VERSION 5.7 ;
  NOWIREEXTENSIONATPIN ON ;
  DIVIDERCHAR "/" ;
  BUSBITCHARS "[]" ;
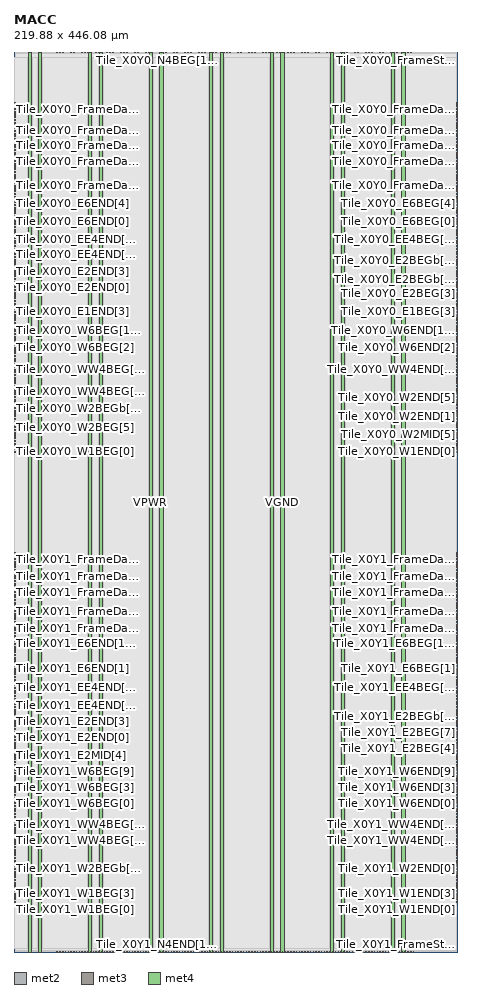
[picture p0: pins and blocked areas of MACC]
MACRO MACC
  CLASS BLOCK ;
  FOREIGN MACC ;
  ORIGIN 0.000 0.000 ;
  SIZE 219.880 BY 446.080 ;
  PIN Tile_X0Y0_CO
    DIRECTION OUTPUT ;
    USE SIGNAL ;
    ANTENNADIFFAREA 0.702900 ;
    PORT
      LAYER met2 ;
        RECT 98.530 445.800 98.810 446.080 ;
    END
  END Tile_X0Y0_CO
  PIN Tile_X0Y0_E1BEG[0]
    DIRECTION OUTPUT ;
    USE SIGNAL ;
    ANTENNADIFFAREA 0.702900 ;
    PORT
      LAYER met3 ;
        RECT 219.280 312.840 219.880 313.440 ;
    END
  END Tile_X0Y0_E1BEG[0]
  PIN Tile_X0Y0_E1BEG[1]
    DIRECTION OUTPUT ;
    USE SIGNAL ;
    ANTENNADIFFAREA 0.702900 ;
    PORT
      LAYER met3 ;
        RECT 219.280 314.200 219.880 314.800 ;
    END
  END Tile_X0Y0_E1BEG[1]
  PIN Tile_X0Y0_E1BEG[2]
    DIRECTION OUTPUT ;
    USE SIGNAL ;
    ANTENNADIFFAREA 0.702900 ;
    PORT
      LAYER met3 ;
        RECT 219.280 315.560 219.880 316.160 ;
    END
  END Tile_X0Y0_E1BEG[2]
  PIN Tile_X0Y0_E1BEG[3]
    DIRECTION OUTPUT ;
    USE SIGNAL ;
    ANTENNADIFFAREA 0.702900 ;
    PORT
      LAYER met3 ;
        RECT 219.280 316.920 219.880 317.520 ;
    END
  END Tile_X0Y0_E1BEG[3]
  PIN Tile_X0Y0_E1END[0]
    DIRECTION INPUT ;
    USE SIGNAL ;
    ANTENNAGATEAREA 2.603100 ;
    ANTENNADIFFAREA 1.304100 ;
    PORT
      LAYER met3 ;
        RECT 0.000 312.840 0.600 313.440 ;
    END
  END Tile_X0Y0_E1END[0]
  PIN Tile_X0Y0_E1END[1]
    DIRECTION INPUT ;
    USE SIGNAL ;
    ANTENNAGATEAREA 0.939000 ;
    PORT
      LAYER met3 ;
        RECT 0.000 314.200 0.600 314.800 ;
    END
  END Tile_X0Y0_E1END[1]
  PIN Tile_X0Y0_E1END[2]
    DIRECTION INPUT ;
    USE SIGNAL ;
    ANTENNAGATEAREA 1.749000 ;
    PORT
      LAYER met3 ;
        RECT 0.000 315.560 0.600 316.160 ;
    END
  END Tile_X0Y0_E1END[2]
  PIN Tile_X0Y0_E1END[3]
    DIRECTION INPUT ;
    USE SIGNAL ;
    ANTENNAGATEAREA 3.131400 ;
    ANTENNADIFFAREA 0.869400 ;
    PORT
      LAYER met3 ;
        RECT 0.000 316.920 0.600 317.520 ;
    END
  END Tile_X0Y0_E1END[3]
  PIN Tile_X0Y0_E2BEG[0]
    DIRECTION OUTPUT ;
    USE SIGNAL ;
    ANTENNADIFFAREA 0.702900 ;
    PORT
      LAYER met3 ;
        RECT 219.280 318.280 219.880 318.880 ;
    END
  END Tile_X0Y0_E2BEG[0]
  PIN Tile_X0Y0_E2BEG[1]
    DIRECTION OUTPUT ;
    USE SIGNAL ;
    ANTENNADIFFAREA 0.702900 ;
    PORT
      LAYER met3 ;
        RECT 219.280 319.640 219.880 320.240 ;
    END
  END Tile_X0Y0_E2BEG[1]
  PIN Tile_X0Y0_E2BEG[2]
    DIRECTION OUTPUT ;
    USE SIGNAL ;
    ANTENNADIFFAREA 0.702900 ;
    PORT
      LAYER met3 ;
        RECT 219.280 321.000 219.880 321.600 ;
    END
  END Tile_X0Y0_E2BEG[2]
  PIN Tile_X0Y0_E2BEG[3]
    DIRECTION OUTPUT ;
    USE SIGNAL ;
    ANTENNADIFFAREA 0.702900 ;
    PORT
      LAYER met3 ;
        RECT 219.280 322.360 219.880 322.960 ;
    END
  END Tile_X0Y0_E2BEG[3]
  PIN Tile_X0Y0_E2BEG[4]
    DIRECTION OUTPUT ;
    USE SIGNAL ;
    ANTENNADIFFAREA 0.702900 ;
    PORT
      LAYER met3 ;
        RECT 219.280 323.720 219.880 324.320 ;
    END
  END Tile_X0Y0_E2BEG[4]
  PIN Tile_X0Y0_E2BEG[5]
    DIRECTION OUTPUT ;
    USE SIGNAL ;
    ANTENNADIFFAREA 0.702900 ;
    PORT
      LAYER met3 ;
        RECT 219.280 325.080 219.880 325.680 ;
    END
  END Tile_X0Y0_E2BEG[5]
  PIN Tile_X0Y0_E2BEG[6]
    DIRECTION OUTPUT ;
    USE SIGNAL ;
    ANTENNADIFFAREA 0.702900 ;
    PORT
      LAYER met3 ;
        RECT 219.280 326.440 219.880 327.040 ;
    END
  END Tile_X0Y0_E2BEG[6]
  PIN Tile_X0Y0_E2BEG[7]
    DIRECTION OUTPUT ;
    USE SIGNAL ;
    ANTENNADIFFAREA 0.702900 ;
    PORT
      LAYER met3 ;
        RECT 219.280 327.800 219.880 328.400 ;
    END
  END Tile_X0Y0_E2BEG[7]
  PIN Tile_X0Y0_E2BEGb[0]
    DIRECTION OUTPUT ;
    USE SIGNAL ;
    ANTENNADIFFAREA 0.702900 ;
    PORT
      LAYER met3 ;
        RECT 219.280 329.160 219.880 329.760 ;
    END
  END Tile_X0Y0_E2BEGb[0]
  PIN Tile_X0Y0_E2BEGb[1]
    DIRECTION OUTPUT ;
    USE SIGNAL ;
    ANTENNADIFFAREA 0.702900 ;
    PORT
      LAYER met3 ;
        RECT 219.280 330.520 219.880 331.120 ;
    END
  END Tile_X0Y0_E2BEGb[1]
  PIN Tile_X0Y0_E2BEGb[2]
    DIRECTION OUTPUT ;
    USE SIGNAL ;
    ANTENNADIFFAREA 0.702900 ;
    PORT
      LAYER met3 ;
        RECT 219.280 331.880 219.880 332.480 ;
    END
  END Tile_X0Y0_E2BEGb[2]
  PIN Tile_X0Y0_E2BEGb[3]
    DIRECTION OUTPUT ;
    USE SIGNAL ;
    ANTENNADIFFAREA 0.702900 ;
    PORT
      LAYER met3 ;
        RECT 219.280 333.240 219.880 333.840 ;
    END
  END Tile_X0Y0_E2BEGb[3]
  PIN Tile_X0Y0_E2BEGb[4]
    DIRECTION OUTPUT ;
    USE SIGNAL ;
    ANTENNADIFFAREA 0.702900 ;
    PORT
      LAYER met3 ;
        RECT 219.280 334.600 219.880 335.200 ;
    END
  END Tile_X0Y0_E2BEGb[4]
  PIN Tile_X0Y0_E2BEGb[5]
    DIRECTION OUTPUT ;
    USE SIGNAL ;
    ANTENNADIFFAREA 0.702900 ;
    PORT
      LAYER met3 ;
        RECT 219.280 335.960 219.880 336.560 ;
    END
  END Tile_X0Y0_E2BEGb[5]
  PIN Tile_X0Y0_E2BEGb[6]
    DIRECTION OUTPUT ;
    USE SIGNAL ;
    ANTENNADIFFAREA 0.702900 ;
    PORT
      LAYER met3 ;
        RECT 219.280 337.320 219.880 337.920 ;
    END
  END Tile_X0Y0_E2BEGb[6]
  PIN Tile_X0Y0_E2BEGb[7]
    DIRECTION OUTPUT ;
    USE SIGNAL ;
    ANTENNADIFFAREA 0.702900 ;
    PORT
      LAYER met3 ;
        RECT 219.280 338.680 219.880 339.280 ;
    END
  END Tile_X0Y0_E2BEGb[7]
  PIN Tile_X0Y0_E2END[0]
    DIRECTION INPUT ;
    USE SIGNAL ;
    ANTENNAGATEAREA 0.971700 ;
    ANTENNADIFFAREA 0.434700 ;
    PORT
      LAYER met3 ;
        RECT 0.000 329.160 0.600 329.760 ;
    END
  END Tile_X0Y0_E2END[0]
  PIN Tile_X0Y0_E2END[1]
    DIRECTION INPUT ;
    USE SIGNAL ;
    ANTENNAGATEAREA 0.636000 ;
    PORT
      LAYER met3 ;
        RECT 0.000 330.520 0.600 331.120 ;
    END
  END Tile_X0Y0_E2END[1]
  PIN Tile_X0Y0_E2END[2]
    DIRECTION INPUT ;
    USE SIGNAL ;
    ANTENNAGATEAREA 1.168500 ;
    PORT
      LAYER met3 ;
        RECT 0.000 331.880 0.600 332.480 ;
    END
  END Tile_X0Y0_E2END[2]
  PIN Tile_X0Y0_E2END[3]
    DIRECTION INPUT ;
    USE SIGNAL ;
    ANTENNAGATEAREA 1.173000 ;
    PORT
      LAYER met3 ;
        RECT 0.000 333.240 0.600 333.840 ;
    END
  END Tile_X0Y0_E2END[3]
  PIN Tile_X0Y0_E2END[4]
    DIRECTION INPUT ;
    USE SIGNAL ;
    ANTENNAGATEAREA 1.229700 ;
    ANTENNADIFFAREA 0.434700 ;
    PORT
      LAYER met3 ;
        RECT 0.000 334.600 0.600 335.200 ;
    END
  END Tile_X0Y0_E2END[4]
  PIN Tile_X0Y0_E2END[5]
    DIRECTION INPUT ;
    USE SIGNAL ;
    ANTENNAGATEAREA 1.929000 ;
    PORT
      LAYER met3 ;
        RECT 0.000 335.960 0.600 336.560 ;
    END
  END Tile_X0Y0_E2END[5]
  PIN Tile_X0Y0_E2END[6]
    DIRECTION INPUT ;
    USE SIGNAL ;
    ANTENNAGATEAREA 1.388700 ;
    ANTENNADIFFAREA 0.434700 ;
    PORT
      LAYER met3 ;
        RECT 0.000 337.320 0.600 337.920 ;
    END
  END Tile_X0Y0_E2END[6]
  PIN Tile_X0Y0_E2END[7]
    DIRECTION INPUT ;
    USE SIGNAL ;
    ANTENNAGATEAREA 2.099100 ;
    ANTENNADIFFAREA 1.304100 ;
    PORT
      LAYER met3 ;
        RECT 0.000 338.680 0.600 339.280 ;
    END
  END Tile_X0Y0_E2END[7]
  PIN Tile_X0Y0_E2MID[0]
    DIRECTION INPUT ;
    USE SIGNAL ;
    ANTENNAGATEAREA 0.658500 ;
    PORT
      LAYER met3 ;
        RECT 0.000 318.280 0.600 318.880 ;
    END
  END Tile_X0Y0_E2MID[0]
  PIN Tile_X0Y0_E2MID[1]
    DIRECTION INPUT ;
    USE SIGNAL ;
    ANTENNAGATEAREA 0.696000 ;
    PORT
      LAYER met3 ;
        RECT 0.000 319.640 0.600 320.240 ;
    END
  END Tile_X0Y0_E2MID[1]
  PIN Tile_X0Y0_E2MID[2]
    DIRECTION INPUT ;
    USE SIGNAL ;
    ANTENNAGATEAREA 1.037700 ;
    ANTENNADIFFAREA 0.434700 ;
    PORT
      LAYER met3 ;
        RECT 0.000 321.000 0.600 321.600 ;
    END
  END Tile_X0Y0_E2MID[2]
  PIN Tile_X0Y0_E2MID[3]
    DIRECTION INPUT ;
    USE SIGNAL ;
    ANTENNAGATEAREA 0.795000 ;
    PORT
      LAYER met3 ;
        RECT 0.000 322.360 0.600 322.960 ;
    END
  END Tile_X0Y0_E2MID[3]
  PIN Tile_X0Y0_E2MID[4]
    DIRECTION INPUT ;
    USE SIGNAL ;
    ANTENNAGATEAREA 0.972000 ;
    PORT
      LAYER met3 ;
        RECT 0.000 323.720 0.600 324.320 ;
    END
  END Tile_X0Y0_E2MID[4]
  PIN Tile_X0Y0_E2MID[5]
    DIRECTION INPUT ;
    USE SIGNAL ;
    ANTENNAGATEAREA 1.555500 ;
    PORT
      LAYER met3 ;
        RECT 0.000 325.080 0.600 325.680 ;
    END
  END Tile_X0Y0_E2MID[5]
  PIN Tile_X0Y0_E2MID[6]
    DIRECTION INPUT ;
    USE SIGNAL ;
    ANTENNAGATEAREA 1.406700 ;
    ANTENNADIFFAREA 0.434700 ;
    PORT
      LAYER met3 ;
        RECT 0.000 326.440 0.600 327.040 ;
    END
  END Tile_X0Y0_E2MID[6]
  PIN Tile_X0Y0_E2MID[7]
    DIRECTION INPUT ;
    USE SIGNAL ;
    ANTENNAGATEAREA 0.901500 ;
    PORT
      LAYER met3 ;
        RECT 0.000 327.800 0.600 328.400 ;
    END
  END Tile_X0Y0_E2MID[7]
  PIN Tile_X0Y0_E6BEG[0]
    DIRECTION OUTPUT ;
    USE SIGNAL ;
    ANTENNADIFFAREA 0.702900 ;
    PORT
      LAYER met3 ;
        RECT 219.280 361.800 219.880 362.400 ;
    END
  END Tile_X0Y0_E6BEG[0]
  PIN Tile_X0Y0_E6BEG[10]
    DIRECTION OUTPUT ;
    USE SIGNAL ;
    ANTENNADIFFAREA 0.702900 ;
    PORT
      LAYER met3 ;
        RECT 219.280 375.400 219.880 376.000 ;
    END
  END Tile_X0Y0_E6BEG[10]
  PIN Tile_X0Y0_E6BEG[11]
    DIRECTION OUTPUT ;
    USE SIGNAL ;
    ANTENNADIFFAREA 0.702900 ;
    PORT
      LAYER met3 ;
        RECT 219.280 376.760 219.880 377.360 ;
    END
  END Tile_X0Y0_E6BEG[11]
  PIN Tile_X0Y0_E6BEG[1]
    DIRECTION OUTPUT ;
    USE SIGNAL ;
    ANTENNADIFFAREA 0.702900 ;
    PORT
      LAYER met3 ;
        RECT 219.280 363.160 219.880 363.760 ;
    END
  END Tile_X0Y0_E6BEG[1]
  PIN Tile_X0Y0_E6BEG[2]
    DIRECTION OUTPUT ;
    USE SIGNAL ;
    ANTENNADIFFAREA 0.702900 ;
    PORT
      LAYER met3 ;
        RECT 219.280 364.520 219.880 365.120 ;
    END
  END Tile_X0Y0_E6BEG[2]
  PIN Tile_X0Y0_E6BEG[3]
    DIRECTION OUTPUT ;
    USE SIGNAL ;
    ANTENNADIFFAREA 0.702900 ;
    PORT
      LAYER met3 ;
        RECT 219.280 365.880 219.880 366.480 ;
    END
  END Tile_X0Y0_E6BEG[3]
  PIN Tile_X0Y0_E6BEG[4]
    DIRECTION OUTPUT ;
    USE SIGNAL ;
    ANTENNADIFFAREA 0.702900 ;
    PORT
      LAYER met3 ;
        RECT 219.280 367.240 219.880 367.840 ;
    END
  END Tile_X0Y0_E6BEG[4]
  PIN Tile_X0Y0_E6BEG[5]
    DIRECTION OUTPUT ;
    USE SIGNAL ;
    ANTENNADIFFAREA 0.702900 ;
    PORT
      LAYER met3 ;
        RECT 219.280 368.600 219.880 369.200 ;
    END
  END Tile_X0Y0_E6BEG[5]
  PIN Tile_X0Y0_E6BEG[6]
    DIRECTION OUTPUT ;
    USE SIGNAL ;
    ANTENNADIFFAREA 0.702900 ;
    PORT
      LAYER met3 ;
        RECT 219.280 369.960 219.880 370.560 ;
    END
  END Tile_X0Y0_E6BEG[6]
  PIN Tile_X0Y0_E6BEG[7]
    DIRECTION OUTPUT ;
    USE SIGNAL ;
    ANTENNADIFFAREA 0.702900 ;
    PORT
      LAYER met3 ;
        RECT 219.280 371.320 219.880 371.920 ;
    END
  END Tile_X0Y0_E6BEG[7]
  PIN Tile_X0Y0_E6BEG[8]
    DIRECTION OUTPUT ;
    USE SIGNAL ;
    ANTENNADIFFAREA 0.702900 ;
    PORT
      LAYER met3 ;
        RECT 219.280 372.680 219.880 373.280 ;
    END
  END Tile_X0Y0_E6BEG[8]
  PIN Tile_X0Y0_E6BEG[9]
    DIRECTION OUTPUT ;
    USE SIGNAL ;
    ANTENNADIFFAREA 0.702900 ;
    PORT
      LAYER met3 ;
        RECT 219.280 374.040 219.880 374.640 ;
    END
  END Tile_X0Y0_E6BEG[9]
  PIN Tile_X0Y0_E6END[0]
    DIRECTION INPUT ;
    USE SIGNAL ;
    ANTENNAGATEAREA 2.243700 ;
    ANTENNADIFFAREA 0.434700 ;
    PORT
      LAYER met3 ;
        RECT 0.000 361.800 0.600 362.400 ;
    END
  END Tile_X0Y0_E6END[0]
  PIN Tile_X0Y0_E6END[10]
    DIRECTION INPUT ;
    USE SIGNAL ;
    ANTENNAGATEAREA 0.159000 ;
    PORT
      LAYER met3 ;
        RECT 0.000 375.400 0.600 376.000 ;
    END
  END Tile_X0Y0_E6END[10]
  PIN Tile_X0Y0_E6END[11]
    DIRECTION INPUT ;
    USE SIGNAL ;
    ANTENNAGATEAREA 0.159000 ;
    PORT
      LAYER met3 ;
        RECT 0.000 376.760 0.600 377.360 ;
    END
  END Tile_X0Y0_E6END[11]
  PIN Tile_X0Y0_E6END[1]
    DIRECTION INPUT ;
    USE SIGNAL ;
    ANTENNAGATEAREA 1.809000 ;
    PORT
      LAYER met3 ;
        RECT 0.000 363.160 0.600 363.760 ;
    END
  END Tile_X0Y0_E6END[1]
  PIN Tile_X0Y0_E6END[2]
    DIRECTION INPUT ;
    USE SIGNAL ;
    ANTENNAGATEAREA 0.159000 ;
    PORT
      LAYER met3 ;
        RECT 0.000 364.520 0.600 365.120 ;
    END
  END Tile_X0Y0_E6END[2]
  PIN Tile_X0Y0_E6END[3]
    DIRECTION INPUT ;
    USE SIGNAL ;
    ANTENNAGATEAREA 0.159000 ;
    PORT
      LAYER met3 ;
        RECT 0.000 365.880 0.600 366.480 ;
    END
  END Tile_X0Y0_E6END[3]
  PIN Tile_X0Y0_E6END[4]
    DIRECTION INPUT ;
    USE SIGNAL ;
    ANTENNAGATEAREA 0.159000 ;
    PORT
      LAYER met3 ;
        RECT 0.000 367.240 0.600 367.840 ;
    END
  END Tile_X0Y0_E6END[4]
  PIN Tile_X0Y0_E6END[5]
    DIRECTION INPUT ;
    USE SIGNAL ;
    ANTENNAGATEAREA 0.159000 ;
    PORT
      LAYER met3 ;
        RECT 0.000 368.600 0.600 369.200 ;
    END
  END Tile_X0Y0_E6END[5]
  PIN Tile_X0Y0_E6END[6]
    DIRECTION INPUT ;
    USE SIGNAL ;
    ANTENNAGATEAREA 0.159000 ;
    PORT
      LAYER met3 ;
        RECT 0.000 369.960 0.600 370.560 ;
    END
  END Tile_X0Y0_E6END[6]
  PIN Tile_X0Y0_E6END[7]
    DIRECTION INPUT ;
    USE SIGNAL ;
    ANTENNAGATEAREA 0.159000 ;
    PORT
      LAYER met3 ;
        RECT 0.000 371.320 0.600 371.920 ;
    END
  END Tile_X0Y0_E6END[7]
  PIN Tile_X0Y0_E6END[8]
    DIRECTION INPUT ;
    USE SIGNAL ;
    ANTENNAGATEAREA 0.159000 ;
    PORT
      LAYER met3 ;
        RECT 0.000 372.680 0.600 373.280 ;
    END
  END Tile_X0Y0_E6END[8]
  PIN Tile_X0Y0_E6END[9]
    DIRECTION INPUT ;
    USE SIGNAL ;
    ANTENNAGATEAREA 0.159000 ;
    PORT
      LAYER met3 ;
        RECT 0.000 374.040 0.600 374.640 ;
    END
  END Tile_X0Y0_E6END[9]
  PIN Tile_X0Y0_EE4BEG[0]
    DIRECTION OUTPUT ;
    USE SIGNAL ;
    ANTENNADIFFAREA 0.702900 ;
    PORT
      LAYER met3 ;
        RECT 219.280 340.040 219.880 340.640 ;
    END
  END Tile_X0Y0_EE4BEG[0]
  PIN Tile_X0Y0_EE4BEG[10]
    DIRECTION OUTPUT ;
    USE SIGNAL ;
    ANTENNADIFFAREA 0.702900 ;
    PORT
      LAYER met3 ;
        RECT 219.280 353.640 219.880 354.240 ;
    END
  END Tile_X0Y0_EE4BEG[10]
  PIN Tile_X0Y0_EE4BEG[11]
    DIRECTION OUTPUT ;
    USE SIGNAL ;
    ANTENNADIFFAREA 0.702900 ;
    PORT
      LAYER met3 ;
        RECT 219.280 355.000 219.880 355.600 ;
    END
  END Tile_X0Y0_EE4BEG[11]
  PIN Tile_X0Y0_EE4BEG[12]
    DIRECTION OUTPUT ;
    USE SIGNAL ;
    ANTENNADIFFAREA 0.702900 ;
    PORT
      LAYER met3 ;
        RECT 219.280 356.360 219.880 356.960 ;
    END
  END Tile_X0Y0_EE4BEG[12]
  PIN Tile_X0Y0_EE4BEG[13]
    DIRECTION OUTPUT ;
    USE SIGNAL ;
    ANTENNADIFFAREA 0.702900 ;
    PORT
      LAYER met3 ;
        RECT 219.280 357.720 219.880 358.320 ;
    END
  END Tile_X0Y0_EE4BEG[13]
  PIN Tile_X0Y0_EE4BEG[14]
    DIRECTION OUTPUT ;
    USE SIGNAL ;
    ANTENNADIFFAREA 0.702900 ;
    PORT
      LAYER met3 ;
        RECT 219.280 359.080 219.880 359.680 ;
    END
  END Tile_X0Y0_EE4BEG[14]
  PIN Tile_X0Y0_EE4BEG[15]
    DIRECTION OUTPUT ;
    USE SIGNAL ;
    ANTENNADIFFAREA 0.702900 ;
    PORT
      LAYER met3 ;
        RECT 219.280 360.440 219.880 361.040 ;
    END
  END Tile_X0Y0_EE4BEG[15]
  PIN Tile_X0Y0_EE4BEG[1]
    DIRECTION OUTPUT ;
    USE SIGNAL ;
    ANTENNADIFFAREA 0.702900 ;
    PORT
      LAYER met3 ;
        RECT 219.280 341.400 219.880 342.000 ;
    END
  END Tile_X0Y0_EE4BEG[1]
  PIN Tile_X0Y0_EE4BEG[2]
    DIRECTION OUTPUT ;
    USE SIGNAL ;
    ANTENNADIFFAREA 0.702900 ;
    PORT
      LAYER met3 ;
        RECT 219.280 342.760 219.880 343.360 ;
    END
  END Tile_X0Y0_EE4BEG[2]
  PIN Tile_X0Y0_EE4BEG[3]
    DIRECTION OUTPUT ;
    USE SIGNAL ;
    ANTENNADIFFAREA 0.702900 ;
    PORT
      LAYER met3 ;
        RECT 219.280 344.120 219.880 344.720 ;
    END
  END Tile_X0Y0_EE4BEG[3]
  PIN Tile_X0Y0_EE4BEG[4]
    DIRECTION OUTPUT ;
    USE SIGNAL ;
    ANTENNADIFFAREA 0.702900 ;
    PORT
      LAYER met3 ;
        RECT 219.280 345.480 219.880 346.080 ;
    END
  END Tile_X0Y0_EE4BEG[4]
  PIN Tile_X0Y0_EE4BEG[5]
    DIRECTION OUTPUT ;
    USE SIGNAL ;
    ANTENNADIFFAREA 0.702900 ;
    PORT
      LAYER met3 ;
        RECT 219.280 346.840 219.880 347.440 ;
    END
  END Tile_X0Y0_EE4BEG[5]
  PIN Tile_X0Y0_EE4BEG[6]
    DIRECTION OUTPUT ;
    USE SIGNAL ;
    ANTENNADIFFAREA 0.702900 ;
    PORT
      LAYER met3 ;
        RECT 219.280 348.200 219.880 348.800 ;
    END
  END Tile_X0Y0_EE4BEG[6]
  PIN Tile_X0Y0_EE4BEG[7]
    DIRECTION OUTPUT ;
    USE SIGNAL ;
    ANTENNADIFFAREA 0.702900 ;
    PORT
      LAYER met3 ;
        RECT 219.280 349.560 219.880 350.160 ;
    END
  END Tile_X0Y0_EE4BEG[7]
  PIN Tile_X0Y0_EE4BEG[8]
    DIRECTION OUTPUT ;
    USE SIGNAL ;
    ANTENNADIFFAREA 0.702900 ;
    PORT
      LAYER met3 ;
        RECT 219.280 350.920 219.880 351.520 ;
    END
  END Tile_X0Y0_EE4BEG[8]
  PIN Tile_X0Y0_EE4BEG[9]
    DIRECTION OUTPUT ;
    USE SIGNAL ;
    ANTENNADIFFAREA 0.702900 ;
    PORT
      LAYER met3 ;
        RECT 219.280 352.280 219.880 352.880 ;
    END
  END Tile_X0Y0_EE4BEG[9]
  PIN Tile_X0Y0_EE4END[0]
    DIRECTION INPUT ;
    USE SIGNAL ;
    ANTENNAGATEAREA 1.715100 ;
    ANTENNADIFFAREA 1.304100 ;
    PORT
      LAYER met3 ;
        RECT 0.000 340.040 0.600 340.640 ;
    END
  END Tile_X0Y0_EE4END[0]
  PIN Tile_X0Y0_EE4END[10]
    DIRECTION INPUT ;
    USE SIGNAL ;
    ANTENNAGATEAREA 0.159000 ;
    PORT
      LAYER met3 ;
        RECT 0.000 353.640 0.600 354.240 ;
    END
  END Tile_X0Y0_EE4END[10]
  PIN Tile_X0Y0_EE4END[11]
    DIRECTION INPUT ;
    USE SIGNAL ;
    ANTENNAGATEAREA 0.159000 ;
    PORT
      LAYER met3 ;
        RECT 0.000 355.000 0.600 355.600 ;
    END
  END Tile_X0Y0_EE4END[11]
  PIN Tile_X0Y0_EE4END[12]
    DIRECTION INPUT ;
    USE SIGNAL ;
    ANTENNAGATEAREA 0.159000 ;
    PORT
      LAYER met3 ;
        RECT 0.000 356.360 0.600 356.960 ;
    END
  END Tile_X0Y0_EE4END[12]
  PIN Tile_X0Y0_EE4END[13]
    DIRECTION INPUT ;
    USE SIGNAL ;
    ANTENNAGATEAREA 0.159000 ;
    PORT
      LAYER met3 ;
        RECT 0.000 357.720 0.600 358.320 ;
    END
  END Tile_X0Y0_EE4END[13]
  PIN Tile_X0Y0_EE4END[14]
    DIRECTION INPUT ;
    USE SIGNAL ;
    ANTENNAGATEAREA 0.159000 ;
    PORT
      LAYER met3 ;
        RECT 0.000 359.080 0.600 359.680 ;
    END
  END Tile_X0Y0_EE4END[14]
  PIN Tile_X0Y0_EE4END[15]
    DIRECTION INPUT ;
    USE SIGNAL ;
    ANTENNAGATEAREA 0.159000 ;
    PORT
      LAYER met3 ;
        RECT 0.000 360.440 0.600 361.040 ;
    END
  END Tile_X0Y0_EE4END[15]
  PIN Tile_X0Y0_EE4END[1]
    DIRECTION INPUT ;
    USE SIGNAL ;
    ANTENNAGATEAREA 0.477000 ;
    PORT
      LAYER met3 ;
        RECT 0.000 341.400 0.600 342.000 ;
    END
  END Tile_X0Y0_EE4END[1]
  PIN Tile_X0Y0_EE4END[2]
    DIRECTION INPUT ;
    USE SIGNAL ;
    ANTENNAGATEAREA 1.781100 ;
    ANTENNADIFFAREA 1.304100 ;
    PORT
      LAYER met3 ;
        RECT 0.000 342.760 0.600 343.360 ;
    END
  END Tile_X0Y0_EE4END[2]
  PIN Tile_X0Y0_EE4END[3]
    DIRECTION INPUT ;
    USE SIGNAL ;
    ANTENNAGATEAREA 0.752700 ;
    ANTENNADIFFAREA 0.434700 ;
    PORT
      LAYER met3 ;
        RECT 0.000 344.120 0.600 344.720 ;
    END
  END Tile_X0Y0_EE4END[3]
  PIN Tile_X0Y0_EE4END[4]
    DIRECTION INPUT ;
    USE SIGNAL ;
    ANTENNAGATEAREA 0.159000 ;
    PORT
      LAYER met3 ;
        RECT 0.000 345.480 0.600 346.080 ;
    END
  END Tile_X0Y0_EE4END[4]
  PIN Tile_X0Y0_EE4END[5]
    DIRECTION INPUT ;
    USE SIGNAL ;
    ANTENNAGATEAREA 0.159000 ;
    PORT
      LAYER met3 ;
        RECT 0.000 346.840 0.600 347.440 ;
    END
  END Tile_X0Y0_EE4END[5]
  PIN Tile_X0Y0_EE4END[6]
    DIRECTION INPUT ;
    USE SIGNAL ;
    ANTENNAGATEAREA 0.159000 ;
    PORT
      LAYER met3 ;
        RECT 0.000 348.200 0.600 348.800 ;
    END
  END Tile_X0Y0_EE4END[6]
  PIN Tile_X0Y0_EE4END[7]
    DIRECTION INPUT ;
    USE SIGNAL ;
    ANTENNAGATEAREA 0.159000 ;
    PORT
      LAYER met3 ;
        RECT 0.000 349.560 0.600 350.160 ;
    END
  END Tile_X0Y0_EE4END[7]
  PIN Tile_X0Y0_EE4END[8]
    DIRECTION INPUT ;
    USE SIGNAL ;
    ANTENNAGATEAREA 0.159000 ;
    PORT
      LAYER met3 ;
        RECT 0.000 350.920 0.600 351.520 ;
    END
  END Tile_X0Y0_EE4END[8]
  PIN Tile_X0Y0_EE4END[9]
    DIRECTION INPUT ;
    USE SIGNAL ;
    ANTENNAGATEAREA 0.159000 ;
    PORT
      LAYER met3 ;
        RECT 0.000 352.280 0.600 352.880 ;
    END
  END Tile_X0Y0_EE4END[9]
  PIN Tile_X0Y0_FrameData[0]
    DIRECTION INPUT ;
    USE SIGNAL ;
    ANTENNAGATEAREA 2.067000 ;
    PORT
      LAYER met3 ;
        RECT 0.000 378.120 0.600 378.720 ;
    END
  END Tile_X0Y0_FrameData[0]
  PIN Tile_X0Y0_FrameData[10]
    DIRECTION INPUT ;
    USE SIGNAL ;
    ANTENNAGATEAREA 2.226000 ;
    PORT
      LAYER met3 ;
        RECT 0.000 391.720 0.600 392.320 ;
    END
  END Tile_X0Y0_FrameData[10]
  PIN Tile_X0Y0_FrameData[11]
    DIRECTION INPUT ;
    USE SIGNAL ;
    ANTENNAGATEAREA 2.226000 ;
    PORT
      LAYER met3 ;
        RECT 0.000 393.080 0.600 393.680 ;
    END
  END Tile_X0Y0_FrameData[11]
  PIN Tile_X0Y0_FrameData[12]
    DIRECTION INPUT ;
    USE SIGNAL ;
    ANTENNAGATEAREA 2.226000 ;
    PORT
      LAYER met3 ;
        RECT 0.000 394.440 0.600 395.040 ;
    END
  END Tile_X0Y0_FrameData[12]
  PIN Tile_X0Y0_FrameData[13]
    DIRECTION INPUT ;
    USE SIGNAL ;
    ANTENNAGATEAREA 3.095400 ;
    ANTENNADIFFAREA 0.869400 ;
    PORT
      LAYER met3 ;
        RECT 0.000 395.800 0.600 396.400 ;
    END
  END Tile_X0Y0_FrameData[13]
  PIN Tile_X0Y0_FrameData[14]
    DIRECTION INPUT ;
    USE SIGNAL ;
    ANTENNAGATEAREA 2.226000 ;
    PORT
      LAYER met3 ;
        RECT 0.000 397.160 0.600 397.760 ;
    END
  END Tile_X0Y0_FrameData[14]
  PIN Tile_X0Y0_FrameData[15]
    DIRECTION INPUT ;
    USE SIGNAL ;
    ANTENNAGATEAREA 2.226000 ;
    PORT
      LAYER met3 ;
        RECT 0.000 398.520 0.600 399.120 ;
    END
  END Tile_X0Y0_FrameData[15]
  PIN Tile_X0Y0_FrameData[16]
    DIRECTION INPUT ;
    USE SIGNAL ;
    ANTENNAGATEAREA 2.226000 ;
    PORT
      LAYER met3 ;
        RECT 0.000 399.880 0.600 400.480 ;
    END
  END Tile_X0Y0_FrameData[16]
  PIN Tile_X0Y0_FrameData[17]
    DIRECTION INPUT ;
    USE SIGNAL ;
    ANTENNAGATEAREA 2.226000 ;
    PORT
      LAYER met3 ;
        RECT 0.000 401.240 0.600 401.840 ;
    END
  END Tile_X0Y0_FrameData[17]
  PIN Tile_X0Y0_FrameData[18]
    DIRECTION INPUT ;
    USE SIGNAL ;
    ANTENNAGATEAREA 2.226000 ;
    PORT
      LAYER met3 ;
        RECT 0.000 402.600 0.600 403.200 ;
    END
  END Tile_X0Y0_FrameData[18]
  PIN Tile_X0Y0_FrameData[19]
    DIRECTION INPUT ;
    USE SIGNAL ;
    ANTENNAGATEAREA 2.226000 ;
    PORT
      LAYER met3 ;
        RECT 0.000 403.960 0.600 404.560 ;
    END
  END Tile_X0Y0_FrameData[19]
  PIN Tile_X0Y0_FrameData[1]
    DIRECTION INPUT ;
    USE SIGNAL ;
    ANTENNAGATEAREA 2.067000 ;
    PORT
      LAYER met3 ;
        RECT 0.000 379.480 0.600 380.080 ;
    END
  END Tile_X0Y0_FrameData[1]
  PIN Tile_X0Y0_FrameData[20]
    DIRECTION INPUT ;
    USE SIGNAL ;
    ANTENNAGATEAREA 2.226000 ;
    PORT
      LAYER met3 ;
        RECT 0.000 405.320 0.600 405.920 ;
    END
  END Tile_X0Y0_FrameData[20]
  PIN Tile_X0Y0_FrameData[21]
    DIRECTION INPUT ;
    USE SIGNAL ;
    ANTENNAGATEAREA 2.226000 ;
    PORT
      LAYER met3 ;
        RECT 0.000 406.680 0.600 407.280 ;
    END
  END Tile_X0Y0_FrameData[21]
  PIN Tile_X0Y0_FrameData[22]
    DIRECTION INPUT ;
    USE SIGNAL ;
    ANTENNAGATEAREA 2.226000 ;
    PORT
      LAYER met3 ;
        RECT 0.000 408.040 0.600 408.640 ;
    END
  END Tile_X0Y0_FrameData[22]
  PIN Tile_X0Y0_FrameData[23]
    DIRECTION INPUT ;
    USE SIGNAL ;
    ANTENNAGATEAREA 2.226000 ;
    PORT
      LAYER met3 ;
        RECT 0.000 409.400 0.600 410.000 ;
    END
  END Tile_X0Y0_FrameData[23]
  PIN Tile_X0Y0_FrameData[24]
    DIRECTION INPUT ;
    USE SIGNAL ;
    ANTENNAGATEAREA 2.226000 ;
    PORT
      LAYER met3 ;
        RECT 0.000 410.760 0.600 411.360 ;
    END
  END Tile_X0Y0_FrameData[24]
  PIN Tile_X0Y0_FrameData[25]
    DIRECTION INPUT ;
    USE SIGNAL ;
    ANTENNAGATEAREA 2.226000 ;
    PORT
      LAYER met3 ;
        RECT 0.000 412.120 0.600 412.720 ;
    END
  END Tile_X0Y0_FrameData[25]
  PIN Tile_X0Y0_FrameData[26]
    DIRECTION INPUT ;
    USE SIGNAL ;
    ANTENNAGATEAREA 2.226000 ;
    PORT
      LAYER met3 ;
        RECT 0.000 413.480 0.600 414.080 ;
    END
  END Tile_X0Y0_FrameData[26]
  PIN Tile_X0Y0_FrameData[27]
    DIRECTION INPUT ;
    USE SIGNAL ;
    ANTENNAGATEAREA 2.660700 ;
    ANTENNADIFFAREA 0.434700 ;
    PORT
      LAYER met3 ;
        RECT 0.000 414.840 0.600 415.440 ;
    END
  END Tile_X0Y0_FrameData[27]
  PIN Tile_X0Y0_FrameData[28]
    DIRECTION INPUT ;
    USE SIGNAL ;
    ANTENNAGATEAREA 2.226000 ;
    PORT
      LAYER met3 ;
        RECT 0.000 416.200 0.600 416.800 ;
    END
  END Tile_X0Y0_FrameData[28]
  PIN Tile_X0Y0_FrameData[29]
    DIRECTION INPUT ;
    USE SIGNAL ;
    ANTENNAGATEAREA 2.660700 ;
    ANTENNADIFFAREA 0.434700 ;
    PORT
      LAYER met3 ;
        RECT 0.000 417.560 0.600 418.160 ;
    END
  END Tile_X0Y0_FrameData[29]
  PIN Tile_X0Y0_FrameData[2]
    DIRECTION INPUT ;
    USE SIGNAL ;
    ANTENNAGATEAREA 2.501700 ;
    ANTENNADIFFAREA 0.434700 ;
    PORT
      LAYER met3 ;
        RECT 0.000 380.840 0.600 381.440 ;
    END
  END Tile_X0Y0_FrameData[2]
  PIN Tile_X0Y0_FrameData[30]
    DIRECTION INPUT ;
    USE SIGNAL ;
    ANTENNAGATEAREA 2.226000 ;
    PORT
      LAYER met3 ;
        RECT 0.000 418.920 0.600 419.520 ;
    END
  END Tile_X0Y0_FrameData[30]
  PIN Tile_X0Y0_FrameData[31]
    DIRECTION INPUT ;
    USE SIGNAL ;
    ANTENNAGATEAREA 2.226000 ;
    PORT
      LAYER met3 ;
        RECT 0.000 420.280 0.600 420.880 ;
    END
  END Tile_X0Y0_FrameData[31]
  PIN Tile_X0Y0_FrameData[3]
    DIRECTION INPUT ;
    USE SIGNAL ;
    ANTENNAGATEAREA 2.067000 ;
    PORT
      LAYER met3 ;
        RECT 0.000 382.200 0.600 382.800 ;
    END
  END Tile_X0Y0_FrameData[3]
  PIN Tile_X0Y0_FrameData[4]
    DIRECTION INPUT ;
    USE SIGNAL ;
    ANTENNAGATEAREA 2.067000 ;
    PORT
      LAYER met3 ;
        RECT 0.000 383.560 0.600 384.160 ;
    END
  END Tile_X0Y0_FrameData[4]
  PIN Tile_X0Y0_FrameData[5]
    DIRECTION INPUT ;
    USE SIGNAL ;
    ANTENNAGATEAREA 4.240500 ;
    ANTENNADIFFAREA 2.173500 ;
    PORT
      LAYER met3 ;
        RECT 0.000 384.920 0.600 385.520 ;
    END
  END Tile_X0Y0_FrameData[5]
  PIN Tile_X0Y0_FrameData[6]
    DIRECTION INPUT ;
    USE SIGNAL ;
    ANTENNAGATEAREA 2.067000 ;
    PORT
      LAYER met3 ;
        RECT 0.000 386.280 0.600 386.880 ;
    END
  END Tile_X0Y0_FrameData[6]
  PIN Tile_X0Y0_FrameData[7]
    DIRECTION INPUT ;
    USE SIGNAL ;
    ANTENNAGATEAREA 2.067000 ;
    PORT
      LAYER met3 ;
        RECT 0.000 387.640 0.600 388.240 ;
    END
  END Tile_X0Y0_FrameData[7]
  PIN Tile_X0Y0_FrameData[8]
    DIRECTION INPUT ;
    USE SIGNAL ;
    ANTENNAGATEAREA 2.067000 ;
    PORT
      LAYER met3 ;
        RECT 0.000 389.000 0.600 389.600 ;
    END
  END Tile_X0Y0_FrameData[8]
  PIN Tile_X0Y0_FrameData[9]
    DIRECTION INPUT ;
    USE SIGNAL ;
    ANTENNAGATEAREA 2.067000 ;
    PORT
      LAYER met3 ;
        RECT 0.000 390.360 0.600 390.960 ;
    END
  END Tile_X0Y0_FrameData[9]
  PIN Tile_X0Y0_FrameData_O[0]
    DIRECTION OUTPUT ;
    USE SIGNAL ;
    ANTENNADIFFAREA 0.702900 ;
    PORT
      LAYER met3 ;
        RECT 219.280 378.120 219.880 378.720 ;
    END
  END Tile_X0Y0_FrameData_O[0]
  PIN Tile_X0Y0_FrameData_O[10]
    DIRECTION OUTPUT ;
    USE SIGNAL ;
    ANTENNADIFFAREA 0.702900 ;
    PORT
      LAYER met3 ;
        RECT 219.280 391.720 219.880 392.320 ;
    END
  END Tile_X0Y0_FrameData_O[10]
  PIN Tile_X0Y0_FrameData_O[11]
    DIRECTION OUTPUT ;
    USE SIGNAL ;
    ANTENNADIFFAREA 0.702900 ;
    PORT
      LAYER met3 ;
        RECT 219.280 393.080 219.880 393.680 ;
    END
  END Tile_X0Y0_FrameData_O[11]
  PIN Tile_X0Y0_FrameData_O[12]
    DIRECTION OUTPUT ;
    USE SIGNAL ;
    ANTENNADIFFAREA 0.702900 ;
    PORT
      LAYER met3 ;
        RECT 219.280 394.440 219.880 395.040 ;
    END
  END Tile_X0Y0_FrameData_O[12]
  PIN Tile_X0Y0_FrameData_O[13]
    DIRECTION OUTPUT ;
    USE SIGNAL ;
    ANTENNADIFFAREA 0.702900 ;
    PORT
      LAYER met3 ;
        RECT 219.280 395.800 219.880 396.400 ;
    END
  END Tile_X0Y0_FrameData_O[13]
  PIN Tile_X0Y0_FrameData_O[14]
    DIRECTION OUTPUT ;
    USE SIGNAL ;
    ANTENNADIFFAREA 0.702900 ;
    PORT
      LAYER met3 ;
        RECT 219.280 397.160 219.880 397.760 ;
    END
  END Tile_X0Y0_FrameData_O[14]
  PIN Tile_X0Y0_FrameData_O[15]
    DIRECTION OUTPUT ;
    USE SIGNAL ;
    ANTENNADIFFAREA 0.702900 ;
    PORT
      LAYER met3 ;
        RECT 219.280 398.520 219.880 399.120 ;
    END
  END Tile_X0Y0_FrameData_O[15]
  PIN Tile_X0Y0_FrameData_O[16]
    DIRECTION OUTPUT ;
    USE SIGNAL ;
    ANTENNADIFFAREA 0.702900 ;
    PORT
      LAYER met3 ;
        RECT 219.280 399.880 219.880 400.480 ;
    END
  END Tile_X0Y0_FrameData_O[16]
  PIN Tile_X0Y0_FrameData_O[17]
    DIRECTION OUTPUT ;
    USE SIGNAL ;
    ANTENNADIFFAREA 0.702900 ;
    PORT
      LAYER met3 ;
        RECT 219.280 401.240 219.880 401.840 ;
    END
  END Tile_X0Y0_FrameData_O[17]
  PIN Tile_X0Y0_FrameData_O[18]
    DIRECTION OUTPUT ;
    USE SIGNAL ;
    ANTENNADIFFAREA 0.702900 ;
    PORT
      LAYER met3 ;
        RECT 219.280 402.600 219.880 403.200 ;
    END
  END Tile_X0Y0_FrameData_O[18]
  PIN Tile_X0Y0_FrameData_O[19]
    DIRECTION OUTPUT ;
    USE SIGNAL ;
    ANTENNADIFFAREA 0.702900 ;
    PORT
      LAYER met3 ;
        RECT 219.280 403.960 219.880 404.560 ;
    END
  END Tile_X0Y0_FrameData_O[19]
  PIN Tile_X0Y0_FrameData_O[1]
    DIRECTION OUTPUT ;
    USE SIGNAL ;
    ANTENNADIFFAREA 0.702900 ;
    PORT
      LAYER met3 ;
        RECT 219.280 379.480 219.880 380.080 ;
    END
  END Tile_X0Y0_FrameData_O[1]
  PIN Tile_X0Y0_FrameData_O[20]
    DIRECTION OUTPUT ;
    USE SIGNAL ;
    ANTENNADIFFAREA 0.702900 ;
    PORT
      LAYER met3 ;
        RECT 219.280 405.320 219.880 405.920 ;
    END
  END Tile_X0Y0_FrameData_O[20]
  PIN Tile_X0Y0_FrameData_O[21]
    DIRECTION OUTPUT ;
    USE SIGNAL ;
    ANTENNADIFFAREA 0.702900 ;
    PORT
      LAYER met3 ;
        RECT 219.280 406.680 219.880 407.280 ;
    END
  END Tile_X0Y0_FrameData_O[21]
  PIN Tile_X0Y0_FrameData_O[22]
    DIRECTION OUTPUT ;
    USE SIGNAL ;
    ANTENNADIFFAREA 0.702900 ;
    PORT
      LAYER met3 ;
        RECT 219.280 408.040 219.880 408.640 ;
    END
  END Tile_X0Y0_FrameData_O[22]
  PIN Tile_X0Y0_FrameData_O[23]
    DIRECTION OUTPUT ;
    USE SIGNAL ;
    ANTENNADIFFAREA 0.702900 ;
    PORT
      LAYER met3 ;
        RECT 219.280 409.400 219.880 410.000 ;
    END
  END Tile_X0Y0_FrameData_O[23]
  PIN Tile_X0Y0_FrameData_O[24]
    DIRECTION OUTPUT ;
    USE SIGNAL ;
    ANTENNADIFFAREA 0.702900 ;
    PORT
      LAYER met3 ;
        RECT 219.280 410.760 219.880 411.360 ;
    END
  END Tile_X0Y0_FrameData_O[24]
  PIN Tile_X0Y0_FrameData_O[25]
    DIRECTION OUTPUT ;
    USE SIGNAL ;
    ANTENNADIFFAREA 0.702900 ;
    PORT
      LAYER met3 ;
        RECT 219.280 412.120 219.880 412.720 ;
    END
  END Tile_X0Y0_FrameData_O[25]
  PIN Tile_X0Y0_FrameData_O[26]
    DIRECTION OUTPUT ;
    USE SIGNAL ;
    ANTENNADIFFAREA 0.702900 ;
    PORT
      LAYER met3 ;
        RECT 219.280 413.480 219.880 414.080 ;
    END
  END Tile_X0Y0_FrameData_O[26]
  PIN Tile_X0Y0_FrameData_O[27]
    DIRECTION OUTPUT ;
    USE SIGNAL ;
    ANTENNADIFFAREA 0.702900 ;
    PORT
      LAYER met3 ;
        RECT 219.280 414.840 219.880 415.440 ;
    END
  END Tile_X0Y0_FrameData_O[27]
  PIN Tile_X0Y0_FrameData_O[28]
    DIRECTION OUTPUT ;
    USE SIGNAL ;
    ANTENNADIFFAREA 0.702900 ;
    PORT
      LAYER met3 ;
        RECT 219.280 416.200 219.880 416.800 ;
    END
  END Tile_X0Y0_FrameData_O[28]
  PIN Tile_X0Y0_FrameData_O[29]
    DIRECTION OUTPUT ;
    USE SIGNAL ;
    ANTENNADIFFAREA 0.702900 ;
    PORT
      LAYER met3 ;
        RECT 219.280 417.560 219.880 418.160 ;
    END
  END Tile_X0Y0_FrameData_O[29]
  PIN Tile_X0Y0_FrameData_O[2]
    DIRECTION OUTPUT ;
    USE SIGNAL ;
    ANTENNADIFFAREA 0.702900 ;
    PORT
      LAYER met3 ;
        RECT 219.280 380.840 219.880 381.440 ;
    END
  END Tile_X0Y0_FrameData_O[2]
  PIN Tile_X0Y0_FrameData_O[30]
    DIRECTION OUTPUT ;
    USE SIGNAL ;
    ANTENNADIFFAREA 0.702900 ;
    PORT
      LAYER met3 ;
        RECT 219.280 418.920 219.880 419.520 ;
    END
  END Tile_X0Y0_FrameData_O[30]
  PIN Tile_X0Y0_FrameData_O[31]
    DIRECTION OUTPUT ;
    USE SIGNAL ;
    ANTENNADIFFAREA 0.702900 ;
    PORT
      LAYER met3 ;
        RECT 219.280 420.280 219.880 420.880 ;
    END
  END Tile_X0Y0_FrameData_O[31]
  PIN Tile_X0Y0_FrameData_O[3]
    DIRECTION OUTPUT ;
    USE SIGNAL ;
    ANTENNADIFFAREA 0.702900 ;
    PORT
      LAYER met3 ;
        RECT 219.280 382.200 219.880 382.800 ;
    END
  END Tile_X0Y0_FrameData_O[3]
  PIN Tile_X0Y0_FrameData_O[4]
    DIRECTION OUTPUT ;
    USE SIGNAL ;
    ANTENNADIFFAREA 0.702900 ;
    PORT
      LAYER met3 ;
        RECT 219.280 383.560 219.880 384.160 ;
    END
  END Tile_X0Y0_FrameData_O[4]
  PIN Tile_X0Y0_FrameData_O[5]
    DIRECTION OUTPUT ;
    USE SIGNAL ;
    ANTENNADIFFAREA 0.702900 ;
    PORT
      LAYER met3 ;
        RECT 219.280 384.920 219.880 385.520 ;
    END
  END Tile_X0Y0_FrameData_O[5]
  PIN Tile_X0Y0_FrameData_O[6]
    DIRECTION OUTPUT ;
    USE SIGNAL ;
    ANTENNADIFFAREA 0.702900 ;
    PORT
      LAYER met3 ;
        RECT 219.280 386.280 219.880 386.880 ;
    END
  END Tile_X0Y0_FrameData_O[6]
  PIN Tile_X0Y0_FrameData_O[7]
    DIRECTION OUTPUT ;
    USE SIGNAL ;
    ANTENNADIFFAREA 0.702900 ;
    PORT
      LAYER met3 ;
        RECT 219.280 387.640 219.880 388.240 ;
    END
  END Tile_X0Y0_FrameData_O[7]
  PIN Tile_X0Y0_FrameData_O[8]
    DIRECTION OUTPUT ;
    USE SIGNAL ;
    ANTENNADIFFAREA 0.702900 ;
    PORT
      LAYER met3 ;
        RECT 219.280 389.000 219.880 389.600 ;
    END
  END Tile_X0Y0_FrameData_O[8]
  PIN Tile_X0Y0_FrameData_O[9]
    DIRECTION OUTPUT ;
    USE SIGNAL ;
    ANTENNADIFFAREA 0.702900 ;
    PORT
      LAYER met3 ;
        RECT 219.280 390.360 219.880 390.960 ;
    END
  END Tile_X0Y0_FrameData_O[9]
  PIN Tile_X0Y0_FrameStrobe_O[0]
    DIRECTION OUTPUT ;
    USE SIGNAL ;
    ANTENNADIFFAREA 0.702900 ;
    PORT
      LAYER met2 ;
        RECT 171.670 445.800 171.950 446.080 ;
    END
  END Tile_X0Y0_FrameStrobe_O[0]
  PIN Tile_X0Y0_FrameStrobe_O[10]
    DIRECTION OUTPUT ;
    USE SIGNAL ;
    ANTENNADIFFAREA 0.702900 ;
    PORT
      LAYER met2 ;
        RECT 185.470 445.800 185.750 446.080 ;
    END
  END Tile_X0Y0_FrameStrobe_O[10]
  PIN Tile_X0Y0_FrameStrobe_O[11]
    DIRECTION OUTPUT ;
    USE SIGNAL ;
    ANTENNADIFFAREA 0.702900 ;
    PORT
      LAYER met2 ;
        RECT 186.850 445.800 187.130 446.080 ;
    END
  END Tile_X0Y0_FrameStrobe_O[11]
  PIN Tile_X0Y0_FrameStrobe_O[12]
    DIRECTION OUTPUT ;
    USE SIGNAL ;
    ANTENNADIFFAREA 0.702900 ;
    PORT
      LAYER met2 ;
        RECT 188.230 445.800 188.510 446.080 ;
    END
  END Tile_X0Y0_FrameStrobe_O[12]
  PIN Tile_X0Y0_FrameStrobe_O[13]
    DIRECTION OUTPUT ;
    USE SIGNAL ;
    ANTENNADIFFAREA 0.702900 ;
    PORT
      LAYER met2 ;
        RECT 189.610 445.800 189.890 446.080 ;
    END
  END Tile_X0Y0_FrameStrobe_O[13]
  PIN Tile_X0Y0_FrameStrobe_O[14]
    DIRECTION OUTPUT ;
    USE SIGNAL ;
    ANTENNADIFFAREA 0.702900 ;
    PORT
      LAYER met2 ;
        RECT 190.990 445.800 191.270 446.080 ;
    END
  END Tile_X0Y0_FrameStrobe_O[14]
  PIN Tile_X0Y0_FrameStrobe_O[15]
    DIRECTION OUTPUT ;
    USE SIGNAL ;
    ANTENNADIFFAREA 0.702900 ;
    PORT
      LAYER met2 ;
        RECT 192.370 445.800 192.650 446.080 ;
    END
  END Tile_X0Y0_FrameStrobe_O[15]
  PIN Tile_X0Y0_FrameStrobe_O[16]
    DIRECTION OUTPUT ;
    USE SIGNAL ;
    ANTENNADIFFAREA 0.702900 ;
    PORT
      LAYER met2 ;
        RECT 193.750 445.800 194.030 446.080 ;
    END
  END Tile_X0Y0_FrameStrobe_O[16]
  PIN Tile_X0Y0_FrameStrobe_O[17]
    DIRECTION OUTPUT ;
    USE SIGNAL ;
    ANTENNADIFFAREA 0.702900 ;
    PORT
      LAYER met2 ;
        RECT 195.130 445.800 195.410 446.080 ;
    END
  END Tile_X0Y0_FrameStrobe_O[17]
  PIN Tile_X0Y0_FrameStrobe_O[18]
    DIRECTION OUTPUT ;
    USE SIGNAL ;
    ANTENNADIFFAREA 0.702900 ;
    PORT
      LAYER met2 ;
        RECT 196.510 445.800 196.790 446.080 ;
    END
  END Tile_X0Y0_FrameStrobe_O[18]
  PIN Tile_X0Y0_FrameStrobe_O[19]
    DIRECTION OUTPUT ;
    USE SIGNAL ;
    ANTENNADIFFAREA 0.702900 ;
    PORT
      LAYER met2 ;
        RECT 197.890 445.800 198.170 446.080 ;
    END
  END Tile_X0Y0_FrameStrobe_O[19]
  PIN Tile_X0Y0_FrameStrobe_O[1]
    DIRECTION OUTPUT ;
    USE SIGNAL ;
    ANTENNADIFFAREA 0.702900 ;
    PORT
      LAYER met2 ;
        RECT 173.050 445.800 173.330 446.080 ;
    END
  END Tile_X0Y0_FrameStrobe_O[1]
  PIN Tile_X0Y0_FrameStrobe_O[2]
    DIRECTION OUTPUT ;
    USE SIGNAL ;
    ANTENNADIFFAREA 0.702900 ;
    PORT
      LAYER met2 ;
        RECT 174.430 445.800 174.710 446.080 ;
    END
  END Tile_X0Y0_FrameStrobe_O[2]
  PIN Tile_X0Y0_FrameStrobe_O[3]
    DIRECTION OUTPUT ;
    USE SIGNAL ;
    ANTENNADIFFAREA 0.702900 ;
    PORT
      LAYER met2 ;
        RECT 175.810 445.800 176.090 446.080 ;
    END
  END Tile_X0Y0_FrameStrobe_O[3]
  PIN Tile_X0Y0_FrameStrobe_O[4]
    DIRECTION OUTPUT ;
    USE SIGNAL ;
    ANTENNADIFFAREA 0.702900 ;
    PORT
      LAYER met2 ;
        RECT 177.190 445.800 177.470 446.080 ;
    END
  END Tile_X0Y0_FrameStrobe_O[4]
  PIN Tile_X0Y0_FrameStrobe_O[5]
    DIRECTION OUTPUT ;
    USE SIGNAL ;
    ANTENNADIFFAREA 0.702900 ;
    PORT
      LAYER met2 ;
        RECT 178.570 445.800 178.850 446.080 ;
    END
  END Tile_X0Y0_FrameStrobe_O[5]
  PIN Tile_X0Y0_FrameStrobe_O[6]
    DIRECTION OUTPUT ;
    USE SIGNAL ;
    ANTENNADIFFAREA 0.702900 ;
    PORT
      LAYER met2 ;
        RECT 179.950 445.800 180.230 446.080 ;
    END
  END Tile_X0Y0_FrameStrobe_O[6]
  PIN Tile_X0Y0_FrameStrobe_O[7]
    DIRECTION OUTPUT ;
    USE SIGNAL ;
    ANTENNADIFFAREA 0.702900 ;
    PORT
      LAYER met2 ;
        RECT 181.330 445.800 181.610 446.080 ;
    END
  END Tile_X0Y0_FrameStrobe_O[7]
  PIN Tile_X0Y0_FrameStrobe_O[8]
    DIRECTION OUTPUT ;
    USE SIGNAL ;
    ANTENNADIFFAREA 0.702900 ;
    PORT
      LAYER met2 ;
        RECT 182.710 445.800 182.990 446.080 ;
    END
  END Tile_X0Y0_FrameStrobe_O[8]
  PIN Tile_X0Y0_FrameStrobe_O[9]
    DIRECTION OUTPUT ;
    USE SIGNAL ;
    ANTENNADIFFAREA 0.702900 ;
    PORT
      LAYER met2 ;
        RECT 184.090 445.800 184.370 446.080 ;
    END
  END Tile_X0Y0_FrameStrobe_O[9]
  PIN Tile_X0Y0_N1BEG[0]
    DIRECTION OUTPUT ;
    USE SIGNAL ;
    ANTENNADIFFAREA 0.702900 ;
    PORT
      LAYER met2 ;
        RECT 26.770 445.800 27.050 446.080 ;
    END
  END Tile_X0Y0_N1BEG[0]
  PIN Tile_X0Y0_N1BEG[1]
    DIRECTION OUTPUT ;
    USE SIGNAL ;
    ANTENNADIFFAREA 0.702900 ;
    PORT
      LAYER met2 ;
        RECT 28.150 445.800 28.430 446.080 ;
    END
  END Tile_X0Y0_N1BEG[1]
  PIN Tile_X0Y0_N1BEG[2]
    DIRECTION OUTPUT ;
    USE SIGNAL ;
    ANTENNADIFFAREA 0.702900 ;
    PORT
      LAYER met2 ;
        RECT 29.530 445.800 29.810 446.080 ;
    END
  END Tile_X0Y0_N1BEG[2]
  PIN Tile_X0Y0_N1BEG[3]
    DIRECTION OUTPUT ;
    USE SIGNAL ;
    ANTENNADIFFAREA 0.702900 ;
    PORT
      LAYER met2 ;
        RECT 30.910 445.800 31.190 446.080 ;
    END
  END Tile_X0Y0_N1BEG[3]
  PIN Tile_X0Y0_N2BEG[0]
    DIRECTION OUTPUT ;
    USE SIGNAL ;
    ANTENNADIFFAREA 0.702900 ;
    PORT
      LAYER met2 ;
        RECT 32.290 445.800 32.570 446.080 ;
    END
  END Tile_X0Y0_N2BEG[0]
  PIN Tile_X0Y0_N2BEG[1]
    DIRECTION OUTPUT ;
    USE SIGNAL ;
    ANTENNADIFFAREA 0.702900 ;
    PORT
      LAYER met2 ;
        RECT 33.670 445.800 33.950 446.080 ;
    END
  END Tile_X0Y0_N2BEG[1]
  PIN Tile_X0Y0_N2BEG[2]
    DIRECTION OUTPUT ;
    USE SIGNAL ;
    ANTENNADIFFAREA 0.702900 ;
    PORT
      LAYER met2 ;
        RECT 35.050 445.800 35.330 446.080 ;
    END
  END Tile_X0Y0_N2BEG[2]
  PIN Tile_X0Y0_N2BEG[3]
    DIRECTION OUTPUT ;
    USE SIGNAL ;
    ANTENNADIFFAREA 0.702900 ;
    PORT
      LAYER met2 ;
        RECT 36.430 445.800 36.710 446.080 ;
    END
  END Tile_X0Y0_N2BEG[3]
  PIN Tile_X0Y0_N2BEG[4]
    DIRECTION OUTPUT ;
    USE SIGNAL ;
    ANTENNADIFFAREA 0.702900 ;
    PORT
      LAYER met2 ;
        RECT 37.810 445.800 38.090 446.080 ;
    END
  END Tile_X0Y0_N2BEG[4]
  PIN Tile_X0Y0_N2BEG[5]
    DIRECTION OUTPUT ;
    USE SIGNAL ;
    ANTENNADIFFAREA 0.702900 ;
    PORT
      LAYER met2 ;
        RECT 39.190 445.800 39.470 446.080 ;
    END
  END Tile_X0Y0_N2BEG[5]
  PIN Tile_X0Y0_N2BEG[6]
    DIRECTION OUTPUT ;
    USE SIGNAL ;
    ANTENNADIFFAREA 0.702900 ;
    PORT
      LAYER met2 ;
        RECT 40.570 445.800 40.850 446.080 ;
    END
  END Tile_X0Y0_N2BEG[6]
  PIN Tile_X0Y0_N2BEG[7]
    DIRECTION OUTPUT ;
    USE SIGNAL ;
    ANTENNADIFFAREA 0.702900 ;
    PORT
      LAYER met2 ;
        RECT 41.950 445.800 42.230 446.080 ;
    END
  END Tile_X0Y0_N2BEG[7]
  PIN Tile_X0Y0_N2BEGb[0]
    DIRECTION OUTPUT ;
    USE SIGNAL ;
    ANTENNADIFFAREA 0.702900 ;
    PORT
      LAYER met2 ;
        RECT 43.330 445.800 43.610 446.080 ;
    END
  END Tile_X0Y0_N2BEGb[0]
  PIN Tile_X0Y0_N2BEGb[1]
    DIRECTION OUTPUT ;
    USE SIGNAL ;
    ANTENNADIFFAREA 0.702900 ;
    PORT
      LAYER met2 ;
        RECT 44.710 445.800 44.990 446.080 ;
    END
  END Tile_X0Y0_N2BEGb[1]
  PIN Tile_X0Y0_N2BEGb[2]
    DIRECTION OUTPUT ;
    USE SIGNAL ;
    ANTENNADIFFAREA 0.702900 ;
    PORT
      LAYER met2 ;
        RECT 46.090 445.800 46.370 446.080 ;
    END
  END Tile_X0Y0_N2BEGb[2]
  PIN Tile_X0Y0_N2BEGb[3]
    DIRECTION OUTPUT ;
    USE SIGNAL ;
    ANTENNADIFFAREA 0.702900 ;
    PORT
      LAYER met2 ;
        RECT 47.470 445.800 47.750 446.080 ;
    END
  END Tile_X0Y0_N2BEGb[3]
  PIN Tile_X0Y0_N2BEGb[4]
    DIRECTION OUTPUT ;
    USE SIGNAL ;
    ANTENNADIFFAREA 0.702900 ;
    PORT
      LAYER met2 ;
        RECT 48.850 445.800 49.130 446.080 ;
    END
  END Tile_X0Y0_N2BEGb[4]
  PIN Tile_X0Y0_N2BEGb[5]
    DIRECTION OUTPUT ;
    USE SIGNAL ;
    ANTENNADIFFAREA 0.702900 ;
    PORT
      LAYER met2 ;
        RECT 50.230 445.800 50.510 446.080 ;
    END
  END Tile_X0Y0_N2BEGb[5]
  PIN Tile_X0Y0_N2BEGb[6]
    DIRECTION OUTPUT ;
    USE SIGNAL ;
    ANTENNADIFFAREA 0.702900 ;
    PORT
      LAYER met2 ;
        RECT 51.610 445.800 51.890 446.080 ;
    END
  END Tile_X0Y0_N2BEGb[6]
  PIN Tile_X0Y0_N2BEGb[7]
    DIRECTION OUTPUT ;
    USE SIGNAL ;
    ANTENNADIFFAREA 0.702900 ;
    PORT
      LAYER met2 ;
        RECT 52.990 445.800 53.270 446.080 ;
    END
  END Tile_X0Y0_N2BEGb[7]
  PIN Tile_X0Y0_N4BEG[0]
    DIRECTION OUTPUT ;
    USE SIGNAL ;
    ANTENNADIFFAREA 0.702900 ;
    PORT
      LAYER met2 ;
        RECT 54.370 445.800 54.650 446.080 ;
    END
  END Tile_X0Y0_N4BEG[0]
  PIN Tile_X0Y0_N4BEG[10]
    DIRECTION OUTPUT ;
    USE SIGNAL ;
    ANTENNADIFFAREA 0.702900 ;
    PORT
      LAYER met2 ;
        RECT 68.170 445.800 68.450 446.080 ;
    END
  END Tile_X0Y0_N4BEG[10]
  PIN Tile_X0Y0_N4BEG[11]
    DIRECTION OUTPUT ;
    USE SIGNAL ;
    ANTENNADIFFAREA 0.702900 ;
    PORT
      LAYER met2 ;
        RECT 69.550 445.800 69.830 446.080 ;
    END
  END Tile_X0Y0_N4BEG[11]
  PIN Tile_X0Y0_N4BEG[12]
    DIRECTION OUTPUT ;
    USE SIGNAL ;
    ANTENNADIFFAREA 0.702900 ;
    PORT
      LAYER met2 ;
        RECT 70.930 445.800 71.210 446.080 ;
    END
  END Tile_X0Y0_N4BEG[12]
  PIN Tile_X0Y0_N4BEG[13]
    DIRECTION OUTPUT ;
    USE SIGNAL ;
    ANTENNADIFFAREA 0.702900 ;
    PORT
      LAYER met2 ;
        RECT 72.310 445.800 72.590 446.080 ;
    END
  END Tile_X0Y0_N4BEG[13]
  PIN Tile_X0Y0_N4BEG[14]
    DIRECTION OUTPUT ;
    USE SIGNAL ;
    ANTENNADIFFAREA 0.702900 ;
    PORT
      LAYER met2 ;
        RECT 73.690 445.800 73.970 446.080 ;
    END
  END Tile_X0Y0_N4BEG[14]
  PIN Tile_X0Y0_N4BEG[15]
    DIRECTION OUTPUT ;
    USE SIGNAL ;
    ANTENNADIFFAREA 0.702900 ;
    PORT
      LAYER met2 ;
        RECT 75.070 445.800 75.350 446.080 ;
    END
  END Tile_X0Y0_N4BEG[15]
  PIN Tile_X0Y0_N4BEG[1]
    DIRECTION OUTPUT ;
    USE SIGNAL ;
    ANTENNADIFFAREA 0.702900 ;
    PORT
      LAYER met2 ;
        RECT 55.750 445.800 56.030 446.080 ;
    END
  END Tile_X0Y0_N4BEG[1]
  PIN Tile_X0Y0_N4BEG[2]
    DIRECTION OUTPUT ;
    USE SIGNAL ;
    ANTENNADIFFAREA 0.702900 ;
    PORT
      LAYER met2 ;
        RECT 57.130 445.800 57.410 446.080 ;
    END
  END Tile_X0Y0_N4BEG[2]
  PIN Tile_X0Y0_N4BEG[3]
    DIRECTION OUTPUT ;
    USE SIGNAL ;
    ANTENNADIFFAREA 0.702900 ;
    PORT
      LAYER met2 ;
        RECT 58.510 445.800 58.790 446.080 ;
    END
  END Tile_X0Y0_N4BEG[3]
  PIN Tile_X0Y0_N4BEG[4]
    DIRECTION OUTPUT ;
    USE SIGNAL ;
    ANTENNADIFFAREA 0.702900 ;
    PORT
      LAYER met2 ;
        RECT 59.890 445.800 60.170 446.080 ;
    END
  END Tile_X0Y0_N4BEG[4]
  PIN Tile_X0Y0_N4BEG[5]
    DIRECTION OUTPUT ;
    USE SIGNAL ;
    ANTENNADIFFAREA 0.702900 ;
    PORT
      LAYER met2 ;
        RECT 61.270 445.800 61.550 446.080 ;
    END
  END Tile_X0Y0_N4BEG[5]
  PIN Tile_X0Y0_N4BEG[6]
    DIRECTION OUTPUT ;
    USE SIGNAL ;
    ANTENNADIFFAREA 0.702900 ;
    PORT
      LAYER met2 ;
        RECT 62.650 445.800 62.930 446.080 ;
    END
  END Tile_X0Y0_N4BEG[6]
  PIN Tile_X0Y0_N4BEG[7]
    DIRECTION OUTPUT ;
    USE SIGNAL ;
    ANTENNADIFFAREA 0.702900 ;
    PORT
      LAYER met2 ;
        RECT 64.030 445.800 64.310 446.080 ;
    END
  END Tile_X0Y0_N4BEG[7]
  PIN Tile_X0Y0_N4BEG[8]
    DIRECTION OUTPUT ;
    USE SIGNAL ;
    ANTENNADIFFAREA 0.702900 ;
    PORT
      LAYER met2 ;
        RECT 65.410 445.800 65.690 446.080 ;
    END
  END Tile_X0Y0_N4BEG[8]
  PIN Tile_X0Y0_N4BEG[9]
    DIRECTION OUTPUT ;
    USE SIGNAL ;
    ANTENNADIFFAREA 0.702900 ;
    PORT
      LAYER met2 ;
        RECT 66.790 445.800 67.070 446.080 ;
    END
  END Tile_X0Y0_N4BEG[9]
  PIN Tile_X0Y0_NN4BEG[0]
    DIRECTION OUTPUT ;
    USE SIGNAL ;
    ANTENNADIFFAREA 0.702900 ;
    PORT
      LAYER met2 ;
        RECT 76.450 445.800 76.730 446.080 ;
    END
  END Tile_X0Y0_NN4BEG[0]
  PIN Tile_X0Y0_NN4BEG[10]
    DIRECTION OUTPUT ;
    USE SIGNAL ;
    ANTENNADIFFAREA 0.702900 ;
    PORT
      LAYER met2 ;
        RECT 90.250 445.800 90.530 446.080 ;
    END
  END Tile_X0Y0_NN4BEG[10]
  PIN Tile_X0Y0_NN4BEG[11]
    DIRECTION OUTPUT ;
    USE SIGNAL ;
    ANTENNADIFFAREA 0.702900 ;
    PORT
      LAYER met2 ;
        RECT 91.630 445.800 91.910 446.080 ;
    END
  END Tile_X0Y0_NN4BEG[11]
  PIN Tile_X0Y0_NN4BEG[12]
    DIRECTION OUTPUT ;
    USE SIGNAL ;
    ANTENNADIFFAREA 0.702900 ;
    PORT
      LAYER met2 ;
        RECT 93.010 445.800 93.290 446.080 ;
    END
  END Tile_X0Y0_NN4BEG[12]
  PIN Tile_X0Y0_NN4BEG[13]
    DIRECTION OUTPUT ;
    USE SIGNAL ;
    ANTENNADIFFAREA 0.702900 ;
    PORT
      LAYER met2 ;
        RECT 94.390 445.800 94.670 446.080 ;
    END
  END Tile_X0Y0_NN4BEG[13]
  PIN Tile_X0Y0_NN4BEG[14]
    DIRECTION OUTPUT ;
    USE SIGNAL ;
    ANTENNADIFFAREA 0.702900 ;
    PORT
      LAYER met2 ;
        RECT 95.770 445.800 96.050 446.080 ;
    END
  END Tile_X0Y0_NN4BEG[14]
  PIN Tile_X0Y0_NN4BEG[15]
    DIRECTION OUTPUT ;
    USE SIGNAL ;
    ANTENNADIFFAREA 0.702900 ;
    PORT
      LAYER met2 ;
        RECT 97.150 445.800 97.430 446.080 ;
    END
  END Tile_X0Y0_NN4BEG[15]
  PIN Tile_X0Y0_NN4BEG[1]
    DIRECTION OUTPUT ;
    USE SIGNAL ;
    ANTENNADIFFAREA 0.702900 ;
    PORT
      LAYER met2 ;
        RECT 77.830 445.800 78.110 446.080 ;
    END
  END Tile_X0Y0_NN4BEG[1]
  PIN Tile_X0Y0_NN4BEG[2]
    DIRECTION OUTPUT ;
    USE SIGNAL ;
    ANTENNADIFFAREA 0.702900 ;
    PORT
      LAYER met2 ;
        RECT 79.210 445.800 79.490 446.080 ;
    END
  END Tile_X0Y0_NN4BEG[2]
  PIN Tile_X0Y0_NN4BEG[3]
    DIRECTION OUTPUT ;
    USE SIGNAL ;
    ANTENNADIFFAREA 0.702900 ;
    PORT
      LAYER met2 ;
        RECT 80.590 445.800 80.870 446.080 ;
    END
  END Tile_X0Y0_NN4BEG[3]
  PIN Tile_X0Y0_NN4BEG[4]
    DIRECTION OUTPUT ;
    USE SIGNAL ;
    ANTENNADIFFAREA 0.702900 ;
    PORT
      LAYER met2 ;
        RECT 81.970 445.800 82.250 446.080 ;
    END
  END Tile_X0Y0_NN4BEG[4]
  PIN Tile_X0Y0_NN4BEG[5]
    DIRECTION OUTPUT ;
    USE SIGNAL ;
    ANTENNADIFFAREA 0.702900 ;
    PORT
      LAYER met2 ;
        RECT 83.350 445.800 83.630 446.080 ;
    END
  END Tile_X0Y0_NN4BEG[5]
  PIN Tile_X0Y0_NN4BEG[6]
    DIRECTION OUTPUT ;
    USE SIGNAL ;
    ANTENNADIFFAREA 0.702900 ;
    PORT
      LAYER met2 ;
        RECT 84.730 445.800 85.010 446.080 ;
    END
  END Tile_X0Y0_NN4BEG[6]
  PIN Tile_X0Y0_NN4BEG[7]
    DIRECTION OUTPUT ;
    USE SIGNAL ;
    ANTENNADIFFAREA 0.702900 ;
    PORT
      LAYER met2 ;
        RECT 86.110 445.800 86.390 446.080 ;
    END
  END Tile_X0Y0_NN4BEG[7]
  PIN Tile_X0Y0_NN4BEG[8]
    DIRECTION OUTPUT ;
    USE SIGNAL ;
    ANTENNADIFFAREA 0.702900 ;
    PORT
      LAYER met2 ;
        RECT 87.490 445.800 87.770 446.080 ;
    END
  END Tile_X0Y0_NN4BEG[8]
  PIN Tile_X0Y0_NN4BEG[9]
    DIRECTION OUTPUT ;
    USE SIGNAL ;
    ANTENNADIFFAREA 0.702900 ;
    PORT
      LAYER met2 ;
        RECT 88.870 445.800 89.150 446.080 ;
    END
  END Tile_X0Y0_NN4BEG[9]
  PIN Tile_X0Y0_N_GBUF_BEG[0]
    DIRECTION OUTPUT ;
    USE SIGNAL ;
    ANTENNADIFFAREA 0.702900 ;
    PORT
      LAYER met2 ;
        RECT 21.250 445.800 21.530 446.080 ;
    END
  END Tile_X0Y0_N_GBUF_BEG[0]
  PIN Tile_X0Y0_N_GBUF_BEG[1]
    DIRECTION OUTPUT ;
    USE SIGNAL ;
    ANTENNADIFFAREA 0.702900 ;
    PORT
      LAYER met2 ;
        RECT 22.630 445.800 22.910 446.080 ;
    END
  END Tile_X0Y0_N_GBUF_BEG[1]
  PIN Tile_X0Y0_N_GBUF_BEG[2]
    DIRECTION OUTPUT ;
    USE SIGNAL ;
    ANTENNADIFFAREA 0.702900 ;
    PORT
      LAYER met2 ;
        RECT 24.010 445.800 24.290 446.080 ;
    END
  END Tile_X0Y0_N_GBUF_BEG[2]
  PIN Tile_X0Y0_N_GBUF_BEG[3]
    DIRECTION OUTPUT ;
    USE SIGNAL ;
    ANTENNADIFFAREA 0.702900 ;
    PORT
      LAYER met2 ;
        RECT 25.390 445.800 25.670 446.080 ;
    END
  END Tile_X0Y0_N_GBUF_BEG[3]
  PIN Tile_X0Y0_S1END[0]
    DIRECTION INPUT ;
    USE SIGNAL ;
    ANTENNAGATEAREA 1.173000 ;
    PORT
      LAYER met2 ;
        RECT 99.910 445.800 100.190 446.080 ;
    END
  END Tile_X0Y0_S1END[0]
  PIN Tile_X0Y0_S1END[1]
    DIRECTION INPUT ;
    USE SIGNAL ;
    ANTENNAGATEAREA 1.350000 ;
    PORT
      LAYER met2 ;
        RECT 101.290 445.800 101.570 446.080 ;
    END
  END Tile_X0Y0_S1END[1]
  PIN Tile_X0Y0_S1END[2]
    DIRECTION INPUT ;
    USE SIGNAL ;
    ANTENNAGATEAREA 1.206000 ;
    PORT
      LAYER met2 ;
        RECT 102.670 445.800 102.950 446.080 ;
    END
  END Tile_X0Y0_S1END[2]
  PIN Tile_X0Y0_S1END[3]
    DIRECTION INPUT ;
    USE SIGNAL ;
    ANTENNAGATEAREA 1.239000 ;
    PORT
      LAYER met2 ;
        RECT 104.050 445.800 104.330 446.080 ;
    END
  END Tile_X0Y0_S1END[3]
  PIN Tile_X0Y0_S2END[0]
    DIRECTION INPUT ;
    USE SIGNAL ;
    ANTENNAGATEAREA 0.888000 ;
    PORT
      LAYER met2 ;
        RECT 116.470 445.800 116.750 446.080 ;
    END
  END Tile_X0Y0_S2END[0]
  PIN Tile_X0Y0_S2END[1]
    DIRECTION INPUT ;
    USE SIGNAL ;
    ANTENNAGATEAREA 2.258100 ;
    ANTENNADIFFAREA 1.304100 ;
    PORT
      LAYER met2 ;
        RECT 117.850 445.800 118.130 446.080 ;
    END
  END Tile_X0Y0_S2END[1]
  PIN Tile_X0Y0_S2END[2]
    DIRECTION INPUT ;
    USE SIGNAL ;
    ANTENNAGATEAREA 1.322700 ;
    ANTENNADIFFAREA 0.434700 ;
    PORT
      LAYER met2 ;
        RECT 119.230 445.800 119.510 446.080 ;
    END
  END Tile_X0Y0_S2END[2]
  PIN Tile_X0Y0_S2END[3]
    DIRECTION INPUT ;
    USE SIGNAL ;
    ANTENNAGATEAREA 0.888000 ;
    PORT
      LAYER met2 ;
        RECT 120.610 445.800 120.890 446.080 ;
    END
  END Tile_X0Y0_S2END[3]
  PIN Tile_X0Y0_S2END[4]
    DIRECTION INPUT ;
    USE SIGNAL ;
    ANTENNAGATEAREA 0.795000 ;
    PORT
      LAYER met2 ;
        RECT 121.990 445.800 122.270 446.080 ;
    END
  END Tile_X0Y0_S2END[4]
  PIN Tile_X0Y0_S2END[5]
    DIRECTION INPUT ;
    USE SIGNAL ;
    ANTENNAGATEAREA 0.696000 ;
    PORT
      LAYER met2 ;
        RECT 123.370 445.800 123.650 446.080 ;
    END
  END Tile_X0Y0_S2END[5]
  PIN Tile_X0Y0_S2END[6]
    DIRECTION INPUT ;
    USE SIGNAL ;
    ANTENNAGATEAREA 0.795000 ;
    PORT
      LAYER met2 ;
        RECT 124.750 445.800 125.030 446.080 ;
    END
  END Tile_X0Y0_S2END[6]
  PIN Tile_X0Y0_S2END[7]
    DIRECTION INPUT ;
    USE SIGNAL ;
    ANTENNAGATEAREA 0.954000 ;
    PORT
      LAYER met2 ;
        RECT 126.130 445.800 126.410 446.080 ;
    END
  END Tile_X0Y0_S2END[7]
  PIN Tile_X0Y0_S2MID[0]
    DIRECTION INPUT ;
    USE SIGNAL ;
    ANTENNAGATEAREA 2.219400 ;
    ANTENNADIFFAREA 0.869400 ;
    PORT
      LAYER met2 ;
        RECT 105.430 445.800 105.710 446.080 ;
    END
  END Tile_X0Y0_S2MID[0]
  PIN Tile_X0Y0_S2MID[1]
    DIRECTION INPUT ;
    USE SIGNAL ;
    ANTENNAGATEAREA 1.458000 ;
    PORT
      LAYER met2 ;
        RECT 106.810 445.800 107.090 446.080 ;
    END
  END Tile_X0Y0_S2MID[1]
  PIN Tile_X0Y0_S2MID[2]
    DIRECTION INPUT ;
    USE SIGNAL ;
    ANTENNAGATEAREA 2.388900 ;
    ANTENNADIFFAREA 0.869400 ;
    PORT
      LAYER met2 ;
        RECT 108.190 445.800 108.470 446.080 ;
    END
  END Tile_X0Y0_S2MID[2]
  PIN Tile_X0Y0_S2MID[3]
    DIRECTION INPUT ;
    USE SIGNAL ;
    ANTENNAGATEAREA 2.894100 ;
    ANTENNADIFFAREA 1.304100 ;
    PORT
      LAYER met2 ;
        RECT 109.570 445.800 109.850 446.080 ;
    END
  END Tile_X0Y0_S2MID[3]
  PIN Tile_X0Y0_S2MID[4]
    DIRECTION INPUT ;
    USE SIGNAL ;
    ANTENNAGATEAREA 1.575000 ;
    PORT
      LAYER met2 ;
        RECT 110.950 445.800 111.230 446.080 ;
    END
  END Tile_X0Y0_S2MID[4]
  PIN Tile_X0Y0_S2MID[5]
    DIRECTION INPUT ;
    USE SIGNAL ;
    ANTENNAGATEAREA 1.317000 ;
    PORT
      LAYER met2 ;
        RECT 112.330 445.800 112.610 446.080 ;
    END
  END Tile_X0Y0_S2MID[5]
  PIN Tile_X0Y0_S2MID[6]
    DIRECTION INPUT ;
    USE SIGNAL ;
    ANTENNAGATEAREA 3.238500 ;
    ANTENNADIFFAREA 2.173500 ;
    PORT
      LAYER met2 ;
        RECT 113.710 445.800 113.990 446.080 ;
    END
  END Tile_X0Y0_S2MID[6]
  PIN Tile_X0Y0_S2MID[7]
    DIRECTION INPUT ;
    USE SIGNAL ;
    ANTENNAGATEAREA 2.036700 ;
    ANTENNADIFFAREA 0.434700 ;
    PORT
      LAYER met2 ;
        RECT 115.090 445.800 115.370 446.080 ;
    END
  END Tile_X0Y0_S2MID[7]
  PIN Tile_X0Y0_S4END[0]
    DIRECTION INPUT ;
    USE SIGNAL ;
    ANTENNAGATEAREA 0.795000 ;
    PORT
      LAYER met2 ;
        RECT 127.510 445.800 127.790 446.080 ;
    END
  END Tile_X0Y0_S4END[0]
  PIN Tile_X0Y0_S4END[10]
    DIRECTION INPUT ;
    USE SIGNAL ;
    ANTENNAGATEAREA 0.159000 ;
    PORT
      LAYER met2 ;
        RECT 141.310 445.800 141.590 446.080 ;
    END
  END Tile_X0Y0_S4END[10]
  PIN Tile_X0Y0_S4END[11]
    DIRECTION INPUT ;
    USE SIGNAL ;
    ANTENNAGATEAREA 0.159000 ;
    PORT
      LAYER met2 ;
        RECT 142.690 445.800 142.970 446.080 ;
    END
  END Tile_X0Y0_S4END[11]
  PIN Tile_X0Y0_S4END[12]
    DIRECTION INPUT ;
    USE SIGNAL ;
    ANTENNAGATEAREA 0.159000 ;
    PORT
      LAYER met2 ;
        RECT 144.070 445.800 144.350 446.080 ;
    END
  END Tile_X0Y0_S4END[12]
  PIN Tile_X0Y0_S4END[13]
    DIRECTION INPUT ;
    USE SIGNAL ;
    ANTENNAGATEAREA 0.159000 ;
    PORT
      LAYER met2 ;
        RECT 145.450 445.800 145.730 446.080 ;
    END
  END Tile_X0Y0_S4END[13]
  PIN Tile_X0Y0_S4END[14]
    DIRECTION INPUT ;
    USE SIGNAL ;
    ANTENNAGATEAREA 0.159000 ;
    PORT
      LAYER met2 ;
        RECT 146.830 445.800 147.110 446.080 ;
    END
  END Tile_X0Y0_S4END[14]
  PIN Tile_X0Y0_S4END[15]
    DIRECTION INPUT ;
    USE SIGNAL ;
    ANTENNAGATEAREA 0.159000 ;
    PORT
      LAYER met2 ;
        RECT 148.210 445.800 148.490 446.080 ;
    END
  END Tile_X0Y0_S4END[15]
  PIN Tile_X0Y0_S4END[1]
    DIRECTION INPUT ;
    USE SIGNAL ;
    ANTENNAGATEAREA 1.196700 ;
    ANTENNADIFFAREA 0.434700 ;
    PORT
      LAYER met2 ;
        RECT 128.890 445.800 129.170 446.080 ;
    END
  END Tile_X0Y0_S4END[1]
  PIN Tile_X0Y0_S4END[2]
    DIRECTION INPUT ;
    USE SIGNAL ;
    ANTENNAGATEAREA 2.066100 ;
    ANTENNADIFFAREA 1.304100 ;
    PORT
      LAYER met2 ;
        RECT 130.270 445.800 130.550 446.080 ;
    END
  END Tile_X0Y0_S4END[2]
  PIN Tile_X0Y0_S4END[3]
    DIRECTION INPUT ;
    USE SIGNAL ;
    ANTENNAGATEAREA 1.598400 ;
    ANTENNADIFFAREA 0.869400 ;
    PORT
      LAYER met2 ;
        RECT 131.650 445.800 131.930 446.080 ;
    END
  END Tile_X0Y0_S4END[3]
  PIN Tile_X0Y0_S4END[4]
    DIRECTION INPUT ;
    USE SIGNAL ;
    ANTENNAGATEAREA 2.935500 ;
    ANTENNADIFFAREA 2.173500 ;
    PORT
      LAYER met2 ;
        RECT 133.030 445.800 133.310 446.080 ;
    END
  END Tile_X0Y0_S4END[4]
  PIN Tile_X0Y0_S4END[5]
    DIRECTION INPUT ;
    USE SIGNAL ;
    ANTENNAGATEAREA 2.935500 ;
    ANTENNADIFFAREA 2.173500 ;
    PORT
      LAYER met2 ;
        RECT 134.410 445.800 134.690 446.080 ;
    END
  END Tile_X0Y0_S4END[5]
  PIN Tile_X0Y0_S4END[6]
    DIRECTION INPUT ;
    USE SIGNAL ;
    ANTENNAGATEAREA 1.131000 ;
    PORT
      LAYER met2 ;
        RECT 135.790 445.800 136.070 446.080 ;
    END
  END Tile_X0Y0_S4END[6]
  PIN Tile_X0Y0_S4END[7]
    DIRECTION INPUT ;
    USE SIGNAL ;
    ANTENNAGATEAREA 2.710800 ;
    ANTENNADIFFAREA 1.738800 ;
    PORT
      LAYER met2 ;
        RECT 137.170 445.800 137.450 446.080 ;
    END
  END Tile_X0Y0_S4END[7]
  PIN Tile_X0Y0_S4END[8]
    DIRECTION INPUT ;
    USE SIGNAL ;
    ANTENNAGATEAREA 0.159000 ;
    PORT
      LAYER met2 ;
        RECT 138.550 445.800 138.830 446.080 ;
    END
  END Tile_X0Y0_S4END[8]
  PIN Tile_X0Y0_S4END[9]
    DIRECTION INPUT ;
    USE SIGNAL ;
    ANTENNAGATEAREA 0.159000 ;
    PORT
      LAYER met2 ;
        RECT 139.930 445.800 140.210 446.080 ;
    END
  END Tile_X0Y0_S4END[9]
  PIN Tile_X0Y0_SS4END[0]
    DIRECTION INPUT ;
    USE SIGNAL ;
    ANTENNAGATEAREA 1.313400 ;
    ANTENNADIFFAREA 0.869400 ;
    PORT
      LAYER met2 ;
        RECT 149.590 445.800 149.870 446.080 ;
    END
  END Tile_X0Y0_SS4END[0]
  PIN Tile_X0Y0_SS4END[10]
    DIRECTION INPUT ;
    USE SIGNAL ;
    ANTENNAGATEAREA 0.159000 ;
    PORT
      LAYER met2 ;
        RECT 163.390 445.800 163.670 446.080 ;
    END
  END Tile_X0Y0_SS4END[10]
  PIN Tile_X0Y0_SS4END[11]
    DIRECTION INPUT ;
    USE SIGNAL ;
    ANTENNAGATEAREA 0.159000 ;
    PORT
      LAYER met2 ;
        RECT 164.770 445.800 165.050 446.080 ;
    END
  END Tile_X0Y0_SS4END[11]
  PIN Tile_X0Y0_SS4END[12]
    DIRECTION INPUT ;
    USE SIGNAL ;
    ANTENNAGATEAREA 0.159000 ;
    PORT
      LAYER met2 ;
        RECT 166.150 445.800 166.430 446.080 ;
    END
  END Tile_X0Y0_SS4END[12]
  PIN Tile_X0Y0_SS4END[13]
    DIRECTION INPUT ;
    USE SIGNAL ;
    ANTENNAGATEAREA 0.159000 ;
    PORT
      LAYER met2 ;
        RECT 167.530 445.800 167.810 446.080 ;
    END
  END Tile_X0Y0_SS4END[13]
  PIN Tile_X0Y0_SS4END[14]
    DIRECTION INPUT ;
    USE SIGNAL ;
    ANTENNAGATEAREA 0.159000 ;
    PORT
      LAYER met2 ;
        RECT 168.910 445.800 169.190 446.080 ;
    END
  END Tile_X0Y0_SS4END[14]
  PIN Tile_X0Y0_SS4END[15]
    DIRECTION INPUT ;
    USE SIGNAL ;
    ANTENNAGATEAREA 0.159000 ;
    PORT
      LAYER met2 ;
        RECT 170.290 445.800 170.570 446.080 ;
    END
  END Tile_X0Y0_SS4END[15]
  PIN Tile_X0Y0_SS4END[1]
    DIRECTION INPUT ;
    USE SIGNAL ;
    ANTENNAGATEAREA 0.477000 ;
    PORT
      LAYER met2 ;
        RECT 150.970 445.800 151.250 446.080 ;
    END
  END Tile_X0Y0_SS4END[1]
  PIN Tile_X0Y0_SS4END[2]
    DIRECTION INPUT ;
    USE SIGNAL ;
    ANTENNAGATEAREA 0.444000 ;
    PORT
      LAYER met2 ;
        RECT 152.350 445.800 152.630 446.080 ;
    END
  END Tile_X0Y0_SS4END[2]
  PIN Tile_X0Y0_SS4END[3]
    DIRECTION INPUT ;
    USE SIGNAL ;
    ANTENNAGATEAREA 0.318000 ;
    PORT
      LAYER met2 ;
        RECT 153.730 445.800 154.010 446.080 ;
    END
  END Tile_X0Y0_SS4END[3]
  PIN Tile_X0Y0_SS4END[4]
    DIRECTION INPUT ;
    USE SIGNAL ;
    ANTENNAGATEAREA 1.781100 ;
    ANTENNADIFFAREA 1.304100 ;
    PORT
      LAYER met2 ;
        RECT 155.110 445.800 155.390 446.080 ;
    END
  END Tile_X0Y0_SS4END[4]
  PIN Tile_X0Y0_SS4END[5]
    DIRECTION INPUT ;
    USE SIGNAL ;
    ANTENNAGATEAREA 1.781100 ;
    ANTENNADIFFAREA 1.304100 ;
    PORT
      LAYER met2 ;
        RECT 156.490 445.800 156.770 446.080 ;
    END
  END Tile_X0Y0_SS4END[5]
  PIN Tile_X0Y0_SS4END[6]
    DIRECTION INPUT ;
    USE SIGNAL ;
    ANTENNAGATEAREA 1.781100 ;
    ANTENNADIFFAREA 1.304100 ;
    PORT
      LAYER met2 ;
        RECT 157.870 445.800 158.150 446.080 ;
    END
  END Tile_X0Y0_SS4END[6]
  PIN Tile_X0Y0_SS4END[7]
    DIRECTION INPUT ;
    USE SIGNAL ;
    ANTENNAGATEAREA 1.187400 ;
    ANTENNADIFFAREA 0.869400 ;
    PORT
      LAYER met2 ;
        RECT 159.250 445.800 159.530 446.080 ;
    END
  END Tile_X0Y0_SS4END[7]
  PIN Tile_X0Y0_SS4END[8]
    DIRECTION INPUT ;
    USE SIGNAL ;
    ANTENNAGATEAREA 0.159000 ;
    PORT
      LAYER met2 ;
        RECT 160.630 445.800 160.910 446.080 ;
    END
  END Tile_X0Y0_SS4END[8]
  PIN Tile_X0Y0_SS4END[9]
    DIRECTION INPUT ;
    USE SIGNAL ;
    ANTENNAGATEAREA 0.159000 ;
    PORT
      LAYER met2 ;
        RECT 162.010 445.800 162.290 446.080 ;
    END
  END Tile_X0Y0_SS4END[9]
  PIN Tile_X0Y0_W1BEG[0]
    DIRECTION OUTPUT ;
    USE SIGNAL ;
    ANTENNADIFFAREA 0.702900 ;
    PORT
      LAYER met3 ;
        RECT 0.000 247.560 0.600 248.160 ;
    END
  END Tile_X0Y0_W1BEG[0]
  PIN Tile_X0Y0_W1BEG[1]
    DIRECTION OUTPUT ;
    USE SIGNAL ;
    ANTENNADIFFAREA 0.702900 ;
    PORT
      LAYER met3 ;
        RECT 0.000 248.920 0.600 249.520 ;
    END
  END Tile_X0Y0_W1BEG[1]
  PIN Tile_X0Y0_W1BEG[2]
    DIRECTION OUTPUT ;
    USE SIGNAL ;
    ANTENNADIFFAREA 0.702900 ;
    PORT
      LAYER met3 ;
        RECT 0.000 250.280 0.600 250.880 ;
    END
  END Tile_X0Y0_W1BEG[2]
  PIN Tile_X0Y0_W1BEG[3]
    DIRECTION OUTPUT ;
    USE SIGNAL ;
    ANTENNADIFFAREA 0.702900 ;
    PORT
      LAYER met3 ;
        RECT 0.000 251.640 0.600 252.240 ;
    END
  END Tile_X0Y0_W1BEG[3]
  PIN Tile_X0Y0_W1END[0]
    DIRECTION INPUT ;
    USE SIGNAL ;
    ANTENNAGATEAREA 1.206000 ;
    PORT
      LAYER met3 ;
        RECT 219.280 247.560 219.880 248.160 ;
    END
  END Tile_X0Y0_W1END[0]
  PIN Tile_X0Y0_W1END[1]
    DIRECTION INPUT ;
    USE SIGNAL ;
    ANTENNAGATEAREA 1.532700 ;
    ANTENNADIFFAREA 0.434700 ;
    PORT
      LAYER met3 ;
        RECT 219.280 248.920 219.880 249.520 ;
    END
  END Tile_X0Y0_W1END[1]
  PIN Tile_X0Y0_W1END[2]
    DIRECTION INPUT ;
    USE SIGNAL ;
    ANTENNAGATEAREA 2.585400 ;
    ANTENNADIFFAREA 0.869400 ;
    PORT
      LAYER met3 ;
        RECT 219.280 250.280 219.880 250.880 ;
    END
  END Tile_X0Y0_W1END[2]
  PIN Tile_X0Y0_W1END[3]
    DIRECTION INPUT ;
    USE SIGNAL ;
    ANTENNAGATEAREA 2.565000 ;
    PORT
      LAYER met3 ;
        RECT 219.280 251.640 219.880 252.240 ;
    END
  END Tile_X0Y0_W1END[3]
  PIN Tile_X0Y0_W2BEG[0]
    DIRECTION OUTPUT ;
    USE SIGNAL ;
    ANTENNADIFFAREA 0.702900 ;
    PORT
      LAYER met3 ;
        RECT 0.000 253.000 0.600 253.600 ;
    END
  END Tile_X0Y0_W2BEG[0]
  PIN Tile_X0Y0_W2BEG[1]
    DIRECTION OUTPUT ;
    USE SIGNAL ;
    ANTENNADIFFAREA 0.702900 ;
    PORT
      LAYER met3 ;
        RECT 0.000 254.360 0.600 254.960 ;
    END
  END Tile_X0Y0_W2BEG[1]
  PIN Tile_X0Y0_W2BEG[2]
    DIRECTION OUTPUT ;
    USE SIGNAL ;
    ANTENNADIFFAREA 0.702900 ;
    PORT
      LAYER met3 ;
        RECT 0.000 255.720 0.600 256.320 ;
    END
  END Tile_X0Y0_W2BEG[2]
  PIN Tile_X0Y0_W2BEG[3]
    DIRECTION OUTPUT ;
    USE SIGNAL ;
    ANTENNADIFFAREA 0.702900 ;
    PORT
      LAYER met3 ;
        RECT 0.000 257.080 0.600 257.680 ;
    END
  END Tile_X0Y0_W2BEG[3]
  PIN Tile_X0Y0_W2BEG[4]
    DIRECTION OUTPUT ;
    USE SIGNAL ;
    ANTENNADIFFAREA 0.702900 ;
    PORT
      LAYER met3 ;
        RECT 0.000 258.440 0.600 259.040 ;
    END
  END Tile_X0Y0_W2BEG[4]
  PIN Tile_X0Y0_W2BEG[5]
    DIRECTION OUTPUT ;
    USE SIGNAL ;
    ANTENNADIFFAREA 0.702900 ;
    PORT
      LAYER met3 ;
        RECT 0.000 259.800 0.600 260.400 ;
    END
  END Tile_X0Y0_W2BEG[5]
  PIN Tile_X0Y0_W2BEG[6]
    DIRECTION OUTPUT ;
    USE SIGNAL ;
    ANTENNADIFFAREA 0.702900 ;
    PORT
      LAYER met3 ;
        RECT 0.000 261.160 0.600 261.760 ;
    END
  END Tile_X0Y0_W2BEG[6]
  PIN Tile_X0Y0_W2BEG[7]
    DIRECTION OUTPUT ;
    USE SIGNAL ;
    ANTENNADIFFAREA 0.702900 ;
    PORT
      LAYER met3 ;
        RECT 0.000 262.520 0.600 263.120 ;
    END
  END Tile_X0Y0_W2BEG[7]
  PIN Tile_X0Y0_W2BEGb[0]
    DIRECTION OUTPUT ;
    USE SIGNAL ;
    ANTENNADIFFAREA 0.702900 ;
    PORT
      LAYER met3 ;
        RECT 0.000 263.880 0.600 264.480 ;
    END
  END Tile_X0Y0_W2BEGb[0]
  PIN Tile_X0Y0_W2BEGb[1]
    DIRECTION OUTPUT ;
    USE SIGNAL ;
    ANTENNADIFFAREA 0.702900 ;
    PORT
      LAYER met3 ;
        RECT 0.000 265.240 0.600 265.840 ;
    END
  END Tile_X0Y0_W2BEGb[1]
  PIN Tile_X0Y0_W2BEGb[2]
    DIRECTION OUTPUT ;
    USE SIGNAL ;
    ANTENNADIFFAREA 0.702900 ;
    PORT
      LAYER met3 ;
        RECT 0.000 266.600 0.600 267.200 ;
    END
  END Tile_X0Y0_W2BEGb[2]
  PIN Tile_X0Y0_W2BEGb[3]
    DIRECTION OUTPUT ;
    USE SIGNAL ;
    ANTENNADIFFAREA 0.702900 ;
    PORT
      LAYER met3 ;
        RECT 0.000 267.960 0.600 268.560 ;
    END
  END Tile_X0Y0_W2BEGb[3]
  PIN Tile_X0Y0_W2BEGb[4]
    DIRECTION OUTPUT ;
    USE SIGNAL ;
    ANTENNADIFFAREA 0.702900 ;
    PORT
      LAYER met3 ;
        RECT 0.000 269.320 0.600 269.920 ;
    END
  END Tile_X0Y0_W2BEGb[4]
  PIN Tile_X0Y0_W2BEGb[5]
    DIRECTION OUTPUT ;
    USE SIGNAL ;
    ANTENNADIFFAREA 0.702900 ;
    PORT
      LAYER met3 ;
        RECT 0.000 270.680 0.600 271.280 ;
    END
  END Tile_X0Y0_W2BEGb[5]
  PIN Tile_X0Y0_W2BEGb[6]
    DIRECTION OUTPUT ;
    USE SIGNAL ;
    ANTENNADIFFAREA 0.702900 ;
    PORT
      LAYER met3 ;
        RECT 0.000 272.040 0.600 272.640 ;
    END
  END Tile_X0Y0_W2BEGb[6]
  PIN Tile_X0Y0_W2BEGb[7]
    DIRECTION OUTPUT ;
    USE SIGNAL ;
    ANTENNADIFFAREA 0.702900 ;
    PORT
      LAYER met3 ;
        RECT 0.000 273.400 0.600 274.000 ;
    END
  END Tile_X0Y0_W2BEGb[7]
  PIN Tile_X0Y0_W2END[0]
    DIRECTION INPUT ;
    USE SIGNAL ;
    ANTENNAGATEAREA 1.869600 ;
    ANTENNADIFFAREA 1.304100 ;
    PORT
      LAYER met3 ;
        RECT 219.280 263.880 219.880 264.480 ;
    END
  END Tile_X0Y0_W2END[0]
  PIN Tile_X0Y0_W2END[1]
    DIRECTION INPUT ;
    USE SIGNAL ;
    ANTENNAGATEAREA 2.258100 ;
    ANTENNADIFFAREA 1.304100 ;
    PORT
      LAYER met3 ;
        RECT 219.280 265.240 219.880 265.840 ;
    END
  END Tile_X0Y0_W2END[1]
  PIN Tile_X0Y0_W2END[2]
    DIRECTION INPUT ;
    USE SIGNAL ;
    ANTENNAGATEAREA 1.224000 ;
    PORT
      LAYER met3 ;
        RECT 219.280 266.600 219.880 267.200 ;
    END
  END Tile_X0Y0_W2END[2]
  PIN Tile_X0Y0_W2END[3]
    DIRECTION INPUT ;
    USE SIGNAL ;
    ANTENNAGATEAREA 2.687100 ;
    ANTENNADIFFAREA 1.304100 ;
    PORT
      LAYER met3 ;
        RECT 219.280 267.960 219.880 268.560 ;
    END
  END Tile_X0Y0_W2END[3]
  PIN Tile_X0Y0_W2END[4]
    DIRECTION INPUT ;
    USE SIGNAL ;
    ANTENNAGATEAREA 2.141400 ;
    ANTENNADIFFAREA 0.869400 ;
    PORT
      LAYER met3 ;
        RECT 219.280 269.320 219.880 269.920 ;
    END
  END Tile_X0Y0_W2END[4]
  PIN Tile_X0Y0_W2END[5]
    DIRECTION INPUT ;
    USE SIGNAL ;
    ANTENNAGATEAREA 0.318000 ;
    PORT
      LAYER met3 ;
        RECT 219.280 270.680 219.880 271.280 ;
    END
  END Tile_X0Y0_W2END[5]
  PIN Tile_X0Y0_W2END[6]
    DIRECTION INPUT ;
    USE SIGNAL ;
    ANTENNAGATEAREA 1.187400 ;
    ANTENNADIFFAREA 0.869400 ;
    PORT
      LAYER met3 ;
        RECT 219.280 272.040 219.880 272.640 ;
    END
  END Tile_X0Y0_W2END[6]
  PIN Tile_X0Y0_W2END[7]
    DIRECTION INPUT ;
    USE SIGNAL ;
    ANTENNAGATEAREA 0.724500 ;
    PORT
      LAYER met3 ;
        RECT 219.280 273.400 219.880 274.000 ;
    END
  END Tile_X0Y0_W2END[7]
  PIN Tile_X0Y0_W2MID[0]
    DIRECTION INPUT ;
    USE SIGNAL ;
    ANTENNAGATEAREA 0.780000 ;
    PORT
      LAYER met3 ;
        RECT 219.280 253.000 219.880 253.600 ;
    END
  END Tile_X0Y0_W2MID[0]
  PIN Tile_X0Y0_W2MID[1]
    DIRECTION INPUT ;
    USE SIGNAL ;
    ANTENNAGATEAREA 1.130700 ;
    ANTENNADIFFAREA 0.434700 ;
    PORT
      LAYER met3 ;
        RECT 219.280 254.360 219.880 254.960 ;
    END
  END Tile_X0Y0_W2MID[1]
  PIN Tile_X0Y0_W2MID[2]
    DIRECTION INPUT ;
    USE SIGNAL ;
    ANTENNAGATEAREA 2.374800 ;
    ANTENNADIFFAREA 1.738800 ;
    PORT
      LAYER met3 ;
        RECT 219.280 255.720 219.880 256.320 ;
    END
  END Tile_X0Y0_W2MID[2]
  PIN Tile_X0Y0_W2MID[3]
    DIRECTION INPUT ;
    USE SIGNAL ;
    ANTENNAGATEAREA 2.533800 ;
    ANTENNADIFFAREA 1.738800 ;
    PORT
      LAYER met3 ;
        RECT 219.280 257.080 219.880 257.680 ;
    END
  END Tile_X0Y0_W2MID[3]
  PIN Tile_X0Y0_W2MID[4]
    DIRECTION INPUT ;
    USE SIGNAL ;
    ANTENNAGATEAREA 0.972000 ;
    PORT
      LAYER met3 ;
        RECT 219.280 258.440 219.880 259.040 ;
    END
  END Tile_X0Y0_W2MID[4]
  PIN Tile_X0Y0_W2MID[5]
    DIRECTION INPUT ;
    USE SIGNAL ;
    ANTENNAGATEAREA 1.065000 ;
    PORT
      LAYER met3 ;
        RECT 219.280 259.800 219.880 260.400 ;
    END
  END Tile_X0Y0_W2MID[5]
  PIN Tile_X0Y0_W2MID[6]
    DIRECTION INPUT ;
    USE SIGNAL ;
    ANTENNAGATEAREA 1.907100 ;
    ANTENNADIFFAREA 1.304100 ;
    PORT
      LAYER met3 ;
        RECT 219.280 261.160 219.880 261.760 ;
    END
  END Tile_X0Y0_W2MID[6]
  PIN Tile_X0Y0_W2MID[7]
    DIRECTION INPUT ;
    USE SIGNAL ;
    ANTENNAGATEAREA 0.663000 ;
    PORT
      LAYER met3 ;
        RECT 219.280 262.520 219.880 263.120 ;
    END
  END Tile_X0Y0_W2MID[7]
  PIN Tile_X0Y0_W6BEG[0]
    DIRECTION OUTPUT ;
    USE SIGNAL ;
    ANTENNADIFFAREA 0.702900 ;
    PORT
      LAYER met3 ;
        RECT 0.000 296.520 0.600 297.120 ;
    END
  END Tile_X0Y0_W6BEG[0]
  PIN Tile_X0Y0_W6BEG[10]
    DIRECTION OUTPUT ;
    USE SIGNAL ;
    ANTENNADIFFAREA 0.702900 ;
    PORT
      LAYER met3 ;
        RECT 0.000 310.120 0.600 310.720 ;
    END
  END Tile_X0Y0_W6BEG[10]
  PIN Tile_X0Y0_W6BEG[11]
    DIRECTION OUTPUT ;
    USE SIGNAL ;
    ANTENNADIFFAREA 0.702900 ;
    PORT
      LAYER met3 ;
        RECT 0.000 311.480 0.600 312.080 ;
    END
  END Tile_X0Y0_W6BEG[11]
  PIN Tile_X0Y0_W6BEG[1]
    DIRECTION OUTPUT ;
    USE SIGNAL ;
    ANTENNADIFFAREA 0.702900 ;
    PORT
      LAYER met3 ;
        RECT 0.000 297.880 0.600 298.480 ;
    END
  END Tile_X0Y0_W6BEG[1]
  PIN Tile_X0Y0_W6BEG[2]
    DIRECTION OUTPUT ;
    USE SIGNAL ;
    ANTENNADIFFAREA 0.702900 ;
    PORT
      LAYER met3 ;
        RECT 0.000 299.240 0.600 299.840 ;
    END
  END Tile_X0Y0_W6BEG[2]
  PIN Tile_X0Y0_W6BEG[3]
    DIRECTION OUTPUT ;
    USE SIGNAL ;
    ANTENNADIFFAREA 0.702900 ;
    PORT
      LAYER met3 ;
        RECT 0.000 300.600 0.600 301.200 ;
    END
  END Tile_X0Y0_W6BEG[3]
  PIN Tile_X0Y0_W6BEG[4]
    DIRECTION OUTPUT ;
    USE SIGNAL ;
    ANTENNADIFFAREA 0.702900 ;
    PORT
      LAYER met3 ;
        RECT 0.000 301.960 0.600 302.560 ;
    END
  END Tile_X0Y0_W6BEG[4]
  PIN Tile_X0Y0_W6BEG[5]
    DIRECTION OUTPUT ;
    USE SIGNAL ;
    ANTENNADIFFAREA 0.702900 ;
    PORT
      LAYER met3 ;
        RECT 0.000 303.320 0.600 303.920 ;
    END
  END Tile_X0Y0_W6BEG[5]
  PIN Tile_X0Y0_W6BEG[6]
    DIRECTION OUTPUT ;
    USE SIGNAL ;
    ANTENNADIFFAREA 0.702900 ;
    PORT
      LAYER met3 ;
        RECT 0.000 304.680 0.600 305.280 ;
    END
  END Tile_X0Y0_W6BEG[6]
  PIN Tile_X0Y0_W6BEG[7]
    DIRECTION OUTPUT ;
    USE SIGNAL ;
    ANTENNADIFFAREA 0.702900 ;
    PORT
      LAYER met3 ;
        RECT 0.000 306.040 0.600 306.640 ;
    END
  END Tile_X0Y0_W6BEG[7]
  PIN Tile_X0Y0_W6BEG[8]
    DIRECTION OUTPUT ;
    USE SIGNAL ;
    ANTENNADIFFAREA 0.702900 ;
    PORT
      LAYER met3 ;
        RECT 0.000 307.400 0.600 308.000 ;
    END
  END Tile_X0Y0_W6BEG[8]
  PIN Tile_X0Y0_W6BEG[9]
    DIRECTION OUTPUT ;
    USE SIGNAL ;
    ANTENNADIFFAREA 0.702900 ;
    PORT
      LAYER met3 ;
        RECT 0.000 308.760 0.600 309.360 ;
    END
  END Tile_X0Y0_W6BEG[9]
  PIN Tile_X0Y0_W6END[0]
    DIRECTION INPUT ;
    USE SIGNAL ;
    ANTENNAGATEAREA 3.136800 ;
    ANTENNADIFFAREA 1.738800 ;
    PORT
      LAYER met3 ;
        RECT 219.280 296.520 219.880 297.120 ;
    END
  END Tile_X0Y0_W6END[0]
  PIN Tile_X0Y0_W6END[10]
    DIRECTION INPUT ;
    USE SIGNAL ;
    ANTENNAGATEAREA 0.159000 ;
    PORT
      LAYER met3 ;
        RECT 219.280 310.120 219.880 310.720 ;
    END
  END Tile_X0Y0_W6END[10]
  PIN Tile_X0Y0_W6END[11]
    DIRECTION INPUT ;
    USE SIGNAL ;
    ANTENNAGATEAREA 0.159000 ;
    PORT
      LAYER met3 ;
        RECT 219.280 311.480 219.880 312.080 ;
    END
  END Tile_X0Y0_W6END[11]
  PIN Tile_X0Y0_W6END[1]
    DIRECTION INPUT ;
    USE SIGNAL ;
    ANTENNAGATEAREA 1.524000 ;
    PORT
      LAYER met3 ;
        RECT 219.280 297.880 219.880 298.480 ;
    END
  END Tile_X0Y0_W6END[1]
  PIN Tile_X0Y0_W6END[2]
    DIRECTION INPUT ;
    USE SIGNAL ;
    ANTENNAGATEAREA 0.159000 ;
    PORT
      LAYER met3 ;
        RECT 219.280 299.240 219.880 299.840 ;
    END
  END Tile_X0Y0_W6END[2]
  PIN Tile_X0Y0_W6END[3]
    DIRECTION INPUT ;
    USE SIGNAL ;
    ANTENNAGATEAREA 0.159000 ;
    PORT
      LAYER met3 ;
        RECT 219.280 300.600 219.880 301.200 ;
    END
  END Tile_X0Y0_W6END[3]
  PIN Tile_X0Y0_W6END[4]
    DIRECTION INPUT ;
    USE SIGNAL ;
    ANTENNAGATEAREA 0.159000 ;
    PORT
      LAYER met3 ;
        RECT 219.280 301.960 219.880 302.560 ;
    END
  END Tile_X0Y0_W6END[4]
  PIN Tile_X0Y0_W6END[5]
    DIRECTION INPUT ;
    USE SIGNAL ;
    ANTENNAGATEAREA 0.159000 ;
    PORT
      LAYER met3 ;
        RECT 219.280 303.320 219.880 303.920 ;
    END
  END Tile_X0Y0_W6END[5]
  PIN Tile_X0Y0_W6END[6]
    DIRECTION INPUT ;
    USE SIGNAL ;
    ANTENNAGATEAREA 0.159000 ;
    PORT
      LAYER met3 ;
        RECT 219.280 304.680 219.880 305.280 ;
    END
  END Tile_X0Y0_W6END[6]
  PIN Tile_X0Y0_W6END[7]
    DIRECTION INPUT ;
    USE SIGNAL ;
    ANTENNAGATEAREA 0.159000 ;
    PORT
      LAYER met3 ;
        RECT 219.280 306.040 219.880 306.640 ;
    END
  END Tile_X0Y0_W6END[7]
  PIN Tile_X0Y0_W6END[8]
    DIRECTION INPUT ;
    USE SIGNAL ;
    ANTENNAGATEAREA 0.159000 ;
    PORT
      LAYER met3 ;
        RECT 219.280 307.400 219.880 308.000 ;
    END
  END Tile_X0Y0_W6END[8]
  PIN Tile_X0Y0_W6END[9]
    DIRECTION INPUT ;
    USE SIGNAL ;
    ANTENNAGATEAREA 0.159000 ;
    PORT
      LAYER met3 ;
        RECT 219.280 308.760 219.880 309.360 ;
    END
  END Tile_X0Y0_W6END[9]
  PIN Tile_X0Y0_WW4BEG[0]
    DIRECTION OUTPUT ;
    USE SIGNAL ;
    ANTENNADIFFAREA 0.702900 ;
    PORT
      LAYER met3 ;
        RECT 0.000 274.760 0.600 275.360 ;
    END
  END Tile_X0Y0_WW4BEG[0]
  PIN Tile_X0Y0_WW4BEG[10]
    DIRECTION OUTPUT ;
    USE SIGNAL ;
    ANTENNADIFFAREA 0.702900 ;
    PORT
      LAYER met3 ;
        RECT 0.000 288.360 0.600 288.960 ;
    END
  END Tile_X0Y0_WW4BEG[10]
  PIN Tile_X0Y0_WW4BEG[11]
    DIRECTION OUTPUT ;
    USE SIGNAL ;
    ANTENNADIFFAREA 0.702900 ;
    PORT
      LAYER met3 ;
        RECT 0.000 289.720 0.600 290.320 ;
    END
  END Tile_X0Y0_WW4BEG[11]
  PIN Tile_X0Y0_WW4BEG[12]
    DIRECTION OUTPUT ;
    USE SIGNAL ;
    ANTENNADIFFAREA 0.702900 ;
    PORT
      LAYER met3 ;
        RECT 0.000 291.080 0.600 291.680 ;
    END
  END Tile_X0Y0_WW4BEG[12]
  PIN Tile_X0Y0_WW4BEG[13]
    DIRECTION OUTPUT ;
    USE SIGNAL ;
    ANTENNADIFFAREA 0.702900 ;
    PORT
      LAYER met3 ;
        RECT 0.000 292.440 0.600 293.040 ;
    END
  END Tile_X0Y0_WW4BEG[13]
  PIN Tile_X0Y0_WW4BEG[14]
    DIRECTION OUTPUT ;
    USE SIGNAL ;
    ANTENNADIFFAREA 0.702900 ;
    PORT
      LAYER met3 ;
        RECT 0.000 293.800 0.600 294.400 ;
    END
  END Tile_X0Y0_WW4BEG[14]
  PIN Tile_X0Y0_WW4BEG[15]
    DIRECTION OUTPUT ;
    USE SIGNAL ;
    ANTENNADIFFAREA 0.702900 ;
    PORT
      LAYER met3 ;
        RECT 0.000 295.160 0.600 295.760 ;
    END
  END Tile_X0Y0_WW4BEG[15]
  PIN Tile_X0Y0_WW4BEG[1]
    DIRECTION OUTPUT ;
    USE SIGNAL ;
    ANTENNADIFFAREA 0.702900 ;
    PORT
      LAYER met3 ;
        RECT 0.000 276.120 0.600 276.720 ;
    END
  END Tile_X0Y0_WW4BEG[1]
  PIN Tile_X0Y0_WW4BEG[2]
    DIRECTION OUTPUT ;
    USE SIGNAL ;
    ANTENNADIFFAREA 0.702900 ;
    PORT
      LAYER met3 ;
        RECT 0.000 277.480 0.600 278.080 ;
    END
  END Tile_X0Y0_WW4BEG[2]
  PIN Tile_X0Y0_WW4BEG[3]
    DIRECTION OUTPUT ;
    USE SIGNAL ;
    ANTENNADIFFAREA 0.702900 ;
    PORT
      LAYER met3 ;
        RECT 0.000 278.840 0.600 279.440 ;
    END
  END Tile_X0Y0_WW4BEG[3]
  PIN Tile_X0Y0_WW4BEG[4]
    DIRECTION OUTPUT ;
    USE SIGNAL ;
    ANTENNADIFFAREA 0.702900 ;
    PORT
      LAYER met3 ;
        RECT 0.000 280.200 0.600 280.800 ;
    END
  END Tile_X0Y0_WW4BEG[4]
  PIN Tile_X0Y0_WW4BEG[5]
    DIRECTION OUTPUT ;
    USE SIGNAL ;
    ANTENNADIFFAREA 0.702900 ;
    PORT
      LAYER met3 ;
        RECT 0.000 281.560 0.600 282.160 ;
    END
  END Tile_X0Y0_WW4BEG[5]
  PIN Tile_X0Y0_WW4BEG[6]
    DIRECTION OUTPUT ;
    USE SIGNAL ;
    ANTENNADIFFAREA 0.702900 ;
    PORT
      LAYER met3 ;
        RECT 0.000 282.920 0.600 283.520 ;
    END
  END Tile_X0Y0_WW4BEG[6]
  PIN Tile_X0Y0_WW4BEG[7]
    DIRECTION OUTPUT ;
    USE SIGNAL ;
    ANTENNADIFFAREA 0.702900 ;
    PORT
      LAYER met3 ;
        RECT 0.000 284.280 0.600 284.880 ;
    END
  END Tile_X0Y0_WW4BEG[7]
  PIN Tile_X0Y0_WW4BEG[8]
    DIRECTION OUTPUT ;
    USE SIGNAL ;
    ANTENNADIFFAREA 0.702900 ;
    PORT
      LAYER met3 ;
        RECT 0.000 285.640 0.600 286.240 ;
    END
  END Tile_X0Y0_WW4BEG[8]
  PIN Tile_X0Y0_WW4BEG[9]
    DIRECTION OUTPUT ;
    USE SIGNAL ;
    ANTENNADIFFAREA 0.702900 ;
    PORT
      LAYER met3 ;
        RECT 0.000 287.000 0.600 287.600 ;
    END
  END Tile_X0Y0_WW4BEG[9]
  PIN Tile_X0Y0_WW4END[0]
    DIRECTION INPUT ;
    USE SIGNAL ;
    ANTENNAGATEAREA 1.748100 ;
    ANTENNADIFFAREA 1.304100 ;
    PORT
      LAYER met3 ;
        RECT 219.280 274.760 219.880 275.360 ;
    END
  END Tile_X0Y0_WW4END[0]
  PIN Tile_X0Y0_WW4END[10]
    DIRECTION INPUT ;
    USE SIGNAL ;
    ANTENNAGATEAREA 0.159000 ;
    PORT
      LAYER met3 ;
        RECT 219.280 288.360 219.880 288.960 ;
    END
  END Tile_X0Y0_WW4END[10]
  PIN Tile_X0Y0_WW4END[11]
    DIRECTION INPUT ;
    USE SIGNAL ;
    ANTENNAGATEAREA 0.159000 ;
    PORT
      LAYER met3 ;
        RECT 219.280 289.720 219.880 290.320 ;
    END
  END Tile_X0Y0_WW4END[11]
  PIN Tile_X0Y0_WW4END[12]
    DIRECTION INPUT ;
    USE SIGNAL ;
    ANTENNAGATEAREA 0.159000 ;
    PORT
      LAYER met3 ;
        RECT 219.280 291.080 219.880 291.680 ;
    END
  END Tile_X0Y0_WW4END[12]
  PIN Tile_X0Y0_WW4END[13]
    DIRECTION INPUT ;
    USE SIGNAL ;
    ANTENNAGATEAREA 0.159000 ;
    PORT
      LAYER met3 ;
        RECT 219.280 292.440 219.880 293.040 ;
    END
  END Tile_X0Y0_WW4END[13]
  PIN Tile_X0Y0_WW4END[14]
    DIRECTION INPUT ;
    USE SIGNAL ;
    ANTENNAGATEAREA 0.159000 ;
    PORT
      LAYER met3 ;
        RECT 219.280 293.800 219.880 294.400 ;
    END
  END Tile_X0Y0_WW4END[14]
  PIN Tile_X0Y0_WW4END[15]
    DIRECTION INPUT ;
    USE SIGNAL ;
    ANTENNAGATEAREA 0.159000 ;
    PORT
      LAYER met3 ;
        RECT 219.280 295.160 219.880 295.760 ;
    END
  END Tile_X0Y0_WW4END[15]
  PIN Tile_X0Y0_WW4END[1]
    DIRECTION INPUT ;
    USE SIGNAL ;
    ANTENNAGATEAREA 0.477000 ;
    PORT
      LAYER met3 ;
        RECT 219.280 276.120 219.880 276.720 ;
    END
  END Tile_X0Y0_WW4END[1]
  PIN Tile_X0Y0_WW4END[2]
    DIRECTION INPUT ;
    USE SIGNAL ;
    ANTENNAGATEAREA 1.346400 ;
    ANTENNADIFFAREA 0.869400 ;
    PORT
      LAYER met3 ;
        RECT 219.280 277.480 219.880 278.080 ;
    END
  END Tile_X0Y0_WW4END[2]
  PIN Tile_X0Y0_WW4END[3]
    DIRECTION INPUT ;
    USE SIGNAL ;
    ANTENNAGATEAREA 1.715100 ;
    ANTENNADIFFAREA 1.304100 ;
    PORT
      LAYER met3 ;
        RECT 219.280 278.840 219.880 279.440 ;
    END
  END Tile_X0Y0_WW4END[3]
  PIN Tile_X0Y0_WW4END[4]
    DIRECTION INPUT ;
    USE SIGNAL ;
    ANTENNAGATEAREA 0.159000 ;
    PORT
      LAYER met3 ;
        RECT 219.280 280.200 219.880 280.800 ;
    END
  END Tile_X0Y0_WW4END[4]
  PIN Tile_X0Y0_WW4END[5]
    DIRECTION INPUT ;
    USE SIGNAL ;
    ANTENNAGATEAREA 0.159000 ;
    PORT
      LAYER met3 ;
        RECT 219.280 281.560 219.880 282.160 ;
    END
  END Tile_X0Y0_WW4END[5]
  PIN Tile_X0Y0_WW4END[6]
    DIRECTION INPUT ;
    USE SIGNAL ;
    ANTENNAGATEAREA 0.159000 ;
    PORT
      LAYER met3 ;
        RECT 219.280 282.920 219.880 283.520 ;
    END
  END Tile_X0Y0_WW4END[6]
  PIN Tile_X0Y0_WW4END[7]
    DIRECTION INPUT ;
    USE SIGNAL ;
    ANTENNAGATEAREA 0.159000 ;
    PORT
      LAYER met3 ;
        RECT 219.280 284.280 219.880 284.880 ;
    END
  END Tile_X0Y0_WW4END[7]
  PIN Tile_X0Y0_WW4END[8]
    DIRECTION INPUT ;
    USE SIGNAL ;
    ANTENNAGATEAREA 0.159000 ;
    PORT
      LAYER met3 ;
        RECT 219.280 285.640 219.880 286.240 ;
    END
  END Tile_X0Y0_WW4END[8]
  PIN Tile_X0Y0_WW4END[9]
    DIRECTION INPUT ;
    USE SIGNAL ;
    ANTENNAGATEAREA 0.159000 ;
    PORT
      LAYER met3 ;
        RECT 219.280 287.000 219.880 287.600 ;
    END
  END Tile_X0Y0_WW4END[9]
  PIN Tile_X0Y1_CI
    DIRECTION INPUT ;
    USE SIGNAL ;
    ANTENNAGATEAREA 0.495000 ;
    PORT
      LAYER met2 ;
        RECT 98.530 0.000 98.810 0.280 ;
    END
  END Tile_X0Y1_CI
  PIN Tile_X0Y1_E1BEG[0]
    DIRECTION OUTPUT ;
    USE SIGNAL ;
    ANTENNADIFFAREA 0.702900 ;
    PORT
      LAYER met3 ;
        RECT 219.280 89.800 219.880 90.400 ;
    END
  END Tile_X0Y1_E1BEG[0]
  PIN Tile_X0Y1_E1BEG[1]
    DIRECTION OUTPUT ;
    USE SIGNAL ;
    ANTENNADIFFAREA 0.702900 ;
    PORT
      LAYER met3 ;
        RECT 219.280 91.160 219.880 91.760 ;
    END
  END Tile_X0Y1_E1BEG[1]
  PIN Tile_X0Y1_E1BEG[2]
    DIRECTION OUTPUT ;
    USE SIGNAL ;
    ANTENNADIFFAREA 0.702900 ;
    PORT
      LAYER met3 ;
        RECT 219.280 92.520 219.880 93.120 ;
    END
  END Tile_X0Y1_E1BEG[2]
  PIN Tile_X0Y1_E1BEG[3]
    DIRECTION OUTPUT ;
    USE SIGNAL ;
    ANTENNADIFFAREA 0.702900 ;
    PORT
      LAYER met3 ;
        RECT 219.280 93.880 219.880 94.480 ;
    END
  END Tile_X0Y1_E1BEG[3]
  PIN Tile_X0Y1_E1END[0]
    DIRECTION INPUT ;
    USE SIGNAL ;
    ANTENNAGATEAREA 3.071100 ;
    ANTENNADIFFAREA 1.304100 ;
    PORT
      LAYER met3 ;
        RECT 0.000 89.800 0.600 90.400 ;
    END
  END Tile_X0Y1_E1END[0]
  PIN Tile_X0Y1_E1END[1]
    DIRECTION INPUT ;
    USE SIGNAL ;
    ANTENNAGATEAREA 2.636100 ;
    ANTENNADIFFAREA 1.304100 ;
    PORT
      LAYER met3 ;
        RECT 0.000 91.160 0.600 91.760 ;
    END
  END Tile_X0Y1_E1END[1]
  PIN Tile_X0Y1_E1END[2]
    DIRECTION INPUT ;
    USE SIGNAL ;
    ANTENNAGATEAREA 1.749000 ;
    PORT
      LAYER met3 ;
        RECT 0.000 92.520 0.600 93.120 ;
    END
  END Tile_X0Y1_E1END[2]
  PIN Tile_X0Y1_E1END[3]
    DIRECTION INPUT ;
    USE SIGNAL ;
    ANTENNAGATEAREA 1.860000 ;
    PORT
      LAYER met3 ;
        RECT 0.000 93.880 0.600 94.480 ;
    END
  END Tile_X0Y1_E1END[3]
  PIN Tile_X0Y1_E2BEG[0]
    DIRECTION OUTPUT ;
    USE SIGNAL ;
    ANTENNADIFFAREA 0.702900 ;
    PORT
      LAYER met3 ;
        RECT 219.280 95.240 219.880 95.840 ;
    END
  END Tile_X0Y1_E2BEG[0]
  PIN Tile_X0Y1_E2BEG[1]
    DIRECTION OUTPUT ;
    USE SIGNAL ;
    ANTENNADIFFAREA 0.702900 ;
    PORT
      LAYER met3 ;
        RECT 219.280 96.600 219.880 97.200 ;
    END
  END Tile_X0Y1_E2BEG[1]
  PIN Tile_X0Y1_E2BEG[2]
    DIRECTION OUTPUT ;
    USE SIGNAL ;
    ANTENNADIFFAREA 0.702900 ;
    PORT
      LAYER met3 ;
        RECT 219.280 97.960 219.880 98.560 ;
    END
  END Tile_X0Y1_E2BEG[2]
  PIN Tile_X0Y1_E2BEG[3]
    DIRECTION OUTPUT ;
    USE SIGNAL ;
    ANTENNADIFFAREA 0.702900 ;
    PORT
      LAYER met3 ;
        RECT 219.280 99.320 219.880 99.920 ;
    END
  END Tile_X0Y1_E2BEG[3]
  PIN Tile_X0Y1_E2BEG[4]
    DIRECTION OUTPUT ;
    USE SIGNAL ;
    ANTENNADIFFAREA 0.702900 ;
    PORT
      LAYER met3 ;
        RECT 219.280 100.680 219.880 101.280 ;
    END
  END Tile_X0Y1_E2BEG[4]
  PIN Tile_X0Y1_E2BEG[5]
    DIRECTION OUTPUT ;
    USE SIGNAL ;
    ANTENNADIFFAREA 0.702900 ;
    PORT
      LAYER met3 ;
        RECT 219.280 102.040 219.880 102.640 ;
    END
  END Tile_X0Y1_E2BEG[5]
  PIN Tile_X0Y1_E2BEG[6]
    DIRECTION OUTPUT ;
    USE SIGNAL ;
    ANTENNADIFFAREA 0.702900 ;
    PORT
      LAYER met3 ;
        RECT 219.280 103.400 219.880 104.000 ;
    END
  END Tile_X0Y1_E2BEG[6]
  PIN Tile_X0Y1_E2BEG[7]
    DIRECTION OUTPUT ;
    USE SIGNAL ;
    ANTENNADIFFAREA 0.702900 ;
    PORT
      LAYER met3 ;
        RECT 219.280 104.760 219.880 105.360 ;
    END
  END Tile_X0Y1_E2BEG[7]
  PIN Tile_X0Y1_E2BEGb[0]
    DIRECTION OUTPUT ;
    USE SIGNAL ;
    ANTENNADIFFAREA 0.702900 ;
    PORT
      LAYER met3 ;
        RECT 219.280 106.120 219.880 106.720 ;
    END
  END Tile_X0Y1_E2BEGb[0]
  PIN Tile_X0Y1_E2BEGb[1]
    DIRECTION OUTPUT ;
    USE SIGNAL ;
    ANTENNADIFFAREA 0.702900 ;
    PORT
      LAYER met3 ;
        RECT 219.280 107.480 219.880 108.080 ;
    END
  END Tile_X0Y1_E2BEGb[1]
  PIN Tile_X0Y1_E2BEGb[2]
    DIRECTION OUTPUT ;
    USE SIGNAL ;
    ANTENNADIFFAREA 0.702900 ;
    PORT
      LAYER met3 ;
        RECT 219.280 108.840 219.880 109.440 ;
    END
  END Tile_X0Y1_E2BEGb[2]
  PIN Tile_X0Y1_E2BEGb[3]
    DIRECTION OUTPUT ;
    USE SIGNAL ;
    ANTENNADIFFAREA 0.702900 ;
    PORT
      LAYER met3 ;
        RECT 219.280 110.200 219.880 110.800 ;
    END
  END Tile_X0Y1_E2BEGb[3]
  PIN Tile_X0Y1_E2BEGb[4]
    DIRECTION OUTPUT ;
    USE SIGNAL ;
    ANTENNADIFFAREA 0.702900 ;
    PORT
      LAYER met3 ;
        RECT 219.280 111.560 219.880 112.160 ;
    END
  END Tile_X0Y1_E2BEGb[4]
  PIN Tile_X0Y1_E2BEGb[5]
    DIRECTION OUTPUT ;
    USE SIGNAL ;
    ANTENNADIFFAREA 0.702900 ;
    PORT
      LAYER met3 ;
        RECT 219.280 112.920 219.880 113.520 ;
    END
  END Tile_X0Y1_E2BEGb[5]
  PIN Tile_X0Y1_E2BEGb[6]
    DIRECTION OUTPUT ;
    USE SIGNAL ;
    ANTENNADIFFAREA 0.702900 ;
    PORT
      LAYER met3 ;
        RECT 219.280 114.280 219.880 114.880 ;
    END
  END Tile_X0Y1_E2BEGb[6]
  PIN Tile_X0Y1_E2BEGb[7]
    DIRECTION OUTPUT ;
    USE SIGNAL ;
    ANTENNADIFFAREA 0.702900 ;
    PORT
      LAYER met3 ;
        RECT 219.280 115.640 219.880 116.240 ;
    END
  END Tile_X0Y1_E2BEGb[7]
  PIN Tile_X0Y1_E2END[0]
    DIRECTION INPUT ;
    USE SIGNAL ;
    ANTENNAGATEAREA 0.636000 ;
    PORT
      LAYER met3 ;
        RECT 0.000 106.120 0.600 106.720 ;
    END
  END Tile_X0Y1_E2END[0]
  PIN Tile_X0Y1_E2END[1]
    DIRECTION INPUT ;
    USE SIGNAL ;
    ANTENNAGATEAREA 0.636000 ;
    PORT
      LAYER met3 ;
        RECT 0.000 107.480 0.600 108.080 ;
    END
  END Tile_X0Y1_E2END[1]
  PIN Tile_X0Y1_E2END[2]
    DIRECTION INPUT ;
    USE SIGNAL ;
    ANTENNAGATEAREA 1.481700 ;
    ANTENNADIFFAREA 0.434700 ;
    PORT
      LAYER met3 ;
        RECT 0.000 108.840 0.600 109.440 ;
    END
  END Tile_X0Y1_E2END[2]
  PIN Tile_X0Y1_E2END[3]
    DIRECTION INPUT ;
    USE SIGNAL ;
    ANTENNAGATEAREA 1.239000 ;
    PORT
      LAYER met3 ;
        RECT 0.000 110.200 0.600 110.800 ;
    END
  END Tile_X0Y1_E2END[3]
  PIN Tile_X0Y1_E2END[4]
    DIRECTION INPUT ;
    USE SIGNAL ;
    ANTENNAGATEAREA 2.099100 ;
    ANTENNADIFFAREA 1.304100 ;
    PORT
      LAYER met3 ;
        RECT 0.000 111.560 0.600 112.160 ;
    END
  END Tile_X0Y1_E2END[4]
  PIN Tile_X0Y1_E2END[5]
    DIRECTION INPUT ;
    USE SIGNAL ;
    ANTENNAGATEAREA 1.823400 ;
    ANTENNADIFFAREA 0.869400 ;
    PORT
      LAYER met3 ;
        RECT 0.000 112.920 0.600 113.520 ;
    END
  END Tile_X0Y1_E2END[5]
  PIN Tile_X0Y1_E2END[6]
    DIRECTION INPUT ;
    USE SIGNAL ;
    ANTENNAGATEAREA 0.954000 ;
    PORT
      LAYER met3 ;
        RECT 0.000 114.280 0.600 114.880 ;
    END
  END Tile_X0Y1_E2END[6]
  PIN Tile_X0Y1_E2END[7]
    DIRECTION INPUT ;
    USE SIGNAL ;
    ANTENNAGATEAREA 0.795000 ;
    PORT
      LAYER met3 ;
        RECT 0.000 115.640 0.600 116.240 ;
    END
  END Tile_X0Y1_E2END[7]
  PIN Tile_X0Y1_E2MID[0]
    DIRECTION INPUT ;
    USE SIGNAL ;
    ANTENNAGATEAREA 1.032000 ;
    PORT
      LAYER met3 ;
        RECT 0.000 95.240 0.600 95.840 ;
    END
  END Tile_X0Y1_E2MID[0]
  PIN Tile_X0Y1_E2MID[1]
    DIRECTION INPUT ;
    USE SIGNAL ;
    ANTENNAGATEAREA 1.130700 ;
    ANTENNADIFFAREA 0.434700 ;
    PORT
      LAYER met3 ;
        RECT 0.000 96.600 0.600 97.200 ;
    END
  END Tile_X0Y1_E2MID[1]
  PIN Tile_X0Y1_E2MID[2]
    DIRECTION INPUT ;
    USE SIGNAL ;
    ANTENNAGATEAREA 2.341800 ;
    ANTENNADIFFAREA 1.738800 ;
    PORT
      LAYER met3 ;
        RECT 0.000 97.960 0.600 98.560 ;
    END
  END Tile_X0Y1_E2MID[2]
  PIN Tile_X0Y1_E2MID[3]
    DIRECTION INPUT ;
    USE SIGNAL ;
    ANTENNAGATEAREA 0.795000 ;
    PORT
      LAYER met3 ;
        RECT 0.000 99.320 0.600 99.920 ;
    END
  END Tile_X0Y1_E2MID[3]
  PIN Tile_X0Y1_E2MID[4]
    DIRECTION INPUT ;
    USE SIGNAL ;
    ANTENNAGATEAREA 1.907100 ;
    ANTENNADIFFAREA 1.304100 ;
    PORT
      LAYER met3 ;
        RECT 0.000 100.680 0.600 101.280 ;
    END
  END Tile_X0Y1_E2MID[4]
  PIN Tile_X0Y1_E2MID[5]
    DIRECTION INPUT ;
    USE SIGNAL ;
    ANTENNAGATEAREA 1.098000 ;
    PORT
      LAYER met3 ;
        RECT 0.000 102.040 0.600 102.640 ;
    END
  END Tile_X0Y1_E2MID[5]
  PIN Tile_X0Y1_E2MID[6]
    DIRECTION INPUT ;
    USE SIGNAL ;
    ANTENNAGATEAREA 0.822000 ;
    PORT
      LAYER met3 ;
        RECT 0.000 103.400 0.600 104.000 ;
    END
  END Tile_X0Y1_E2MID[6]
  PIN Tile_X0Y1_E2MID[7]
    DIRECTION INPUT ;
    USE SIGNAL ;
    ANTENNAGATEAREA 0.663000 ;
    PORT
      LAYER met3 ;
        RECT 0.000 104.760 0.600 105.360 ;
    END
  END Tile_X0Y1_E2MID[7]
  PIN Tile_X0Y1_E6BEG[0]
    DIRECTION OUTPUT ;
    USE SIGNAL ;
    ANTENNADIFFAREA 0.702900 ;
    PORT
      LAYER met3 ;
        RECT 219.280 138.760 219.880 139.360 ;
    END
  END Tile_X0Y1_E6BEG[0]
  PIN Tile_X0Y1_E6BEG[10]
    DIRECTION OUTPUT ;
    USE SIGNAL ;
    ANTENNADIFFAREA 0.702900 ;
    PORT
      LAYER met3 ;
        RECT 219.280 152.360 219.880 152.960 ;
    END
  END Tile_X0Y1_E6BEG[10]
  PIN Tile_X0Y1_E6BEG[11]
    DIRECTION OUTPUT ;
    USE SIGNAL ;
    ANTENNADIFFAREA 0.702900 ;
    PORT
      LAYER met3 ;
        RECT 219.280 153.720 219.880 154.320 ;
    END
  END Tile_X0Y1_E6BEG[11]
  PIN Tile_X0Y1_E6BEG[1]
    DIRECTION OUTPUT ;
    USE SIGNAL ;
    ANTENNADIFFAREA 0.702900 ;
    PORT
      LAYER met3 ;
        RECT 219.280 140.120 219.880 140.720 ;
    END
  END Tile_X0Y1_E6BEG[1]
  PIN Tile_X0Y1_E6BEG[2]
    DIRECTION OUTPUT ;
    USE SIGNAL ;
    ANTENNADIFFAREA 0.702900 ;
    PORT
      LAYER met3 ;
        RECT 219.280 141.480 219.880 142.080 ;
    END
  END Tile_X0Y1_E6BEG[2]
  PIN Tile_X0Y1_E6BEG[3]
    DIRECTION OUTPUT ;
    USE SIGNAL ;
    ANTENNADIFFAREA 0.702900 ;
    PORT
      LAYER met3 ;
        RECT 219.280 142.840 219.880 143.440 ;
    END
  END Tile_X0Y1_E6BEG[3]
  PIN Tile_X0Y1_E6BEG[4]
    DIRECTION OUTPUT ;
    USE SIGNAL ;
    ANTENNADIFFAREA 0.702900 ;
    PORT
      LAYER met3 ;
        RECT 219.280 144.200 219.880 144.800 ;
    END
  END Tile_X0Y1_E6BEG[4]
  PIN Tile_X0Y1_E6BEG[5]
    DIRECTION OUTPUT ;
    USE SIGNAL ;
    ANTENNADIFFAREA 0.702900 ;
    PORT
      LAYER met3 ;
        RECT 219.280 145.560 219.880 146.160 ;
    END
  END Tile_X0Y1_E6BEG[5]
  PIN Tile_X0Y1_E6BEG[6]
    DIRECTION OUTPUT ;
    USE SIGNAL ;
    ANTENNADIFFAREA 0.702900 ;
    PORT
      LAYER met3 ;
        RECT 219.280 146.920 219.880 147.520 ;
    END
  END Tile_X0Y1_E6BEG[6]
  PIN Tile_X0Y1_E6BEG[7]
    DIRECTION OUTPUT ;
    USE SIGNAL ;
    ANTENNADIFFAREA 0.702900 ;
    PORT
      LAYER met3 ;
        RECT 219.280 148.280 219.880 148.880 ;
    END
  END Tile_X0Y1_E6BEG[7]
  PIN Tile_X0Y1_E6BEG[8]
    DIRECTION OUTPUT ;
    USE SIGNAL ;
    ANTENNADIFFAREA 0.702900 ;
    PORT
      LAYER met3 ;
        RECT 219.280 149.640 219.880 150.240 ;
    END
  END Tile_X0Y1_E6BEG[8]
  PIN Tile_X0Y1_E6BEG[9]
    DIRECTION OUTPUT ;
    USE SIGNAL ;
    ANTENNADIFFAREA 0.702900 ;
    PORT
      LAYER met3 ;
        RECT 219.280 151.000 219.880 151.600 ;
    END
  END Tile_X0Y1_E6BEG[9]
  PIN Tile_X0Y1_E6END[0]
    DIRECTION INPUT ;
    USE SIGNAL ;
    ANTENNAGATEAREA 1.908000 ;
    PORT
      LAYER met3 ;
        RECT 0.000 138.760 0.600 139.360 ;
    END
  END Tile_X0Y1_E6END[0]
  PIN Tile_X0Y1_E6END[10]
    DIRECTION INPUT ;
    USE SIGNAL ;
    ANTENNAGATEAREA 0.159000 ;
    PORT
      LAYER met3 ;
        RECT 0.000 152.360 0.600 152.960 ;
    END
  END Tile_X0Y1_E6END[10]
  PIN Tile_X0Y1_E6END[11]
    DIRECTION INPUT ;
    USE SIGNAL ;
    ANTENNAGATEAREA 0.159000 ;
    PORT
      LAYER met3 ;
        RECT 0.000 153.720 0.600 154.320 ;
    END
  END Tile_X0Y1_E6END[11]
  PIN Tile_X0Y1_E6END[1]
    DIRECTION INPUT ;
    USE SIGNAL ;
    ANTENNAGATEAREA 1.908000 ;
    PORT
      LAYER met3 ;
        RECT 0.000 140.120 0.600 140.720 ;
    END
  END Tile_X0Y1_E6END[1]
  PIN Tile_X0Y1_E6END[2]
    DIRECTION INPUT ;
    USE SIGNAL ;
    ANTENNAGATEAREA 0.159000 ;
    PORT
      LAYER met3 ;
        RECT 0.000 141.480 0.600 142.080 ;
    END
  END Tile_X0Y1_E6END[2]
  PIN Tile_X0Y1_E6END[3]
    DIRECTION INPUT ;
    USE SIGNAL ;
    ANTENNAGATEAREA 0.159000 ;
    PORT
      LAYER met3 ;
        RECT 0.000 142.840 0.600 143.440 ;
    END
  END Tile_X0Y1_E6END[3]
  PIN Tile_X0Y1_E6END[4]
    DIRECTION INPUT ;
    USE SIGNAL ;
    ANTENNAGATEAREA 0.159000 ;
    PORT
      LAYER met3 ;
        RECT 0.000 144.200 0.600 144.800 ;
    END
  END Tile_X0Y1_E6END[4]
  PIN Tile_X0Y1_E6END[5]
    DIRECTION INPUT ;
    USE SIGNAL ;
    ANTENNAGATEAREA 0.159000 ;
    PORT
      LAYER met3 ;
        RECT 0.000 145.560 0.600 146.160 ;
    END
  END Tile_X0Y1_E6END[5]
  PIN Tile_X0Y1_E6END[6]
    DIRECTION INPUT ;
    USE SIGNAL ;
    ANTENNAGATEAREA 0.159000 ;
    PORT
      LAYER met3 ;
        RECT 0.000 146.920 0.600 147.520 ;
    END
  END Tile_X0Y1_E6END[6]
  PIN Tile_X0Y1_E6END[7]
    DIRECTION INPUT ;
    USE SIGNAL ;
    ANTENNAGATEAREA 0.159000 ;
    PORT
      LAYER met3 ;
        RECT 0.000 148.280 0.600 148.880 ;
    END
  END Tile_X0Y1_E6END[7]
  PIN Tile_X0Y1_E6END[8]
    DIRECTION INPUT ;
    USE SIGNAL ;
    ANTENNAGATEAREA 0.159000 ;
    PORT
      LAYER met3 ;
        RECT 0.000 149.640 0.600 150.240 ;
    END
  END Tile_X0Y1_E6END[8]
  PIN Tile_X0Y1_E6END[9]
    DIRECTION INPUT ;
    USE SIGNAL ;
    ANTENNAGATEAREA 0.159000 ;
    PORT
      LAYER met3 ;
        RECT 0.000 151.000 0.600 151.600 ;
    END
  END Tile_X0Y1_E6END[9]
  PIN Tile_X0Y1_EE4BEG[0]
    DIRECTION OUTPUT ;
    USE SIGNAL ;
    ANTENNADIFFAREA 0.702900 ;
    PORT
      LAYER met3 ;
        RECT 219.280 117.000 219.880 117.600 ;
    END
  END Tile_X0Y1_EE4BEG[0]
  PIN Tile_X0Y1_EE4BEG[10]
    DIRECTION OUTPUT ;
    USE SIGNAL ;
    ANTENNADIFFAREA 0.702900 ;
    PORT
      LAYER met3 ;
        RECT 219.280 130.600 219.880 131.200 ;
    END
  END Tile_X0Y1_EE4BEG[10]
  PIN Tile_X0Y1_EE4BEG[11]
    DIRECTION OUTPUT ;
    USE SIGNAL ;
    ANTENNADIFFAREA 0.702900 ;
    PORT
      LAYER met3 ;
        RECT 219.280 131.960 219.880 132.560 ;
    END
  END Tile_X0Y1_EE4BEG[11]
  PIN Tile_X0Y1_EE4BEG[12]
    DIRECTION OUTPUT ;
    USE SIGNAL ;
    ANTENNADIFFAREA 0.702900 ;
    PORT
      LAYER met3 ;
        RECT 219.280 133.320 219.880 133.920 ;
    END
  END Tile_X0Y1_EE4BEG[12]
  PIN Tile_X0Y1_EE4BEG[13]
    DIRECTION OUTPUT ;
    USE SIGNAL ;
    ANTENNADIFFAREA 0.702900 ;
    PORT
      LAYER met3 ;
        RECT 219.280 134.680 219.880 135.280 ;
    END
  END Tile_X0Y1_EE4BEG[13]
  PIN Tile_X0Y1_EE4BEG[14]
    DIRECTION OUTPUT ;
    USE SIGNAL ;
    ANTENNADIFFAREA 0.702900 ;
    PORT
      LAYER met3 ;
        RECT 219.280 136.040 219.880 136.640 ;
    END
  END Tile_X0Y1_EE4BEG[14]
  PIN Tile_X0Y1_EE4BEG[15]
    DIRECTION OUTPUT ;
    USE SIGNAL ;
    ANTENNADIFFAREA 0.702900 ;
    PORT
      LAYER met3 ;
        RECT 219.280 137.400 219.880 138.000 ;
    END
  END Tile_X0Y1_EE4BEG[15]
  PIN Tile_X0Y1_EE4BEG[1]
    DIRECTION OUTPUT ;
    USE SIGNAL ;
    ANTENNADIFFAREA 0.702900 ;
    PORT
      LAYER met3 ;
        RECT 219.280 118.360 219.880 118.960 ;
    END
  END Tile_X0Y1_EE4BEG[1]
  PIN Tile_X0Y1_EE4BEG[2]
    DIRECTION OUTPUT ;
    USE SIGNAL ;
    ANTENNADIFFAREA 0.702900 ;
    PORT
      LAYER met3 ;
        RECT 219.280 119.720 219.880 120.320 ;
    END
  END Tile_X0Y1_EE4BEG[2]
  PIN Tile_X0Y1_EE4BEG[3]
    DIRECTION OUTPUT ;
    USE SIGNAL ;
    ANTENNADIFFAREA 0.702900 ;
    PORT
      LAYER met3 ;
        RECT 219.280 121.080 219.880 121.680 ;
    END
  END Tile_X0Y1_EE4BEG[3]
  PIN Tile_X0Y1_EE4BEG[4]
    DIRECTION OUTPUT ;
    USE SIGNAL ;
    ANTENNADIFFAREA 0.702900 ;
    PORT
      LAYER met3 ;
        RECT 219.280 122.440 219.880 123.040 ;
    END
  END Tile_X0Y1_EE4BEG[4]
  PIN Tile_X0Y1_EE4BEG[5]
    DIRECTION OUTPUT ;
    USE SIGNAL ;
    ANTENNADIFFAREA 0.702900 ;
    PORT
      LAYER met3 ;
        RECT 219.280 123.800 219.880 124.400 ;
    END
  END Tile_X0Y1_EE4BEG[5]
  PIN Tile_X0Y1_EE4BEG[6]
    DIRECTION OUTPUT ;
    USE SIGNAL ;
    ANTENNADIFFAREA 0.702900 ;
    PORT
      LAYER met3 ;
        RECT 219.280 125.160 219.880 125.760 ;
    END
  END Tile_X0Y1_EE4BEG[6]
  PIN Tile_X0Y1_EE4BEG[7]
    DIRECTION OUTPUT ;
    USE SIGNAL ;
    ANTENNADIFFAREA 0.702900 ;
    PORT
      LAYER met3 ;
        RECT 219.280 126.520 219.880 127.120 ;
    END
  END Tile_X0Y1_EE4BEG[7]
  PIN Tile_X0Y1_EE4BEG[8]
    DIRECTION OUTPUT ;
    USE SIGNAL ;
    ANTENNADIFFAREA 0.702900 ;
    PORT
      LAYER met3 ;
        RECT 219.280 127.880 219.880 128.480 ;
    END
  END Tile_X0Y1_EE4BEG[8]
  PIN Tile_X0Y1_EE4BEG[9]
    DIRECTION OUTPUT ;
    USE SIGNAL ;
    ANTENNADIFFAREA 0.702900 ;
    PORT
      LAYER met3 ;
        RECT 219.280 129.240 219.880 129.840 ;
    END
  END Tile_X0Y1_EE4BEG[9]
  PIN Tile_X0Y1_EE4END[0]
    DIRECTION INPUT ;
    USE SIGNAL ;
    ANTENNAGATEAREA 1.313400 ;
    ANTENNADIFFAREA 0.869400 ;
    PORT
      LAYER met3 ;
        RECT 0.000 117.000 0.600 117.600 ;
    END
  END Tile_X0Y1_EE4END[0]
  PIN Tile_X0Y1_EE4END[10]
    DIRECTION INPUT ;
    USE SIGNAL ;
    ANTENNAGATEAREA 0.159000 ;
    PORT
      LAYER met3 ;
        RECT 0.000 130.600 0.600 131.200 ;
    END
  END Tile_X0Y1_EE4END[10]
  PIN Tile_X0Y1_EE4END[11]
    DIRECTION INPUT ;
    USE SIGNAL ;
    ANTENNAGATEAREA 0.159000 ;
    PORT
      LAYER met3 ;
        RECT 0.000 131.960 0.600 132.560 ;
    END
  END Tile_X0Y1_EE4END[11]
  PIN Tile_X0Y1_EE4END[12]
    DIRECTION INPUT ;
    USE SIGNAL ;
    ANTENNAGATEAREA 0.159000 ;
    PORT
      LAYER met3 ;
        RECT 0.000 133.320 0.600 133.920 ;
    END
  END Tile_X0Y1_EE4END[12]
  PIN Tile_X0Y1_EE4END[13]
    DIRECTION INPUT ;
    USE SIGNAL ;
    ANTENNAGATEAREA 0.159000 ;
    PORT
      LAYER met3 ;
        RECT 0.000 134.680 0.600 135.280 ;
    END
  END Tile_X0Y1_EE4END[13]
  PIN Tile_X0Y1_EE4END[14]
    DIRECTION INPUT ;
    USE SIGNAL ;
    ANTENNAGATEAREA 0.159000 ;
    PORT
      LAYER met3 ;
        RECT 0.000 136.040 0.600 136.640 ;
    END
  END Tile_X0Y1_EE4END[14]
  PIN Tile_X0Y1_EE4END[15]
    DIRECTION INPUT ;
    USE SIGNAL ;
    ANTENNAGATEAREA 0.159000 ;
    PORT
      LAYER met3 ;
        RECT 0.000 137.400 0.600 138.000 ;
    END
  END Tile_X0Y1_EE4END[15]
  PIN Tile_X0Y1_EE4END[1]
    DIRECTION INPUT ;
    USE SIGNAL ;
    ANTENNAGATEAREA 0.477000 ;
    PORT
      LAYER met3 ;
        RECT 0.000 118.360 0.600 118.960 ;
    END
  END Tile_X0Y1_EE4END[1]
  PIN Tile_X0Y1_EE4END[2]
    DIRECTION INPUT ;
    USE SIGNAL ;
    ANTENNAGATEAREA 1.781100 ;
    ANTENNADIFFAREA 1.304100 ;
    PORT
      LAYER met3 ;
        RECT 0.000 119.720 0.600 120.320 ;
    END
  END Tile_X0Y1_EE4END[2]
  PIN Tile_X0Y1_EE4END[3]
    DIRECTION INPUT ;
    USE SIGNAL ;
    ANTENNAGATEAREA 0.285000 ;
    PORT
      LAYER met3 ;
        RECT 0.000 121.080 0.600 121.680 ;
    END
  END Tile_X0Y1_EE4END[3]
  PIN Tile_X0Y1_EE4END[4]
    DIRECTION INPUT ;
    USE SIGNAL ;
    ANTENNAGATEAREA 0.159000 ;
    PORT
      LAYER met3 ;
        RECT 0.000 122.440 0.600 123.040 ;
    END
  END Tile_X0Y1_EE4END[4]
  PIN Tile_X0Y1_EE4END[5]
    DIRECTION INPUT ;
    USE SIGNAL ;
    ANTENNAGATEAREA 0.159000 ;
    PORT
      LAYER met3 ;
        RECT 0.000 123.800 0.600 124.400 ;
    END
  END Tile_X0Y1_EE4END[5]
  PIN Tile_X0Y1_EE4END[6]
    DIRECTION INPUT ;
    USE SIGNAL ;
    ANTENNAGATEAREA 0.159000 ;
    PORT
      LAYER met3 ;
        RECT 0.000 125.160 0.600 125.760 ;
    END
  END Tile_X0Y1_EE4END[6]
  PIN Tile_X0Y1_EE4END[7]
    DIRECTION INPUT ;
    USE SIGNAL ;
    ANTENNAGATEAREA 0.159000 ;
    PORT
      LAYER met3 ;
        RECT 0.000 126.520 0.600 127.120 ;
    END
  END Tile_X0Y1_EE4END[7]
  PIN Tile_X0Y1_EE4END[8]
    DIRECTION INPUT ;
    USE SIGNAL ;
    ANTENNAGATEAREA 0.159000 ;
    PORT
      LAYER met3 ;
        RECT 0.000 127.880 0.600 128.480 ;
    END
  END Tile_X0Y1_EE4END[8]
  PIN Tile_X0Y1_EE4END[9]
    DIRECTION INPUT ;
    USE SIGNAL ;
    ANTENNAGATEAREA 0.159000 ;
    PORT
      LAYER met3 ;
        RECT 0.000 129.240 0.600 129.840 ;
    END
  END Tile_X0Y1_EE4END[9]
  PIN Tile_X0Y1_FrameData[0]
    DIRECTION INPUT ;
    USE SIGNAL ;
    ANTENNAGATEAREA 2.226000 ;
    PORT
      LAYER met3 ;
        RECT 0.000 155.080 0.600 155.680 ;
    END
  END Tile_X0Y1_FrameData[0]
  PIN Tile_X0Y1_FrameData[10]
    DIRECTION INPUT ;
    USE SIGNAL ;
    ANTENNAGATEAREA 2.226000 ;
    PORT
      LAYER met3 ;
        RECT 0.000 168.680 0.600 169.280 ;
    END
  END Tile_X0Y1_FrameData[10]
  PIN Tile_X0Y1_FrameData[11]
    DIRECTION INPUT ;
    USE SIGNAL ;
    ANTENNAGATEAREA 2.226000 ;
    PORT
      LAYER met3 ;
        RECT 0.000 170.040 0.600 170.640 ;
    END
  END Tile_X0Y1_FrameData[11]
  PIN Tile_X0Y1_FrameData[12]
    DIRECTION INPUT ;
    USE SIGNAL ;
    ANTENNAGATEAREA 2.226000 ;
    PORT
      LAYER met3 ;
        RECT 0.000 171.400 0.600 172.000 ;
    END
  END Tile_X0Y1_FrameData[12]
  PIN Tile_X0Y1_FrameData[13]
    DIRECTION INPUT ;
    USE SIGNAL ;
    ANTENNAGATEAREA 2.226000 ;
    PORT
      LAYER met3 ;
        RECT 0.000 172.760 0.600 173.360 ;
    END
  END Tile_X0Y1_FrameData[13]
  PIN Tile_X0Y1_FrameData[14]
    DIRECTION INPUT ;
    USE SIGNAL ;
    ANTENNAGATEAREA 3.095400 ;
    ANTENNADIFFAREA 0.869400 ;
    PORT
      LAYER met3 ;
        RECT 0.000 174.120 0.600 174.720 ;
    END
  END Tile_X0Y1_FrameData[14]
  PIN Tile_X0Y1_FrameData[15]
    DIRECTION INPUT ;
    USE SIGNAL ;
    ANTENNAGATEAREA 4.834200 ;
    ANTENNADIFFAREA 2.608200 ;
    PORT
      LAYER met3 ;
        RECT 0.000 175.480 0.600 176.080 ;
    END
  END Tile_X0Y1_FrameData[15]
  PIN Tile_X0Y1_FrameData[16]
    DIRECTION INPUT ;
    USE SIGNAL ;
    ANTENNAGATEAREA 2.226000 ;
    PORT
      LAYER met3 ;
        RECT 0.000 176.840 0.600 177.440 ;
    END
  END Tile_X0Y1_FrameData[16]
  PIN Tile_X0Y1_FrameData[17]
    DIRECTION INPUT ;
    USE SIGNAL ;
    ANTENNAGATEAREA 2.226000 ;
    PORT
      LAYER met3 ;
        RECT 0.000 178.200 0.600 178.800 ;
    END
  END Tile_X0Y1_FrameData[17]
  PIN Tile_X0Y1_FrameData[18]
    DIRECTION INPUT ;
    USE SIGNAL ;
    ANTENNAGATEAREA 2.226000 ;
    PORT
      LAYER met3 ;
        RECT 0.000 179.560 0.600 180.160 ;
    END
  END Tile_X0Y1_FrameData[18]
  PIN Tile_X0Y1_FrameData[19]
    DIRECTION INPUT ;
    USE SIGNAL ;
    ANTENNAGATEAREA 2.226000 ;
    PORT
      LAYER met3 ;
        RECT 0.000 180.920 0.600 181.520 ;
    END
  END Tile_X0Y1_FrameData[19]
  PIN Tile_X0Y1_FrameData[1]
    DIRECTION INPUT ;
    USE SIGNAL ;
    ANTENNAGATEAREA 2.226000 ;
    PORT
      LAYER met3 ;
        RECT 0.000 156.440 0.600 157.040 ;
    END
  END Tile_X0Y1_FrameData[1]
  PIN Tile_X0Y1_FrameData[20]
    DIRECTION INPUT ;
    USE SIGNAL ;
    ANTENNAGATEAREA 2.226000 ;
    PORT
      LAYER met3 ;
        RECT 0.000 182.280 0.600 182.880 ;
    END
  END Tile_X0Y1_FrameData[20]
  PIN Tile_X0Y1_FrameData[21]
    DIRECTION INPUT ;
    USE SIGNAL ;
    ANTENNAGATEAREA 2.226000 ;
    PORT
      LAYER met3 ;
        RECT 0.000 183.640 0.600 184.240 ;
    END
  END Tile_X0Y1_FrameData[21]
  PIN Tile_X0Y1_FrameData[22]
    DIRECTION INPUT ;
    USE SIGNAL ;
    ANTENNAGATEAREA 2.226000 ;
    PORT
      LAYER met3 ;
        RECT 0.000 185.000 0.600 185.600 ;
    END
  END Tile_X0Y1_FrameData[22]
  PIN Tile_X0Y1_FrameData[23]
    DIRECTION INPUT ;
    USE SIGNAL ;
    ANTENNAGATEAREA 2.660700 ;
    ANTENNADIFFAREA 0.434700 ;
    PORT
      LAYER met3 ;
        RECT 0.000 186.360 0.600 186.960 ;
    END
  END Tile_X0Y1_FrameData[23]
  PIN Tile_X0Y1_FrameData[24]
    DIRECTION INPUT ;
    USE SIGNAL ;
    ANTENNAGATEAREA 2.385000 ;
    PORT
      LAYER met3 ;
        RECT 0.000 187.720 0.600 188.320 ;
    END
  END Tile_X0Y1_FrameData[24]
  PIN Tile_X0Y1_FrameData[25]
    DIRECTION INPUT ;
    USE SIGNAL ;
    ANTENNAGATEAREA 2.385000 ;
    PORT
      LAYER met3 ;
        RECT 0.000 189.080 0.600 189.680 ;
    END
  END Tile_X0Y1_FrameData[25]
  PIN Tile_X0Y1_FrameData[26]
    DIRECTION INPUT ;
    USE SIGNAL ;
    ANTENNAGATEAREA 2.385000 ;
    PORT
      LAYER met3 ;
        RECT 0.000 190.440 0.600 191.040 ;
    END
  END Tile_X0Y1_FrameData[26]
  PIN Tile_X0Y1_FrameData[27]
    DIRECTION INPUT ;
    USE SIGNAL ;
    ANTENNAGATEAREA 2.385000 ;
    PORT
      LAYER met3 ;
        RECT 0.000 191.800 0.600 192.400 ;
    END
  END Tile_X0Y1_FrameData[27]
  PIN Tile_X0Y1_FrameData[28]
    DIRECTION INPUT ;
    USE SIGNAL ;
    ANTENNAGATEAREA 4.123800 ;
    ANTENNADIFFAREA 1.738800 ;
    PORT
      LAYER met3 ;
        RECT 0.000 193.160 0.600 193.760 ;
    END
  END Tile_X0Y1_FrameData[28]
  PIN Tile_X0Y1_FrameData[29]
    DIRECTION INPUT ;
    USE SIGNAL ;
    ANTENNAGATEAREA 2.385000 ;
    PORT
      LAYER met3 ;
        RECT 0.000 194.520 0.600 195.120 ;
    END
  END Tile_X0Y1_FrameData[29]
  PIN Tile_X0Y1_FrameData[2]
    DIRECTION INPUT ;
    USE SIGNAL ;
    ANTENNAGATEAREA 2.226000 ;
    PORT
      LAYER met3 ;
        RECT 0.000 157.800 0.600 158.400 ;
    END
  END Tile_X0Y1_FrameData[2]
  PIN Tile_X0Y1_FrameData[30]
    DIRECTION INPUT ;
    USE SIGNAL ;
    ANTENNAGATEAREA 2.385000 ;
    PORT
      LAYER met3 ;
        RECT 0.000 195.880 0.600 196.480 ;
    END
  END Tile_X0Y1_FrameData[30]
  PIN Tile_X0Y1_FrameData[31]
    DIRECTION INPUT ;
    USE SIGNAL ;
    ANTENNAGATEAREA 2.385000 ;
    PORT
      LAYER met3 ;
        RECT 0.000 197.240 0.600 197.840 ;
    END
  END Tile_X0Y1_FrameData[31]
  PIN Tile_X0Y1_FrameData[3]
    DIRECTION INPUT ;
    USE SIGNAL ;
    ANTENNAGATEAREA 2.226000 ;
    PORT
      LAYER met3 ;
        RECT 0.000 159.160 0.600 159.760 ;
    END
  END Tile_X0Y1_FrameData[3]
  PIN Tile_X0Y1_FrameData[4]
    DIRECTION INPUT ;
    USE SIGNAL ;
    ANTENNAGATEAREA 2.226000 ;
    PORT
      LAYER met3 ;
        RECT 0.000 160.520 0.600 161.120 ;
    END
  END Tile_X0Y1_FrameData[4]
  PIN Tile_X0Y1_FrameData[5]
    DIRECTION INPUT ;
    USE SIGNAL ;
    ANTENNAGATEAREA 2.226000 ;
    PORT
      LAYER met3 ;
        RECT 0.000 161.880 0.600 162.480 ;
    END
  END Tile_X0Y1_FrameData[5]
  PIN Tile_X0Y1_FrameData[6]
    DIRECTION INPUT ;
    USE SIGNAL ;
    ANTENNAGATEAREA 3.964800 ;
    ANTENNADIFFAREA 1.738800 ;
    PORT
      LAYER met3 ;
        RECT 0.000 163.240 0.600 163.840 ;
    END
  END Tile_X0Y1_FrameData[6]
  PIN Tile_X0Y1_FrameData[7]
    DIRECTION INPUT ;
    USE SIGNAL ;
    ANTENNAGATEAREA 3.964800 ;
    ANTENNADIFFAREA 1.738800 ;
    PORT
      LAYER met3 ;
        RECT 0.000 164.600 0.600 165.200 ;
    END
  END Tile_X0Y1_FrameData[7]
  PIN Tile_X0Y1_FrameData[8]
    DIRECTION INPUT ;
    USE SIGNAL ;
    ANTENNAGATEAREA 2.226000 ;
    PORT
      LAYER met3 ;
        RECT 0.000 165.960 0.600 166.560 ;
    END
  END Tile_X0Y1_FrameData[8]
  PIN Tile_X0Y1_FrameData[9]
    DIRECTION INPUT ;
    USE SIGNAL ;
    ANTENNAGATEAREA 2.226000 ;
    PORT
      LAYER met3 ;
        RECT 0.000 167.320 0.600 167.920 ;
    END
  END Tile_X0Y1_FrameData[9]
  PIN Tile_X0Y1_FrameData_O[0]
    DIRECTION OUTPUT ;
    USE SIGNAL ;
    ANTENNADIFFAREA 0.702900 ;
    PORT
      LAYER met3 ;
        RECT 219.280 155.080 219.880 155.680 ;
    END
  END Tile_X0Y1_FrameData_O[0]
  PIN Tile_X0Y1_FrameData_O[10]
    DIRECTION OUTPUT ;
    USE SIGNAL ;
    ANTENNADIFFAREA 0.702900 ;
    PORT
      LAYER met3 ;
        RECT 219.280 168.680 219.880 169.280 ;
    END
  END Tile_X0Y1_FrameData_O[10]
  PIN Tile_X0Y1_FrameData_O[11]
    DIRECTION OUTPUT ;
    USE SIGNAL ;
    ANTENNADIFFAREA 0.702900 ;
    PORT
      LAYER met3 ;
        RECT 219.280 170.040 219.880 170.640 ;
    END
  END Tile_X0Y1_FrameData_O[11]
  PIN Tile_X0Y1_FrameData_O[12]
    DIRECTION OUTPUT ;
    USE SIGNAL ;
    ANTENNADIFFAREA 0.702900 ;
    PORT
      LAYER met3 ;
        RECT 219.280 171.400 219.880 172.000 ;
    END
  END Tile_X0Y1_FrameData_O[12]
  PIN Tile_X0Y1_FrameData_O[13]
    DIRECTION OUTPUT ;
    USE SIGNAL ;
    ANTENNADIFFAREA 0.702900 ;
    PORT
      LAYER met3 ;
        RECT 219.280 172.760 219.880 173.360 ;
    END
  END Tile_X0Y1_FrameData_O[13]
  PIN Tile_X0Y1_FrameData_O[14]
    DIRECTION OUTPUT ;
    USE SIGNAL ;
    ANTENNADIFFAREA 0.702900 ;
    PORT
      LAYER met3 ;
        RECT 219.280 174.120 219.880 174.720 ;
    END
  END Tile_X0Y1_FrameData_O[14]
  PIN Tile_X0Y1_FrameData_O[15]
    DIRECTION OUTPUT ;
    USE SIGNAL ;
    ANTENNADIFFAREA 0.702900 ;
    PORT
      LAYER met3 ;
        RECT 219.280 175.480 219.880 176.080 ;
    END
  END Tile_X0Y1_FrameData_O[15]
  PIN Tile_X0Y1_FrameData_O[16]
    DIRECTION OUTPUT ;
    USE SIGNAL ;
    ANTENNADIFFAREA 0.702900 ;
    PORT
      LAYER met3 ;
        RECT 219.280 176.840 219.880 177.440 ;
    END
  END Tile_X0Y1_FrameData_O[16]
  PIN Tile_X0Y1_FrameData_O[17]
    DIRECTION OUTPUT ;
    USE SIGNAL ;
    ANTENNADIFFAREA 0.702900 ;
    PORT
      LAYER met3 ;
        RECT 219.280 178.200 219.880 178.800 ;
    END
  END Tile_X0Y1_FrameData_O[17]
  PIN Tile_X0Y1_FrameData_O[18]
    DIRECTION OUTPUT ;
    USE SIGNAL ;
    ANTENNADIFFAREA 0.702900 ;
    PORT
      LAYER met3 ;
        RECT 219.280 179.560 219.880 180.160 ;
    END
  END Tile_X0Y1_FrameData_O[18]
  PIN Tile_X0Y1_FrameData_O[19]
    DIRECTION OUTPUT ;
    USE SIGNAL ;
    ANTENNADIFFAREA 0.702900 ;
    PORT
      LAYER met3 ;
        RECT 219.280 180.920 219.880 181.520 ;
    END
  END Tile_X0Y1_FrameData_O[19]
  PIN Tile_X0Y1_FrameData_O[1]
    DIRECTION OUTPUT ;
    USE SIGNAL ;
    ANTENNADIFFAREA 0.702900 ;
    PORT
      LAYER met3 ;
        RECT 219.280 156.440 219.880 157.040 ;
    END
  END Tile_X0Y1_FrameData_O[1]
  PIN Tile_X0Y1_FrameData_O[20]
    DIRECTION OUTPUT ;
    USE SIGNAL ;
    ANTENNADIFFAREA 0.702900 ;
    PORT
      LAYER met3 ;
        RECT 219.280 182.280 219.880 182.880 ;
    END
  END Tile_X0Y1_FrameData_O[20]
  PIN Tile_X0Y1_FrameData_O[21]
    DIRECTION OUTPUT ;
    USE SIGNAL ;
    ANTENNADIFFAREA 0.702900 ;
    PORT
      LAYER met3 ;
        RECT 219.280 183.640 219.880 184.240 ;
    END
  END Tile_X0Y1_FrameData_O[21]
  PIN Tile_X0Y1_FrameData_O[22]
    DIRECTION OUTPUT ;
    USE SIGNAL ;
    ANTENNADIFFAREA 0.702900 ;
    PORT
      LAYER met3 ;
        RECT 219.280 185.000 219.880 185.600 ;
    END
  END Tile_X0Y1_FrameData_O[22]
  PIN Tile_X0Y1_FrameData_O[23]
    DIRECTION OUTPUT ;
    USE SIGNAL ;
    ANTENNADIFFAREA 0.702900 ;
    PORT
      LAYER met3 ;
        RECT 219.280 186.360 219.880 186.960 ;
    END
  END Tile_X0Y1_FrameData_O[23]
  PIN Tile_X0Y1_FrameData_O[24]
    DIRECTION OUTPUT ;
    USE SIGNAL ;
    ANTENNADIFFAREA 0.702900 ;
    PORT
      LAYER met3 ;
        RECT 219.280 187.720 219.880 188.320 ;
    END
  END Tile_X0Y1_FrameData_O[24]
  PIN Tile_X0Y1_FrameData_O[25]
    DIRECTION OUTPUT ;
    USE SIGNAL ;
    ANTENNADIFFAREA 0.702900 ;
    PORT
      LAYER met3 ;
        RECT 219.280 189.080 219.880 189.680 ;
    END
  END Tile_X0Y1_FrameData_O[25]
  PIN Tile_X0Y1_FrameData_O[26]
    DIRECTION OUTPUT ;
    USE SIGNAL ;
    ANTENNADIFFAREA 0.702900 ;
    PORT
      LAYER met3 ;
        RECT 219.280 190.440 219.880 191.040 ;
    END
  END Tile_X0Y1_FrameData_O[26]
  PIN Tile_X0Y1_FrameData_O[27]
    DIRECTION OUTPUT ;
    USE SIGNAL ;
    ANTENNADIFFAREA 0.702900 ;
    PORT
      LAYER met3 ;
        RECT 219.280 191.800 219.880 192.400 ;
    END
  END Tile_X0Y1_FrameData_O[27]
  PIN Tile_X0Y1_FrameData_O[28]
    DIRECTION OUTPUT ;
    USE SIGNAL ;
    ANTENNADIFFAREA 0.702900 ;
    PORT
      LAYER met3 ;
        RECT 219.280 193.160 219.880 193.760 ;
    END
  END Tile_X0Y1_FrameData_O[28]
  PIN Tile_X0Y1_FrameData_O[29]
    DIRECTION OUTPUT ;
    USE SIGNAL ;
    ANTENNADIFFAREA 0.702900 ;
    PORT
      LAYER met3 ;
        RECT 219.280 194.520 219.880 195.120 ;
    END
  END Tile_X0Y1_FrameData_O[29]
  PIN Tile_X0Y1_FrameData_O[2]
    DIRECTION OUTPUT ;
    USE SIGNAL ;
    ANTENNADIFFAREA 0.702900 ;
    PORT
      LAYER met3 ;
        RECT 219.280 157.800 219.880 158.400 ;
    END
  END Tile_X0Y1_FrameData_O[2]
  PIN Tile_X0Y1_FrameData_O[30]
    DIRECTION OUTPUT ;
    USE SIGNAL ;
    ANTENNADIFFAREA 0.702900 ;
    PORT
      LAYER met3 ;
        RECT 219.280 195.880 219.880 196.480 ;
    END
  END Tile_X0Y1_FrameData_O[30]
  PIN Tile_X0Y1_FrameData_O[31]
    DIRECTION OUTPUT ;
    USE SIGNAL ;
    ANTENNADIFFAREA 0.702900 ;
    PORT
      LAYER met3 ;
        RECT 219.280 197.240 219.880 197.840 ;
    END
  END Tile_X0Y1_FrameData_O[31]
  PIN Tile_X0Y1_FrameData_O[3]
    DIRECTION OUTPUT ;
    USE SIGNAL ;
    ANTENNADIFFAREA 0.702900 ;
    PORT
      LAYER met3 ;
        RECT 219.280 159.160 219.880 159.760 ;
    END
  END Tile_X0Y1_FrameData_O[3]
  PIN Tile_X0Y1_FrameData_O[4]
    DIRECTION OUTPUT ;
    USE SIGNAL ;
    ANTENNADIFFAREA 0.702900 ;
    PORT
      LAYER met3 ;
        RECT 219.280 160.520 219.880 161.120 ;
    END
  END Tile_X0Y1_FrameData_O[4]
  PIN Tile_X0Y1_FrameData_O[5]
    DIRECTION OUTPUT ;
    USE SIGNAL ;
    ANTENNADIFFAREA 0.702900 ;
    PORT
      LAYER met3 ;
        RECT 219.280 161.880 219.880 162.480 ;
    END
  END Tile_X0Y1_FrameData_O[5]
  PIN Tile_X0Y1_FrameData_O[6]
    DIRECTION OUTPUT ;
    USE SIGNAL ;
    ANTENNADIFFAREA 0.702900 ;
    PORT
      LAYER met3 ;
        RECT 219.280 163.240 219.880 163.840 ;
    END
  END Tile_X0Y1_FrameData_O[6]
  PIN Tile_X0Y1_FrameData_O[7]
    DIRECTION OUTPUT ;
    USE SIGNAL ;
    ANTENNADIFFAREA 0.702900 ;
    PORT
      LAYER met3 ;
        RECT 219.280 164.600 219.880 165.200 ;
    END
  END Tile_X0Y1_FrameData_O[7]
  PIN Tile_X0Y1_FrameData_O[8]
    DIRECTION OUTPUT ;
    USE SIGNAL ;
    ANTENNADIFFAREA 0.702900 ;
    PORT
      LAYER met3 ;
        RECT 219.280 165.960 219.880 166.560 ;
    END
  END Tile_X0Y1_FrameData_O[8]
  PIN Tile_X0Y1_FrameData_O[9]
    DIRECTION OUTPUT ;
    USE SIGNAL ;
    ANTENNADIFFAREA 0.702900 ;
    PORT
      LAYER met3 ;
        RECT 219.280 167.320 219.880 167.920 ;
    END
  END Tile_X0Y1_FrameData_O[9]
  PIN Tile_X0Y1_FrameStrobe[0]
    DIRECTION INPUT ;
    USE SIGNAL ;
    ANTENNAGATEAREA 10.335000 ;
    PORT
      LAYER met2 ;
        RECT 171.670 0.000 171.950 0.280 ;
    END
  END Tile_X0Y1_FrameStrobe[0]
  PIN Tile_X0Y1_FrameStrobe[10]
    DIRECTION INPUT ;
    USE SIGNAL ;
    ANTENNAGATEAREA 10.335000 ;
    PORT
      LAYER met2 ;
        RECT 185.470 0.000 185.750 0.280 ;
    END
  END Tile_X0Y1_FrameStrobe[10]
  PIN Tile_X0Y1_FrameStrobe[11]
    DIRECTION INPUT ;
    USE SIGNAL ;
    ANTENNAGATEAREA 10.335000 ;
    PORT
      LAYER met2 ;
        RECT 186.850 0.000 187.130 0.280 ;
    END
  END Tile_X0Y1_FrameStrobe[11]
  PIN Tile_X0Y1_FrameStrobe[12]
    DIRECTION INPUT ;
    USE SIGNAL ;
    ANTENNAGATEAREA 8.745000 ;
    PORT
      LAYER met2 ;
        RECT 188.230 0.000 188.510 0.280 ;
    END
  END Tile_X0Y1_FrameStrobe[12]
  PIN Tile_X0Y1_FrameStrobe[13]
    DIRECTION INPUT ;
    USE SIGNAL ;
    ANTENNAGATEAREA 1.431000 ;
    PORT
      LAYER met2 ;
        RECT 189.610 0.000 189.890 0.280 ;
    END
  END Tile_X0Y1_FrameStrobe[13]
  PIN Tile_X0Y1_FrameStrobe[14]
    DIRECTION INPUT ;
    USE SIGNAL ;
    ANTENNAGATEAREA 0.159000 ;
    PORT
      LAYER met2 ;
        RECT 190.990 0.000 191.270 0.280 ;
    END
  END Tile_X0Y1_FrameStrobe[14]
  PIN Tile_X0Y1_FrameStrobe[15]
    DIRECTION INPUT ;
    USE SIGNAL ;
    ANTENNAGATEAREA 0.159000 ;
    PORT
      LAYER met2 ;
        RECT 192.370 0.000 192.650 0.280 ;
    END
  END Tile_X0Y1_FrameStrobe[15]
  PIN Tile_X0Y1_FrameStrobe[16]
    DIRECTION INPUT ;
    USE SIGNAL ;
    ANTENNAGATEAREA 0.159000 ;
    PORT
      LAYER met2 ;
        RECT 193.750 0.000 194.030 0.280 ;
    END
  END Tile_X0Y1_FrameStrobe[16]
  PIN Tile_X0Y1_FrameStrobe[17]
    DIRECTION INPUT ;
    USE SIGNAL ;
    ANTENNAGATEAREA 0.159000 ;
    PORT
      LAYER met2 ;
        RECT 195.130 0.000 195.410 0.280 ;
    END
  END Tile_X0Y1_FrameStrobe[17]
  PIN Tile_X0Y1_FrameStrobe[18]
    DIRECTION INPUT ;
    USE SIGNAL ;
    ANTENNAGATEAREA 0.159000 ;
    PORT
      LAYER met2 ;
        RECT 196.510 0.000 196.790 0.280 ;
    END
  END Tile_X0Y1_FrameStrobe[18]
  PIN Tile_X0Y1_FrameStrobe[19]
    DIRECTION INPUT ;
    USE SIGNAL ;
    ANTENNAGATEAREA 0.159000 ;
    PORT
      LAYER met2 ;
        RECT 197.890 0.000 198.170 0.280 ;
    END
  END Tile_X0Y1_FrameStrobe[19]
  PIN Tile_X0Y1_FrameStrobe[1]
    DIRECTION INPUT ;
    USE SIGNAL ;
    ANTENNAGATEAREA 10.335000 ;
    PORT
      LAYER met2 ;
        RECT 173.050 0.000 173.330 0.280 ;
    END
  END Tile_X0Y1_FrameStrobe[1]
  PIN Tile_X0Y1_FrameStrobe[2]
    DIRECTION INPUT ;
    USE SIGNAL ;
    ANTENNAGATEAREA 10.335000 ;
    PORT
      LAYER met2 ;
        RECT 174.430 0.000 174.710 0.280 ;
    END
  END Tile_X0Y1_FrameStrobe[2]
  PIN Tile_X0Y1_FrameStrobe[3]
    DIRECTION INPUT ;
    USE SIGNAL ;
    ANTENNAGATEAREA 10.335000 ;
    PORT
      LAYER met2 ;
        RECT 175.810 0.000 176.090 0.280 ;
    END
  END Tile_X0Y1_FrameStrobe[3]
  PIN Tile_X0Y1_FrameStrobe[4]
    DIRECTION INPUT ;
    USE SIGNAL ;
    ANTENNAGATEAREA 10.335000 ;
    PORT
      LAYER met2 ;
        RECT 177.190 0.000 177.470 0.280 ;
    END
  END Tile_X0Y1_FrameStrobe[4]
  PIN Tile_X0Y1_FrameStrobe[5]
    DIRECTION INPUT ;
    USE SIGNAL ;
    ANTENNAGATEAREA 10.335000 ;
    PORT
      LAYER met2 ;
        RECT 178.570 0.000 178.850 0.280 ;
    END
  END Tile_X0Y1_FrameStrobe[5]
  PIN Tile_X0Y1_FrameStrobe[6]
    DIRECTION INPUT ;
    USE SIGNAL ;
    ANTENNAGATEAREA 10.335000 ;
    PORT
      LAYER met2 ;
        RECT 179.950 0.000 180.230 0.280 ;
    END
  END Tile_X0Y1_FrameStrobe[6]
  PIN Tile_X0Y1_FrameStrobe[7]
    DIRECTION INPUT ;
    USE SIGNAL ;
    ANTENNAGATEAREA 10.335000 ;
    PORT
      LAYER met2 ;
        RECT 181.330 0.000 181.610 0.280 ;
    END
  END Tile_X0Y1_FrameStrobe[7]
  PIN Tile_X0Y1_FrameStrobe[8]
    DIRECTION INPUT ;
    USE SIGNAL ;
    ANTENNAGATEAREA 10.335000 ;
    PORT
      LAYER met2 ;
        RECT 182.710 0.000 182.990 0.280 ;
    END
  END Tile_X0Y1_FrameStrobe[8]
  PIN Tile_X0Y1_FrameStrobe[9]
    DIRECTION INPUT ;
    USE SIGNAL ;
    ANTENNAGATEAREA 10.335000 ;
    PORT
      LAYER met2 ;
        RECT 184.090 0.000 184.370 0.280 ;
    END
  END Tile_X0Y1_FrameStrobe[9]
  PIN Tile_X0Y1_N1END[0]
    DIRECTION INPUT ;
    USE SIGNAL ;
    ANTENNAGATEAREA 3.230100 ;
    ANTENNADIFFAREA 1.304100 ;
    PORT
      LAYER met2 ;
        RECT 26.770 0.000 27.050 0.280 ;
    END
  END Tile_X0Y1_N1END[0]
  PIN Tile_X0Y1_N1END[1]
    DIRECTION INPUT ;
    USE SIGNAL ;
    ANTENNAGATEAREA 1.827000 ;
    PORT
      LAYER met2 ;
        RECT 28.150 0.000 28.430 0.280 ;
    END
  END Tile_X0Y1_N1END[1]
  PIN Tile_X0Y1_N1END[2]
    DIRECTION INPUT ;
    USE SIGNAL ;
    ANTENNAGATEAREA 1.590000 ;
    PORT
      LAYER met2 ;
        RECT 29.530 0.000 29.810 0.280 ;
    END
  END Tile_X0Y1_N1END[2]
  PIN Tile_X0Y1_N1END[3]
    DIRECTION INPUT ;
    USE SIGNAL ;
    ANTENNAGATEAREA 1.958700 ;
    ANTENNADIFFAREA 0.434700 ;
    PORT
      LAYER met2 ;
        RECT 30.910 0.000 31.190 0.280 ;
    END
  END Tile_X0Y1_N1END[3]
  PIN Tile_X0Y1_N2END[0]
    DIRECTION INPUT ;
    USE SIGNAL ;
    ANTENNAGATEAREA 1.113000 ;
    PORT
      LAYER met2 ;
        RECT 43.330 0.000 43.610 0.280 ;
    END
  END Tile_X0Y1_N2END[0]
  PIN Tile_X0Y1_N2END[1]
    DIRECTION INPUT ;
    USE SIGNAL ;
    ANTENNAGATEAREA 0.795000 ;
    PORT
      LAYER met2 ;
        RECT 44.710 0.000 44.990 0.280 ;
    END
  END Tile_X0Y1_N2END[1]
  PIN Tile_X0Y1_N2END[2]
    DIRECTION INPUT ;
    USE SIGNAL ;
    ANTENNAGATEAREA 1.229700 ;
    ANTENNADIFFAREA 0.434700 ;
    PORT
      LAYER met2 ;
        RECT 46.090 0.000 46.370 0.280 ;
    END
  END Tile_X0Y1_N2END[2]
  PIN Tile_X0Y1_N2END[3]
    DIRECTION INPUT ;
    USE SIGNAL ;
    ANTENNAGATEAREA 0.954000 ;
    PORT
      LAYER met2 ;
        RECT 47.470 0.000 47.750 0.280 ;
    END
  END Tile_X0Y1_N2END[3]
  PIN Tile_X0Y1_N2END[4]
    DIRECTION INPUT ;
    USE SIGNAL ;
    ANTENNAGATEAREA 1.823400 ;
    ANTENNADIFFAREA 0.869400 ;
    PORT
      LAYER met2 ;
        RECT 48.850 0.000 49.130 0.280 ;
    END
  END Tile_X0Y1_N2END[4]
  PIN Tile_X0Y1_N2END[5]
    DIRECTION INPUT ;
    USE SIGNAL ;
    ANTENNAGATEAREA 1.229700 ;
    ANTENNADIFFAREA 0.434700 ;
    PORT
      LAYER met2 ;
        RECT 50.230 0.000 50.510 0.280 ;
    END
  END Tile_X0Y1_N2END[5]
  PIN Tile_X0Y1_N2END[6]
    DIRECTION INPUT ;
    USE SIGNAL ;
    ANTENNAGATEAREA 1.664400 ;
    ANTENNADIFFAREA 0.869400 ;
    PORT
      LAYER met2 ;
        RECT 51.610 0.000 51.890 0.280 ;
    END
  END Tile_X0Y1_N2END[6]
  PIN Tile_X0Y1_N2END[7]
    DIRECTION INPUT ;
    USE SIGNAL ;
    ANTENNAGATEAREA 0.954000 ;
    PORT
      LAYER met2 ;
        RECT 52.990 0.000 53.270 0.280 ;
    END
  END Tile_X0Y1_N2END[7]
  PIN Tile_X0Y1_N2MID[0]
    DIRECTION INPUT ;
    USE SIGNAL ;
    ANTENNAGATEAREA 1.728000 ;
    PORT
      LAYER met2 ;
        RECT 32.290 0.000 32.570 0.280 ;
    END
  END Tile_X0Y1_N2MID[0]
  PIN Tile_X0Y1_N2MID[1]
    DIRECTION INPUT ;
    USE SIGNAL ;
    ANTENNAGATEAREA 1.332000 ;
    PORT
      LAYER met2 ;
        RECT 33.670 0.000 33.950 0.280 ;
    END
  END Tile_X0Y1_N2MID[1]
  PIN Tile_X0Y1_N2MID[2]
    DIRECTION INPUT ;
    USE SIGNAL ;
    ANTENNAGATEAREA 5.052600 ;
    ANTENNADIFFAREA 3.477600 ;
    PORT
      LAYER met2 ;
        RECT 35.050 0.000 35.330 0.280 ;
    END
  END Tile_X0Y1_N2MID[2]
  PIN Tile_X0Y1_N2MID[3]
    DIRECTION INPUT ;
    USE SIGNAL ;
    ANTENNAGATEAREA 1.767000 ;
    PORT
      LAYER met2 ;
        RECT 36.430 0.000 36.710 0.280 ;
    END
  END Tile_X0Y1_N2MID[3]
  PIN Tile_X0Y1_N2MID[4]
    DIRECTION INPUT ;
    USE SIGNAL ;
    ANTENNAGATEAREA 1.734000 ;
    PORT
      LAYER met2 ;
        RECT 37.810 0.000 38.090 0.280 ;
    END
  END Tile_X0Y1_N2MID[4]
  PIN Tile_X0Y1_N2MID[5]
    DIRECTION INPUT ;
    USE SIGNAL ;
    ANTENNAGATEAREA 2.583000 ;
    PORT
      LAYER met2 ;
        RECT 39.190 0.000 39.470 0.280 ;
    END
  END Tile_X0Y1_N2MID[5]
  PIN Tile_X0Y1_N2MID[6]
    DIRECTION INPUT ;
    USE SIGNAL ;
    ANTENNAGATEAREA 6.081000 ;
    ANTENNADIFFAREA 4.347000 ;
    PORT
      LAYER met2 ;
        RECT 40.570 0.000 40.850 0.280 ;
    END
  END Tile_X0Y1_N2MID[6]
  PIN Tile_X0Y1_N2MID[7]
    DIRECTION INPUT ;
    USE SIGNAL ;
    ANTENNAGATEAREA 2.327400 ;
    ANTENNADIFFAREA 0.869400 ;
    PORT
      LAYER met2 ;
        RECT 41.950 0.000 42.230 0.280 ;
    END
  END Tile_X0Y1_N2MID[7]
  PIN Tile_X0Y1_N4END[0]
    DIRECTION INPUT ;
    USE SIGNAL ;
    ANTENNAGATEAREA 0.795000 ;
    PORT
      LAYER met2 ;
        RECT 54.370 0.000 54.650 0.280 ;
    END
  END Tile_X0Y1_N4END[0]
  PIN Tile_X0Y1_N4END[10]
    DIRECTION INPUT ;
    USE SIGNAL ;
    ANTENNAGATEAREA 0.159000 ;
    PORT
      LAYER met2 ;
        RECT 68.170 0.000 68.450 0.280 ;
    END
  END Tile_X0Y1_N4END[10]
  PIN Tile_X0Y1_N4END[11]
    DIRECTION INPUT ;
    USE SIGNAL ;
    ANTENNAGATEAREA 0.159000 ;
    PORT
      LAYER met2 ;
        RECT 69.550 0.000 69.830 0.280 ;
    END
  END Tile_X0Y1_N4END[11]
  PIN Tile_X0Y1_N4END[12]
    DIRECTION INPUT ;
    USE SIGNAL ;
    ANTENNAGATEAREA 0.159000 ;
    PORT
      LAYER met2 ;
        RECT 70.930 0.000 71.210 0.280 ;
    END
  END Tile_X0Y1_N4END[12]
  PIN Tile_X0Y1_N4END[13]
    DIRECTION INPUT ;
    USE SIGNAL ;
    ANTENNAGATEAREA 0.159000 ;
    PORT
      LAYER met2 ;
        RECT 72.310 0.000 72.590 0.280 ;
    END
  END Tile_X0Y1_N4END[13]
  PIN Tile_X0Y1_N4END[14]
    DIRECTION INPUT ;
    USE SIGNAL ;
    ANTENNAGATEAREA 0.159000 ;
    PORT
      LAYER met2 ;
        RECT 73.690 0.000 73.970 0.280 ;
    END
  END Tile_X0Y1_N4END[14]
  PIN Tile_X0Y1_N4END[15]
    DIRECTION INPUT ;
    USE SIGNAL ;
    ANTENNAGATEAREA 0.159000 ;
    PORT
      LAYER met2 ;
        RECT 75.070 0.000 75.350 0.280 ;
    END
  END Tile_X0Y1_N4END[15]
  PIN Tile_X0Y1_N4END[1]
    DIRECTION INPUT ;
    USE SIGNAL ;
    ANTENNAGATEAREA 1.229700 ;
    ANTENNADIFFAREA 0.434700 ;
    PORT
      LAYER met2 ;
        RECT 55.750 0.000 56.030 0.280 ;
    END
  END Tile_X0Y1_N4END[1]
  PIN Tile_X0Y1_N4END[2]
    DIRECTION INPUT ;
    USE SIGNAL ;
    ANTENNAGATEAREA 0.762000 ;
    PORT
      LAYER met2 ;
        RECT 57.130 0.000 57.410 0.280 ;
    END
  END Tile_X0Y1_N4END[2]
  PIN Tile_X0Y1_N4END[3]
    DIRECTION INPUT ;
    USE SIGNAL ;
    ANTENNAGATEAREA 2.902500 ;
    ANTENNADIFFAREA 2.173500 ;
    PORT
      LAYER met2 ;
        RECT 58.510 0.000 58.790 0.280 ;
    END
  END Tile_X0Y1_N4END[3]
  PIN Tile_X0Y1_N4END[4]
    DIRECTION INPUT ;
    USE SIGNAL ;
    ANTENNAGATEAREA 2.968500 ;
    ANTENNADIFFAREA 2.173500 ;
    PORT
      LAYER met2 ;
        RECT 59.890 0.000 60.170 0.280 ;
    END
  END Tile_X0Y1_N4END[4]
  PIN Tile_X0Y1_N4END[5]
    DIRECTION INPUT ;
    USE SIGNAL ;
    ANTENNAGATEAREA 2.968500 ;
    ANTENNADIFFAREA 2.173500 ;
    PORT
      LAYER met2 ;
        RECT 61.270 0.000 61.550 0.280 ;
    END
  END Tile_X0Y1_N4END[5]
  PIN Tile_X0Y1_N4END[6]
    DIRECTION INPUT ;
    USE SIGNAL ;
    ANTENNAGATEAREA 3.024000 ;
    ANTENNADIFFAREA 2.173500 ;
    PORT
      LAYER met2 ;
        RECT 62.650 0.000 62.930 0.280 ;
    END
  END Tile_X0Y1_N4END[6]
  PIN Tile_X0Y1_N4END[7]
    DIRECTION INPUT ;
    USE SIGNAL ;
    ANTENNAGATEAREA 2.869500 ;
    ANTENNADIFFAREA 2.173500 ;
    PORT
      LAYER met2 ;
        RECT 64.030 0.000 64.310 0.280 ;
    END
  END Tile_X0Y1_N4END[7]
  PIN Tile_X0Y1_N4END[8]
    DIRECTION INPUT ;
    USE SIGNAL ;
    ANTENNAGATEAREA 0.159000 ;
    PORT
      LAYER met2 ;
        RECT 65.410 0.000 65.690 0.280 ;
    END
  END Tile_X0Y1_N4END[8]
  PIN Tile_X0Y1_N4END[9]
    DIRECTION INPUT ;
    USE SIGNAL ;
    ANTENNAGATEAREA 0.159000 ;
    PORT
      LAYER met2 ;
        RECT 66.790 0.000 67.070 0.280 ;
    END
  END Tile_X0Y1_N4END[9]
  PIN Tile_X0Y1_NN4END[0]
    DIRECTION INPUT ;
    USE SIGNAL ;
    ANTENNAGATEAREA 0.318000 ;
    PORT
      LAYER met2 ;
        RECT 76.450 0.000 76.730 0.280 ;
    END
  END Tile_X0Y1_NN4END[0]
  PIN Tile_X0Y1_NN4END[10]
    DIRECTION INPUT ;
    USE SIGNAL ;
    ANTENNAGATEAREA 0.159000 ;
    PORT
      LAYER met2 ;
        RECT 90.250 0.000 90.530 0.280 ;
    END
  END Tile_X0Y1_NN4END[10]
  PIN Tile_X0Y1_NN4END[11]
    DIRECTION INPUT ;
    USE SIGNAL ;
    ANTENNAGATEAREA 0.159000 ;
    PORT
      LAYER met2 ;
        RECT 91.630 0.000 91.910 0.280 ;
    END
  END Tile_X0Y1_NN4END[11]
  PIN Tile_X0Y1_NN4END[12]
    DIRECTION INPUT ;
    USE SIGNAL ;
    ANTENNAGATEAREA 4.940700 ;
    ANTENNADIFFAREA 4.781700 ;
    PORT
      LAYER met2 ;
        RECT 93.010 0.000 93.290 0.280 ;
    END
  END Tile_X0Y1_NN4END[12]
  PIN Tile_X0Y1_NN4END[13]
    DIRECTION INPUT ;
    USE SIGNAL ;
    ANTENNAGATEAREA 0.159000 ;
    PORT
      LAYER met2 ;
        RECT 94.390 0.000 94.670 0.280 ;
    END
  END Tile_X0Y1_NN4END[13]
  PIN Tile_X0Y1_NN4END[14]
    DIRECTION INPUT ;
    USE SIGNAL ;
    ANTENNAGATEAREA 4.940700 ;
    ANTENNADIFFAREA 4.781700 ;
    PORT
      LAYER met2 ;
        RECT 95.770 0.000 96.050 0.280 ;
    END
  END Tile_X0Y1_NN4END[14]
  PIN Tile_X0Y1_NN4END[15]
    DIRECTION INPUT ;
    USE SIGNAL ;
    ANTENNAGATEAREA 0.593700 ;
    ANTENNADIFFAREA 0.434700 ;
    PORT
      LAYER met2 ;
        RECT 97.150 0.000 97.430 0.280 ;
    END
  END Tile_X0Y1_NN4END[15]
  PIN Tile_X0Y1_NN4END[1]
    DIRECTION INPUT ;
    USE SIGNAL ;
    ANTENNAGATEAREA 0.477000 ;
    PORT
      LAYER met2 ;
        RECT 77.830 0.000 78.110 0.280 ;
    END
  END Tile_X0Y1_NN4END[1]
  PIN Tile_X0Y1_NN4END[2]
    DIRECTION INPUT ;
    USE SIGNAL ;
    ANTENNAGATEAREA 0.444000 ;
    PORT
      LAYER met2 ;
        RECT 79.210 0.000 79.490 0.280 ;
    END
  END Tile_X0Y1_NN4END[2]
  PIN Tile_X0Y1_NN4END[3]
    DIRECTION INPUT ;
    USE SIGNAL ;
    ANTENNAGATEAREA 1.247700 ;
    ANTENNADIFFAREA 0.434700 ;
    PORT
      LAYER met2 ;
        RECT 80.590 0.000 80.870 0.280 ;
    END
  END Tile_X0Y1_NN4END[3]
  PIN Tile_X0Y1_NN4END[4]
    DIRECTION INPUT ;
    USE SIGNAL ;
    ANTENNAGATEAREA 1.154400 ;
    ANTENNADIFFAREA 0.869400 ;
    PORT
      LAYER met2 ;
        RECT 81.970 0.000 82.250 0.280 ;
    END
  END Tile_X0Y1_NN4END[4]
  PIN Tile_X0Y1_NN4END[5]
    DIRECTION INPUT ;
    USE SIGNAL ;
    ANTENNAGATEAREA 1.781100 ;
    ANTENNADIFFAREA 1.304100 ;
    PORT
      LAYER met2 ;
        RECT 83.350 0.000 83.630 0.280 ;
    END
  END Tile_X0Y1_NN4END[5]
  PIN Tile_X0Y1_NN4END[6]
    DIRECTION INPUT ;
    USE SIGNAL ;
    ANTENNAGATEAREA 1.781100 ;
    ANTENNADIFFAREA 1.304100 ;
    PORT
      LAYER met2 ;
        RECT 84.730 0.000 85.010 0.280 ;
    END
  END Tile_X0Y1_NN4END[6]
  PIN Tile_X0Y1_NN4END[7]
    DIRECTION INPUT ;
    USE SIGNAL ;
    ANTENNAGATEAREA 1.781100 ;
    ANTENNADIFFAREA 1.304100 ;
    PORT
      LAYER met2 ;
        RECT 86.110 0.000 86.390 0.280 ;
    END
  END Tile_X0Y1_NN4END[7]
  PIN Tile_X0Y1_NN4END[8]
    DIRECTION INPUT ;
    USE SIGNAL ;
    ANTENNAGATEAREA 0.159000 ;
    PORT
      LAYER met2 ;
        RECT 87.490 0.000 87.770 0.280 ;
    END
  END Tile_X0Y1_NN4END[8]
  PIN Tile_X0Y1_NN4END[9]
    DIRECTION INPUT ;
    USE SIGNAL ;
    ANTENNAGATEAREA 0.159000 ;
    PORT
      LAYER met2 ;
        RECT 88.870 0.000 89.150 0.280 ;
    END
  END Tile_X0Y1_NN4END[9]
  PIN Tile_X0Y1_N_GBUF_END[0]
    DIRECTION INPUT ;
    USE SIGNAL ;
    ANTENNAGATEAREA 0.852000 ;
    PORT
      LAYER met2 ;
        RECT 21.250 0.000 21.530 0.280 ;
    END
  END Tile_X0Y1_N_GBUF_END[0]
  PIN Tile_X0Y1_N_GBUF_END[1]
    DIRECTION INPUT ;
    USE SIGNAL ;
    ANTENNAGATEAREA 1.187400 ;
    ANTENNADIFFAREA 0.869400 ;
    PORT
      LAYER met2 ;
        RECT 22.630 0.000 22.910 0.280 ;
    END
  END Tile_X0Y1_N_GBUF_END[1]
  PIN Tile_X0Y1_N_GBUF_END[2]
    DIRECTION INPUT ;
    USE SIGNAL ;
    ANTENNAGATEAREA 1.187400 ;
    ANTENNADIFFAREA 0.869400 ;
    PORT
      LAYER met2 ;
        RECT 24.010 0.000 24.290 0.280 ;
    END
  END Tile_X0Y1_N_GBUF_END[2]
  PIN Tile_X0Y1_N_GBUF_END[3]
    DIRECTION INPUT ;
    USE SIGNAL ;
    ANTENNAGATEAREA 1.187400 ;
    ANTENNADIFFAREA 0.869400 ;
    PORT
      LAYER met2 ;
        RECT 25.390 0.000 25.670 0.280 ;
    END
  END Tile_X0Y1_N_GBUF_END[3]
  PIN Tile_X0Y1_S1BEG[0]
    DIRECTION OUTPUT ;
    USE SIGNAL ;
    ANTENNADIFFAREA 0.702900 ;
    PORT
      LAYER met2 ;
        RECT 99.910 0.000 100.190 0.280 ;
    END
  END Tile_X0Y1_S1BEG[0]
  PIN Tile_X0Y1_S1BEG[1]
    DIRECTION OUTPUT ;
    USE SIGNAL ;
    ANTENNADIFFAREA 0.702900 ;
    PORT
      LAYER met2 ;
        RECT 101.290 0.000 101.570 0.280 ;
    END
  END Tile_X0Y1_S1BEG[1]
  PIN Tile_X0Y1_S1BEG[2]
    DIRECTION OUTPUT ;
    USE SIGNAL ;
    ANTENNADIFFAREA 0.702900 ;
    PORT
      LAYER met2 ;
        RECT 102.670 0.000 102.950 0.280 ;
    END
  END Tile_X0Y1_S1BEG[2]
  PIN Tile_X0Y1_S1BEG[3]
    DIRECTION OUTPUT ;
    USE SIGNAL ;
    ANTENNADIFFAREA 0.702900 ;
    PORT
      LAYER met2 ;
        RECT 104.050 0.000 104.330 0.280 ;
    END
  END Tile_X0Y1_S1BEG[3]
  PIN Tile_X0Y1_S2BEG[0]
    DIRECTION OUTPUT ;
    USE SIGNAL ;
    ANTENNADIFFAREA 0.702900 ;
    PORT
      LAYER met2 ;
        RECT 105.430 0.000 105.710 0.280 ;
    END
  END Tile_X0Y1_S2BEG[0]
  PIN Tile_X0Y1_S2BEG[1]
    DIRECTION OUTPUT ;
    USE SIGNAL ;
    ANTENNADIFFAREA 0.702900 ;
    PORT
      LAYER met2 ;
        RECT 106.810 0.000 107.090 0.280 ;
    END
  END Tile_X0Y1_S2BEG[1]
  PIN Tile_X0Y1_S2BEG[2]
    DIRECTION OUTPUT ;
    USE SIGNAL ;
    ANTENNADIFFAREA 0.702900 ;
    PORT
      LAYER met2 ;
        RECT 108.190 0.000 108.470 0.280 ;
    END
  END Tile_X0Y1_S2BEG[2]
  PIN Tile_X0Y1_S2BEG[3]
    DIRECTION OUTPUT ;
    USE SIGNAL ;
    ANTENNADIFFAREA 0.702900 ;
    PORT
      LAYER met2 ;
        RECT 109.570 0.000 109.850 0.280 ;
    END
  END Tile_X0Y1_S2BEG[3]
  PIN Tile_X0Y1_S2BEG[4]
    DIRECTION OUTPUT ;
    USE SIGNAL ;
    ANTENNADIFFAREA 0.702900 ;
    PORT
      LAYER met2 ;
        RECT 110.950 0.000 111.230 0.280 ;
    END
  END Tile_X0Y1_S2BEG[4]
  PIN Tile_X0Y1_S2BEG[5]
    DIRECTION OUTPUT ;
    USE SIGNAL ;
    ANTENNADIFFAREA 0.702900 ;
    PORT
      LAYER met2 ;
        RECT 112.330 0.000 112.610 0.280 ;
    END
  END Tile_X0Y1_S2BEG[5]
  PIN Tile_X0Y1_S2BEG[6]
    DIRECTION OUTPUT ;
    USE SIGNAL ;
    ANTENNADIFFAREA 0.702900 ;
    PORT
      LAYER met2 ;
        RECT 113.710 0.000 113.990 0.280 ;
    END
  END Tile_X0Y1_S2BEG[6]
  PIN Tile_X0Y1_S2BEG[7]
    DIRECTION OUTPUT ;
    USE SIGNAL ;
    ANTENNADIFFAREA 0.702900 ;
    PORT
      LAYER met2 ;
        RECT 115.090 0.000 115.370 0.280 ;
    END
  END Tile_X0Y1_S2BEG[7]
  PIN Tile_X0Y1_S2BEGb[0]
    DIRECTION OUTPUT ;
    USE SIGNAL ;
    ANTENNADIFFAREA 0.702900 ;
    PORT
      LAYER met2 ;
        RECT 116.470 0.000 116.750 0.280 ;
    END
  END Tile_X0Y1_S2BEGb[0]
  PIN Tile_X0Y1_S2BEGb[1]
    DIRECTION OUTPUT ;
    USE SIGNAL ;
    ANTENNADIFFAREA 0.702900 ;
    PORT
      LAYER met2 ;
        RECT 117.850 0.000 118.130 0.280 ;
    END
  END Tile_X0Y1_S2BEGb[1]
  PIN Tile_X0Y1_S2BEGb[2]
    DIRECTION OUTPUT ;
    USE SIGNAL ;
    ANTENNADIFFAREA 0.702900 ;
    PORT
      LAYER met2 ;
        RECT 119.230 0.000 119.510 0.280 ;
    END
  END Tile_X0Y1_S2BEGb[2]
  PIN Tile_X0Y1_S2BEGb[3]
    DIRECTION OUTPUT ;
    USE SIGNAL ;
    ANTENNADIFFAREA 0.702900 ;
    PORT
      LAYER met2 ;
        RECT 120.610 0.000 120.890 0.280 ;
    END
  END Tile_X0Y1_S2BEGb[3]
  PIN Tile_X0Y1_S2BEGb[4]
    DIRECTION OUTPUT ;
    USE SIGNAL ;
    ANTENNADIFFAREA 0.702900 ;
    PORT
      LAYER met2 ;
        RECT 121.990 0.000 122.270 0.280 ;
    END
  END Tile_X0Y1_S2BEGb[4]
  PIN Tile_X0Y1_S2BEGb[5]
    DIRECTION OUTPUT ;
    USE SIGNAL ;
    ANTENNADIFFAREA 0.702900 ;
    PORT
      LAYER met2 ;
        RECT 123.370 0.000 123.650 0.280 ;
    END
  END Tile_X0Y1_S2BEGb[5]
  PIN Tile_X0Y1_S2BEGb[6]
    DIRECTION OUTPUT ;
    USE SIGNAL ;
    ANTENNADIFFAREA 0.702900 ;
    PORT
      LAYER met2 ;
        RECT 124.750 0.000 125.030 0.280 ;
    END
  END Tile_X0Y1_S2BEGb[6]
  PIN Tile_X0Y1_S2BEGb[7]
    DIRECTION OUTPUT ;
    USE SIGNAL ;
    ANTENNADIFFAREA 0.702900 ;
    PORT
      LAYER met2 ;
        RECT 126.130 0.000 126.410 0.280 ;
    END
  END Tile_X0Y1_S2BEGb[7]
  PIN Tile_X0Y1_S4BEG[0]
    DIRECTION OUTPUT ;
    USE SIGNAL ;
    ANTENNADIFFAREA 0.702900 ;
    PORT
      LAYER met2 ;
        RECT 127.510 0.000 127.790 0.280 ;
    END
  END Tile_X0Y1_S4BEG[0]
  PIN Tile_X0Y1_S4BEG[10]
    DIRECTION OUTPUT ;
    USE SIGNAL ;
    ANTENNADIFFAREA 0.702900 ;
    PORT
      LAYER met2 ;
        RECT 141.310 0.000 141.590 0.280 ;
    END
  END Tile_X0Y1_S4BEG[10]
  PIN Tile_X0Y1_S4BEG[11]
    DIRECTION OUTPUT ;
    USE SIGNAL ;
    ANTENNADIFFAREA 0.702900 ;
    PORT
      LAYER met2 ;
        RECT 142.690 0.000 142.970 0.280 ;
    END
  END Tile_X0Y1_S4BEG[11]
  PIN Tile_X0Y1_S4BEG[12]
    DIRECTION OUTPUT ;
    USE SIGNAL ;
    ANTENNADIFFAREA 0.702900 ;
    PORT
      LAYER met2 ;
        RECT 144.070 0.000 144.350 0.280 ;
    END
  END Tile_X0Y1_S4BEG[12]
  PIN Tile_X0Y1_S4BEG[13]
    DIRECTION OUTPUT ;
    USE SIGNAL ;
    ANTENNADIFFAREA 0.702900 ;
    PORT
      LAYER met2 ;
        RECT 145.450 0.000 145.730 0.280 ;
    END
  END Tile_X0Y1_S4BEG[13]
  PIN Tile_X0Y1_S4BEG[14]
    DIRECTION OUTPUT ;
    USE SIGNAL ;
    ANTENNADIFFAREA 0.702900 ;
    PORT
      LAYER met2 ;
        RECT 146.830 0.000 147.110 0.280 ;
    END
  END Tile_X0Y1_S4BEG[14]
  PIN Tile_X0Y1_S4BEG[15]
    DIRECTION OUTPUT ;
    USE SIGNAL ;
    ANTENNADIFFAREA 0.702900 ;
    PORT
      LAYER met2 ;
        RECT 148.210 0.000 148.490 0.280 ;
    END
  END Tile_X0Y1_S4BEG[15]
  PIN Tile_X0Y1_S4BEG[1]
    DIRECTION OUTPUT ;
    USE SIGNAL ;
    ANTENNADIFFAREA 0.702900 ;
    PORT
      LAYER met2 ;
        RECT 128.890 0.000 129.170 0.280 ;
    END
  END Tile_X0Y1_S4BEG[1]
  PIN Tile_X0Y1_S4BEG[2]
    DIRECTION OUTPUT ;
    USE SIGNAL ;
    ANTENNADIFFAREA 0.702900 ;
    PORT
      LAYER met2 ;
        RECT 130.270 0.000 130.550 0.280 ;
    END
  END Tile_X0Y1_S4BEG[2]
  PIN Tile_X0Y1_S4BEG[3]
    DIRECTION OUTPUT ;
    USE SIGNAL ;
    ANTENNADIFFAREA 0.702900 ;
    PORT
      LAYER met2 ;
        RECT 131.650 0.000 131.930 0.280 ;
    END
  END Tile_X0Y1_S4BEG[3]
  PIN Tile_X0Y1_S4BEG[4]
    DIRECTION OUTPUT ;
    USE SIGNAL ;
    ANTENNADIFFAREA 0.702900 ;
    PORT
      LAYER met2 ;
        RECT 133.030 0.000 133.310 0.280 ;
    END
  END Tile_X0Y1_S4BEG[4]
  PIN Tile_X0Y1_S4BEG[5]
    DIRECTION OUTPUT ;
    USE SIGNAL ;
    ANTENNADIFFAREA 0.702900 ;
    PORT
      LAYER met2 ;
        RECT 134.410 0.000 134.690 0.280 ;
    END
  END Tile_X0Y1_S4BEG[5]
  PIN Tile_X0Y1_S4BEG[6]
    DIRECTION OUTPUT ;
    USE SIGNAL ;
    ANTENNADIFFAREA 0.702900 ;
    PORT
      LAYER met2 ;
        RECT 135.790 0.000 136.070 0.280 ;
    END
  END Tile_X0Y1_S4BEG[6]
  PIN Tile_X0Y1_S4BEG[7]
    DIRECTION OUTPUT ;
    USE SIGNAL ;
    ANTENNADIFFAREA 0.702900 ;
    PORT
      LAYER met2 ;
        RECT 137.170 0.000 137.450 0.280 ;
    END
  END Tile_X0Y1_S4BEG[7]
  PIN Tile_X0Y1_S4BEG[8]
    DIRECTION OUTPUT ;
    USE SIGNAL ;
    ANTENNADIFFAREA 0.702900 ;
    PORT
      LAYER met2 ;
        RECT 138.550 0.000 138.830 0.280 ;
    END
  END Tile_X0Y1_S4BEG[8]
  PIN Tile_X0Y1_S4BEG[9]
    DIRECTION OUTPUT ;
    USE SIGNAL ;
    ANTENNADIFFAREA 0.702900 ;
    PORT
      LAYER met2 ;
        RECT 139.930 0.000 140.210 0.280 ;
    END
  END Tile_X0Y1_S4BEG[9]
  PIN Tile_X0Y1_SS4BEG[0]
    DIRECTION OUTPUT ;
    USE SIGNAL ;
    ANTENNADIFFAREA 0.702900 ;
    PORT
      LAYER met2 ;
        RECT 149.590 0.000 149.870 0.280 ;
    END
  END Tile_X0Y1_SS4BEG[0]
  PIN Tile_X0Y1_SS4BEG[10]
    DIRECTION OUTPUT ;
    USE SIGNAL ;
    ANTENNADIFFAREA 0.702900 ;
    PORT
      LAYER met2 ;
        RECT 163.390 0.000 163.670 0.280 ;
    END
  END Tile_X0Y1_SS4BEG[10]
  PIN Tile_X0Y1_SS4BEG[11]
    DIRECTION OUTPUT ;
    USE SIGNAL ;
    ANTENNADIFFAREA 0.702900 ;
    PORT
      LAYER met2 ;
        RECT 164.770 0.000 165.050 0.280 ;
    END
  END Tile_X0Y1_SS4BEG[11]
  PIN Tile_X0Y1_SS4BEG[12]
    DIRECTION OUTPUT ;
    USE SIGNAL ;
    ANTENNADIFFAREA 0.702900 ;
    PORT
      LAYER met2 ;
        RECT 166.150 0.000 166.430 0.280 ;
    END
  END Tile_X0Y1_SS4BEG[12]
  PIN Tile_X0Y1_SS4BEG[13]
    DIRECTION OUTPUT ;
    USE SIGNAL ;
    ANTENNADIFFAREA 0.702900 ;
    PORT
      LAYER met2 ;
        RECT 167.530 0.000 167.810 0.280 ;
    END
  END Tile_X0Y1_SS4BEG[13]
  PIN Tile_X0Y1_SS4BEG[14]
    DIRECTION OUTPUT ;
    USE SIGNAL ;
    ANTENNADIFFAREA 0.702900 ;
    PORT
      LAYER met2 ;
        RECT 168.910 0.000 169.190 0.280 ;
    END
  END Tile_X0Y1_SS4BEG[14]
  PIN Tile_X0Y1_SS4BEG[15]
    DIRECTION OUTPUT ;
    USE SIGNAL ;
    ANTENNADIFFAREA 0.702900 ;
    PORT
      LAYER met2 ;
        RECT 170.290 0.000 170.570 0.280 ;
    END
  END Tile_X0Y1_SS4BEG[15]
  PIN Tile_X0Y1_SS4BEG[1]
    DIRECTION OUTPUT ;
    USE SIGNAL ;
    ANTENNADIFFAREA 0.702900 ;
    PORT
      LAYER met2 ;
        RECT 150.970 0.000 151.250 0.280 ;
    END
  END Tile_X0Y1_SS4BEG[1]
  PIN Tile_X0Y1_SS4BEG[2]
    DIRECTION OUTPUT ;
    USE SIGNAL ;
    ANTENNADIFFAREA 0.702900 ;
    PORT
      LAYER met2 ;
        RECT 152.350 0.000 152.630 0.280 ;
    END
  END Tile_X0Y1_SS4BEG[2]
  PIN Tile_X0Y1_SS4BEG[3]
    DIRECTION OUTPUT ;
    USE SIGNAL ;
    ANTENNADIFFAREA 0.702900 ;
    PORT
      LAYER met2 ;
        RECT 153.730 0.000 154.010 0.280 ;
    END
  END Tile_X0Y1_SS4BEG[3]
  PIN Tile_X0Y1_SS4BEG[4]
    DIRECTION OUTPUT ;
    USE SIGNAL ;
    ANTENNADIFFAREA 0.702900 ;
    PORT
      LAYER met2 ;
        RECT 155.110 0.000 155.390 0.280 ;
    END
  END Tile_X0Y1_SS4BEG[4]
  PIN Tile_X0Y1_SS4BEG[5]
    DIRECTION OUTPUT ;
    USE SIGNAL ;
    ANTENNADIFFAREA 0.702900 ;
    PORT
      LAYER met2 ;
        RECT 156.490 0.000 156.770 0.280 ;
    END
  END Tile_X0Y1_SS4BEG[5]
  PIN Tile_X0Y1_SS4BEG[6]
    DIRECTION OUTPUT ;
    USE SIGNAL ;
    ANTENNADIFFAREA 0.702900 ;
    PORT
      LAYER met2 ;
        RECT 157.870 0.000 158.150 0.280 ;
    END
  END Tile_X0Y1_SS4BEG[6]
  PIN Tile_X0Y1_SS4BEG[7]
    DIRECTION OUTPUT ;
    USE SIGNAL ;
    ANTENNADIFFAREA 0.702900 ;
    PORT
      LAYER met2 ;
        RECT 159.250 0.000 159.530 0.280 ;
    END
  END Tile_X0Y1_SS4BEG[7]
  PIN Tile_X0Y1_SS4BEG[8]
    DIRECTION OUTPUT ;
    USE SIGNAL ;
    ANTENNADIFFAREA 0.702900 ;
    PORT
      LAYER met2 ;
        RECT 160.630 0.000 160.910 0.280 ;
    END
  END Tile_X0Y1_SS4BEG[8]
  PIN Tile_X0Y1_SS4BEG[9]
    DIRECTION OUTPUT ;
    USE SIGNAL ;
    ANTENNADIFFAREA 0.702900 ;
    PORT
      LAYER met2 ;
        RECT 162.010 0.000 162.290 0.280 ;
    END
  END Tile_X0Y1_SS4BEG[9]
  PIN Tile_X0Y1_W1BEG[0]
    DIRECTION OUTPUT ;
    USE SIGNAL ;
    ANTENNADIFFAREA 0.702900 ;
    PORT
      LAYER met3 ;
        RECT 0.000 24.520 0.600 25.120 ;
    END
  END Tile_X0Y1_W1BEG[0]
  PIN Tile_X0Y1_W1BEG[1]
    DIRECTION OUTPUT ;
    USE SIGNAL ;
    ANTENNADIFFAREA 0.702900 ;
    PORT
      LAYER met3 ;
        RECT 0.000 25.880 0.600 26.480 ;
    END
  END Tile_X0Y1_W1BEG[1]
  PIN Tile_X0Y1_W1BEG[2]
    DIRECTION OUTPUT ;
    USE SIGNAL ;
    ANTENNADIFFAREA 0.702900 ;
    PORT
      LAYER met3 ;
        RECT 0.000 27.240 0.600 27.840 ;
    END
  END Tile_X0Y1_W1BEG[2]
  PIN Tile_X0Y1_W1BEG[3]
    DIRECTION OUTPUT ;
    USE SIGNAL ;
    ANTENNADIFFAREA 0.702900 ;
    PORT
      LAYER met3 ;
        RECT 0.000 28.600 0.600 29.200 ;
    END
  END Tile_X0Y1_W1BEG[3]
  PIN Tile_X0Y1_W1END[0]
    DIRECTION INPUT ;
    USE SIGNAL ;
    ANTENNAGATEAREA 1.476000 ;
    PORT
      LAYER met3 ;
        RECT 219.280 24.520 219.880 25.120 ;
    END
  END Tile_X0Y1_W1END[0]
  PIN Tile_X0Y1_W1END[1]
    DIRECTION INPUT ;
    USE SIGNAL ;
    ANTENNAGATEAREA 1.568700 ;
    ANTENNADIFFAREA 0.434700 ;
    PORT
      LAYER met3 ;
        RECT 219.280 25.880 219.880 26.480 ;
    END
  END Tile_X0Y1_W1END[1]
  PIN Tile_X0Y1_W1END[2]
    DIRECTION INPUT ;
    USE SIGNAL ;
    ANTENNAGATEAREA 2.037000 ;
    PORT
      LAYER met3 ;
        RECT 219.280 27.240 219.880 27.840 ;
    END
  END Tile_X0Y1_W1END[2]
  PIN Tile_X0Y1_W1END[3]
    DIRECTION INPUT ;
    USE SIGNAL ;
    ANTENNAGATEAREA 1.975500 ;
    PORT
      LAYER met3 ;
        RECT 219.280 28.600 219.880 29.200 ;
    END
  END Tile_X0Y1_W1END[3]
  PIN Tile_X0Y1_W2BEG[0]
    DIRECTION OUTPUT ;
    USE SIGNAL ;
    ANTENNADIFFAREA 0.702900 ;
    PORT
      LAYER met3 ;
        RECT 0.000 29.960 0.600 30.560 ;
    END
  END Tile_X0Y1_W2BEG[0]
  PIN Tile_X0Y1_W2BEG[1]
    DIRECTION OUTPUT ;
    USE SIGNAL ;
    ANTENNADIFFAREA 0.702900 ;
    PORT
      LAYER met3 ;
        RECT 0.000 31.320 0.600 31.920 ;
    END
  END Tile_X0Y1_W2BEG[1]
  PIN Tile_X0Y1_W2BEG[2]
    DIRECTION OUTPUT ;
    USE SIGNAL ;
    ANTENNADIFFAREA 0.702900 ;
    PORT
      LAYER met3 ;
        RECT 0.000 32.680 0.600 33.280 ;
    END
  END Tile_X0Y1_W2BEG[2]
  PIN Tile_X0Y1_W2BEG[3]
    DIRECTION OUTPUT ;
    USE SIGNAL ;
    ANTENNADIFFAREA 0.702900 ;
    PORT
      LAYER met3 ;
        RECT 0.000 34.040 0.600 34.640 ;
    END
  END Tile_X0Y1_W2BEG[3]
  PIN Tile_X0Y1_W2BEG[4]
    DIRECTION OUTPUT ;
    USE SIGNAL ;
    ANTENNADIFFAREA 0.702900 ;
    PORT
      LAYER met3 ;
        RECT 0.000 35.400 0.600 36.000 ;
    END
  END Tile_X0Y1_W2BEG[4]
  PIN Tile_X0Y1_W2BEG[5]
    DIRECTION OUTPUT ;
    USE SIGNAL ;
    ANTENNADIFFAREA 0.702900 ;
    PORT
      LAYER met3 ;
        RECT 0.000 36.760 0.600 37.360 ;
    END
  END Tile_X0Y1_W2BEG[5]
  PIN Tile_X0Y1_W2BEG[6]
    DIRECTION OUTPUT ;
    USE SIGNAL ;
    ANTENNADIFFAREA 0.702900 ;
    PORT
      LAYER met3 ;
        RECT 0.000 38.120 0.600 38.720 ;
    END
  END Tile_X0Y1_W2BEG[6]
  PIN Tile_X0Y1_W2BEG[7]
    DIRECTION OUTPUT ;
    USE SIGNAL ;
    ANTENNADIFFAREA 0.702900 ;
    PORT
      LAYER met3 ;
        RECT 0.000 39.480 0.600 40.080 ;
    END
  END Tile_X0Y1_W2BEG[7]
  PIN Tile_X0Y1_W2BEGb[0]
    DIRECTION OUTPUT ;
    USE SIGNAL ;
    ANTENNADIFFAREA 0.702900 ;
    PORT
      LAYER met3 ;
        RECT 0.000 40.840 0.600 41.440 ;
    END
  END Tile_X0Y1_W2BEGb[0]
  PIN Tile_X0Y1_W2BEGb[1]
    DIRECTION OUTPUT ;
    USE SIGNAL ;
    ANTENNADIFFAREA 0.702900 ;
    PORT
      LAYER met3 ;
        RECT 0.000 42.200 0.600 42.800 ;
    END
  END Tile_X0Y1_W2BEGb[1]
  PIN Tile_X0Y1_W2BEGb[2]
    DIRECTION OUTPUT ;
    USE SIGNAL ;
    ANTENNADIFFAREA 0.702900 ;
    PORT
      LAYER met3 ;
        RECT 0.000 43.560 0.600 44.160 ;
    END
  END Tile_X0Y1_W2BEGb[2]
  PIN Tile_X0Y1_W2BEGb[3]
    DIRECTION OUTPUT ;
    USE SIGNAL ;
    ANTENNADIFFAREA 0.702900 ;
    PORT
      LAYER met3 ;
        RECT 0.000 44.920 0.600 45.520 ;
    END
  END Tile_X0Y1_W2BEGb[3]
  PIN Tile_X0Y1_W2BEGb[4]
    DIRECTION OUTPUT ;
    USE SIGNAL ;
    ANTENNADIFFAREA 0.702900 ;
    PORT
      LAYER met3 ;
        RECT 0.000 46.280 0.600 46.880 ;
    END
  END Tile_X0Y1_W2BEGb[4]
  PIN Tile_X0Y1_W2BEGb[5]
    DIRECTION OUTPUT ;
    USE SIGNAL ;
    ANTENNADIFFAREA 0.702900 ;
    PORT
      LAYER met3 ;
        RECT 0.000 47.640 0.600 48.240 ;
    END
  END Tile_X0Y1_W2BEGb[5]
  PIN Tile_X0Y1_W2BEGb[6]
    DIRECTION OUTPUT ;
    USE SIGNAL ;
    ANTENNADIFFAREA 0.702900 ;
    PORT
      LAYER met3 ;
        RECT 0.000 49.000 0.600 49.600 ;
    END
  END Tile_X0Y1_W2BEGb[6]
  PIN Tile_X0Y1_W2BEGb[7]
    DIRECTION OUTPUT ;
    USE SIGNAL ;
    ANTENNADIFFAREA 0.702900 ;
    PORT
      LAYER met3 ;
        RECT 0.000 50.360 0.600 50.960 ;
    END
  END Tile_X0Y1_W2BEGb[7]
  PIN Tile_X0Y1_W2END[0]
    DIRECTION INPUT ;
    USE SIGNAL ;
    ANTENNAGATEAREA 1.346400 ;
    ANTENNADIFFAREA 0.869400 ;
    PORT
      LAYER met3 ;
        RECT 219.280 40.840 219.880 41.440 ;
    END
  END Tile_X0Y1_W2END[0]
  PIN Tile_X0Y1_W2END[1]
    DIRECTION INPUT ;
    USE SIGNAL ;
    ANTENNAGATEAREA 0.921000 ;
    PORT
      LAYER met3 ;
        RECT 219.280 42.200 219.880 42.800 ;
    END
  END Tile_X0Y1_W2END[1]
  PIN Tile_X0Y1_W2END[2]
    DIRECTION INPUT ;
    USE SIGNAL ;
    ANTENNAGATEAREA 0.954000 ;
    PORT
      LAYER met3 ;
        RECT 219.280 43.560 219.880 44.160 ;
    END
  END Tile_X0Y1_W2END[2]
  PIN Tile_X0Y1_W2END[3]
    DIRECTION INPUT ;
    USE SIGNAL ;
    ANTENNAGATEAREA 1.449000 ;
    PORT
      LAYER met3 ;
        RECT 219.280 44.920 219.880 45.520 ;
    END
  END Tile_X0Y1_W2END[3]
  PIN Tile_X0Y1_W2END[4]
    DIRECTION INPUT ;
    USE SIGNAL ;
    ANTENNAGATEAREA 3.445500 ;
    ANTENNADIFFAREA 2.173500 ;
    PORT
      LAYER met3 ;
        RECT 219.280 46.280 219.880 46.880 ;
    END
  END Tile_X0Y1_W2END[4]
  PIN Tile_X0Y1_W2END[5]
    DIRECTION INPUT ;
    USE SIGNAL ;
    ANTENNAGATEAREA 1.187400 ;
    ANTENNADIFFAREA 0.869400 ;
    PORT
      LAYER met3 ;
        RECT 219.280 47.640 219.880 48.240 ;
    END
  END Tile_X0Y1_W2END[5]
  PIN Tile_X0Y1_W2END[6]
    DIRECTION INPUT ;
    USE SIGNAL ;
    ANTENNAGATEAREA 0.318000 ;
    PORT
      LAYER met3 ;
        RECT 219.280 49.000 219.880 49.600 ;
    END
  END Tile_X0Y1_W2END[6]
  PIN Tile_X0Y1_W2END[7]
    DIRECTION INPUT ;
    USE SIGNAL ;
    ANTENNAGATEAREA 2.028600 ;
    ANTENNADIFFAREA 1.304100 ;
    PORT
      LAYER met3 ;
        RECT 219.280 50.360 219.880 50.960 ;
    END
  END Tile_X0Y1_W2END[7]
  PIN Tile_X0Y1_W2MID[0]
    DIRECTION INPUT ;
    USE SIGNAL ;
    ANTENNAGATEAREA 1.396500 ;
    PORT
      LAYER met3 ;
        RECT 219.280 29.960 219.880 30.560 ;
    END
  END Tile_X0Y1_W2MID[0]
  PIN Tile_X0Y1_W2MID[1]
    DIRECTION INPUT ;
    USE SIGNAL ;
    ANTENNAGATEAREA 1.065000 ;
    PORT
      LAYER met3 ;
        RECT 219.280 31.320 219.880 31.920 ;
    END
  END Tile_X0Y1_W2MID[1]
  PIN Tile_X0Y1_W2MID[2]
    DIRECTION INPUT ;
    USE SIGNAL ;
    ANTENNAGATEAREA 2.463300 ;
    ANTENNADIFFAREA 1.738800 ;
    PORT
      LAYER met3 ;
        RECT 219.280 32.680 219.880 33.280 ;
    END
  END Tile_X0Y1_W2MID[2]
  PIN Tile_X0Y1_W2MID[3]
    DIRECTION INPUT ;
    USE SIGNAL ;
    ANTENNAGATEAREA 1.229700 ;
    ANTENNADIFFAREA 0.434700 ;
    PORT
      LAYER met3 ;
        RECT 219.280 34.040 219.880 34.640 ;
    END
  END Tile_X0Y1_W2MID[3]
  PIN Tile_X0Y1_W2MID[4]
    DIRECTION INPUT ;
    USE SIGNAL ;
    ANTENNAGATEAREA 1.406700 ;
    ANTENNADIFFAREA 0.434700 ;
    PORT
      LAYER met3 ;
        RECT 219.280 35.400 219.880 36.000 ;
    END
  END Tile_X0Y1_W2MID[4]
  PIN Tile_X0Y1_W2MID[5]
    DIRECTION INPUT ;
    USE SIGNAL ;
    ANTENNAGATEAREA 1.901700 ;
    ANTENNADIFFAREA 0.434700 ;
    PORT
      LAYER met3 ;
        RECT 219.280 36.760 219.880 37.360 ;
    END
  END Tile_X0Y1_W2MID[5]
  PIN Tile_X0Y1_W2MID[6]
    DIRECTION INPUT ;
    USE SIGNAL ;
    ANTENNAGATEAREA 1.593900 ;
    ANTENNADIFFAREA 0.869400 ;
    PORT
      LAYER met3 ;
        RECT 219.280 38.120 219.880 38.720 ;
    END
  END Tile_X0Y1_W2MID[6]
  PIN Tile_X0Y1_W2MID[7]
    DIRECTION INPUT ;
    USE SIGNAL ;
    ANTENNAGATEAREA 1.466700 ;
    ANTENNADIFFAREA 0.434700 ;
    PORT
      LAYER met3 ;
        RECT 219.280 39.480 219.880 40.080 ;
    END
  END Tile_X0Y1_W2MID[7]
  PIN Tile_X0Y1_W6BEG[0]
    DIRECTION OUTPUT ;
    USE SIGNAL ;
    ANTENNADIFFAREA 0.702900 ;
    PORT
      LAYER met3 ;
        RECT 0.000 73.480 0.600 74.080 ;
    END
  END Tile_X0Y1_W6BEG[0]
  PIN Tile_X0Y1_W6BEG[10]
    DIRECTION OUTPUT ;
    USE SIGNAL ;
    ANTENNADIFFAREA 0.702900 ;
    PORT
      LAYER met3 ;
        RECT 0.000 87.080 0.600 87.680 ;
    END
  END Tile_X0Y1_W6BEG[10]
  PIN Tile_X0Y1_W6BEG[11]
    DIRECTION OUTPUT ;
    USE SIGNAL ;
    ANTENNADIFFAREA 0.702900 ;
    PORT
      LAYER met3 ;
        RECT 0.000 88.440 0.600 89.040 ;
    END
  END Tile_X0Y1_W6BEG[11]
  PIN Tile_X0Y1_W6BEG[1]
    DIRECTION OUTPUT ;
    USE SIGNAL ;
    ANTENNADIFFAREA 0.702900 ;
    PORT
      LAYER met3 ;
        RECT 0.000 74.840 0.600 75.440 ;
    END
  END Tile_X0Y1_W6BEG[1]
  PIN Tile_X0Y1_W6BEG[2]
    DIRECTION OUTPUT ;
    USE SIGNAL ;
    ANTENNADIFFAREA 0.702900 ;
    PORT
      LAYER met3 ;
        RECT 0.000 76.200 0.600 76.800 ;
    END
  END Tile_X0Y1_W6BEG[2]
  PIN Tile_X0Y1_W6BEG[3]
    DIRECTION OUTPUT ;
    USE SIGNAL ;
    ANTENNADIFFAREA 0.702900 ;
    PORT
      LAYER met3 ;
        RECT 0.000 77.560 0.600 78.160 ;
    END
  END Tile_X0Y1_W6BEG[3]
  PIN Tile_X0Y1_W6BEG[4]
    DIRECTION OUTPUT ;
    USE SIGNAL ;
    ANTENNADIFFAREA 0.702900 ;
    PORT
      LAYER met3 ;
        RECT 0.000 78.920 0.600 79.520 ;
    END
  END Tile_X0Y1_W6BEG[4]
  PIN Tile_X0Y1_W6BEG[5]
    DIRECTION OUTPUT ;
    USE SIGNAL ;
    ANTENNADIFFAREA 0.702900 ;
    PORT
      LAYER met3 ;
        RECT 0.000 80.280 0.600 80.880 ;
    END
  END Tile_X0Y1_W6BEG[5]
  PIN Tile_X0Y1_W6BEG[6]
    DIRECTION OUTPUT ;
    USE SIGNAL ;
    ANTENNADIFFAREA 0.702900 ;
    PORT
      LAYER met3 ;
        RECT 0.000 81.640 0.600 82.240 ;
    END
  END Tile_X0Y1_W6BEG[6]
  PIN Tile_X0Y1_W6BEG[7]
    DIRECTION OUTPUT ;
    USE SIGNAL ;
    ANTENNADIFFAREA 0.702900 ;
    PORT
      LAYER met3 ;
        RECT 0.000 83.000 0.600 83.600 ;
    END
  END Tile_X0Y1_W6BEG[7]
  PIN Tile_X0Y1_W6BEG[8]
    DIRECTION OUTPUT ;
    USE SIGNAL ;
    ANTENNADIFFAREA 0.702900 ;
    PORT
      LAYER met3 ;
        RECT 0.000 84.360 0.600 84.960 ;
    END
  END Tile_X0Y1_W6BEG[8]
  PIN Tile_X0Y1_W6BEG[9]
    DIRECTION OUTPUT ;
    USE SIGNAL ;
    ANTENNADIFFAREA 0.702900 ;
    PORT
      LAYER met3 ;
        RECT 0.000 85.720 0.600 86.320 ;
    END
  END Tile_X0Y1_W6BEG[9]
  PIN Tile_X0Y1_W6END[0]
    DIRECTION INPUT ;
    USE SIGNAL ;
    ANTENNAGATEAREA 1.431000 ;
    PORT
      LAYER met3 ;
        RECT 219.280 73.480 219.880 74.080 ;
    END
  END Tile_X0Y1_W6END[0]
  PIN Tile_X0Y1_W6END[10]
    DIRECTION INPUT ;
    USE SIGNAL ;
    ANTENNAGATEAREA 0.159000 ;
    PORT
      LAYER met3 ;
        RECT 219.280 87.080 219.880 87.680 ;
    END
  END Tile_X0Y1_W6END[10]
  PIN Tile_X0Y1_W6END[11]
    DIRECTION INPUT ;
    USE SIGNAL ;
    ANTENNAGATEAREA 0.159000 ;
    PORT
      LAYER met3 ;
        RECT 219.280 88.440 219.880 89.040 ;
    END
  END Tile_X0Y1_W6END[11]
  PIN Tile_X0Y1_W6END[1]
    DIRECTION INPUT ;
    USE SIGNAL ;
    ANTENNAGATEAREA 1.678500 ;
    PORT
      LAYER met3 ;
        RECT 219.280 74.840 219.880 75.440 ;
    END
  END Tile_X0Y1_W6END[1]
  PIN Tile_X0Y1_W6END[2]
    DIRECTION INPUT ;
    USE SIGNAL ;
    ANTENNAGATEAREA 0.159000 ;
    PORT
      LAYER met3 ;
        RECT 219.280 76.200 219.880 76.800 ;
    END
  END Tile_X0Y1_W6END[2]
  PIN Tile_X0Y1_W6END[3]
    DIRECTION INPUT ;
    USE SIGNAL ;
    ANTENNAGATEAREA 0.159000 ;
    PORT
      LAYER met3 ;
        RECT 219.280 77.560 219.880 78.160 ;
    END
  END Tile_X0Y1_W6END[3]
  PIN Tile_X0Y1_W6END[4]
    DIRECTION INPUT ;
    USE SIGNAL ;
    ANTENNAGATEAREA 0.159000 ;
    PORT
      LAYER met3 ;
        RECT 219.280 78.920 219.880 79.520 ;
    END
  END Tile_X0Y1_W6END[4]
  PIN Tile_X0Y1_W6END[5]
    DIRECTION INPUT ;
    USE SIGNAL ;
    ANTENNAGATEAREA 0.159000 ;
    PORT
      LAYER met3 ;
        RECT 219.280 80.280 219.880 80.880 ;
    END
  END Tile_X0Y1_W6END[5]
  PIN Tile_X0Y1_W6END[6]
    DIRECTION INPUT ;
    USE SIGNAL ;
    ANTENNAGATEAREA 0.159000 ;
    PORT
      LAYER met3 ;
        RECT 219.280 81.640 219.880 82.240 ;
    END
  END Tile_X0Y1_W6END[6]
  PIN Tile_X0Y1_W6END[7]
    DIRECTION INPUT ;
    USE SIGNAL ;
    ANTENNAGATEAREA 0.159000 ;
    PORT
      LAYER met3 ;
        RECT 219.280 83.000 219.880 83.600 ;
    END
  END Tile_X0Y1_W6END[7]
  PIN Tile_X0Y1_W6END[8]
    DIRECTION INPUT ;
    USE SIGNAL ;
    ANTENNAGATEAREA 0.159000 ;
    PORT
      LAYER met3 ;
        RECT 219.280 84.360 219.880 84.960 ;
    END
  END Tile_X0Y1_W6END[8]
  PIN Tile_X0Y1_W6END[9]
    DIRECTION INPUT ;
    USE SIGNAL ;
    ANTENNAGATEAREA 0.159000 ;
    PORT
      LAYER met3 ;
        RECT 219.280 85.720 219.880 86.320 ;
    END
  END Tile_X0Y1_W6END[9]
  PIN Tile_X0Y1_WW4BEG[0]
    DIRECTION OUTPUT ;
    USE SIGNAL ;
    ANTENNADIFFAREA 0.702900 ;
    PORT
      LAYER met3 ;
        RECT 0.000 51.720 0.600 52.320 ;
    END
  END Tile_X0Y1_WW4BEG[0]
  PIN Tile_X0Y1_WW4BEG[10]
    DIRECTION OUTPUT ;
    USE SIGNAL ;
    ANTENNADIFFAREA 0.702900 ;
    PORT
      LAYER met3 ;
        RECT 0.000 65.320 0.600 65.920 ;
    END
  END Tile_X0Y1_WW4BEG[10]
  PIN Tile_X0Y1_WW4BEG[11]
    DIRECTION OUTPUT ;
    USE SIGNAL ;
    ANTENNADIFFAREA 0.702900 ;
    PORT
      LAYER met3 ;
        RECT 0.000 66.680 0.600 67.280 ;
    END
  END Tile_X0Y1_WW4BEG[11]
  PIN Tile_X0Y1_WW4BEG[12]
    DIRECTION OUTPUT ;
    USE SIGNAL ;
    ANTENNADIFFAREA 0.702900 ;
    PORT
      LAYER met3 ;
        RECT 0.000 68.040 0.600 68.640 ;
    END
  END Tile_X0Y1_WW4BEG[12]
  PIN Tile_X0Y1_WW4BEG[13]
    DIRECTION OUTPUT ;
    USE SIGNAL ;
    ANTENNADIFFAREA 0.702900 ;
    PORT
      LAYER met3 ;
        RECT 0.000 69.400 0.600 70.000 ;
    END
  END Tile_X0Y1_WW4BEG[13]
  PIN Tile_X0Y1_WW4BEG[14]
    DIRECTION OUTPUT ;
    USE SIGNAL ;
    ANTENNADIFFAREA 0.702900 ;
    PORT
      LAYER met3 ;
        RECT 0.000 70.760 0.600 71.360 ;
    END
  END Tile_X0Y1_WW4BEG[14]
  PIN Tile_X0Y1_WW4BEG[15]
    DIRECTION OUTPUT ;
    USE SIGNAL ;
    ANTENNADIFFAREA 0.702900 ;
    PORT
      LAYER met3 ;
        RECT 0.000 72.120 0.600 72.720 ;
    END
  END Tile_X0Y1_WW4BEG[15]
  PIN Tile_X0Y1_WW4BEG[1]
    DIRECTION OUTPUT ;
    USE SIGNAL ;
    ANTENNADIFFAREA 0.702900 ;
    PORT
      LAYER met3 ;
        RECT 0.000 53.080 0.600 53.680 ;
    END
  END Tile_X0Y1_WW4BEG[1]
  PIN Tile_X0Y1_WW4BEG[2]
    DIRECTION OUTPUT ;
    USE SIGNAL ;
    ANTENNADIFFAREA 0.702900 ;
    PORT
      LAYER met3 ;
        RECT 0.000 54.440 0.600 55.040 ;
    END
  END Tile_X0Y1_WW4BEG[2]
  PIN Tile_X0Y1_WW4BEG[3]
    DIRECTION OUTPUT ;
    USE SIGNAL ;
    ANTENNADIFFAREA 0.702900 ;
    PORT
      LAYER met3 ;
        RECT 0.000 55.800 0.600 56.400 ;
    END
  END Tile_X0Y1_WW4BEG[3]
  PIN Tile_X0Y1_WW4BEG[4]
    DIRECTION OUTPUT ;
    USE SIGNAL ;
    ANTENNADIFFAREA 0.702900 ;
    PORT
      LAYER met3 ;
        RECT 0.000 57.160 0.600 57.760 ;
    END
  END Tile_X0Y1_WW4BEG[4]
  PIN Tile_X0Y1_WW4BEG[5]
    DIRECTION OUTPUT ;
    USE SIGNAL ;
    ANTENNADIFFAREA 0.702900 ;
    PORT
      LAYER met3 ;
        RECT 0.000 58.520 0.600 59.120 ;
    END
  END Tile_X0Y1_WW4BEG[5]
  PIN Tile_X0Y1_WW4BEG[6]
    DIRECTION OUTPUT ;
    USE SIGNAL ;
    ANTENNADIFFAREA 0.702900 ;
    PORT
      LAYER met3 ;
        RECT 0.000 59.880 0.600 60.480 ;
    END
  END Tile_X0Y1_WW4BEG[6]
  PIN Tile_X0Y1_WW4BEG[7]
    DIRECTION OUTPUT ;
    USE SIGNAL ;
    ANTENNADIFFAREA 0.702900 ;
    PORT
      LAYER met3 ;
        RECT 0.000 61.240 0.600 61.840 ;
    END
  END Tile_X0Y1_WW4BEG[7]
  PIN Tile_X0Y1_WW4BEG[8]
    DIRECTION OUTPUT ;
    USE SIGNAL ;
    ANTENNADIFFAREA 0.702900 ;
    PORT
      LAYER met3 ;
        RECT 0.000 62.600 0.600 63.200 ;
    END
  END Tile_X0Y1_WW4BEG[8]
  PIN Tile_X0Y1_WW4BEG[9]
    DIRECTION OUTPUT ;
    USE SIGNAL ;
    ANTENNADIFFAREA 0.702900 ;
    PORT
      LAYER met3 ;
        RECT 0.000 63.960 0.600 64.560 ;
    END
  END Tile_X0Y1_WW4BEG[9]
  PIN Tile_X0Y1_WW4END[0]
    DIRECTION INPUT ;
    USE SIGNAL ;
    ANTENNAGATEAREA 0.813000 ;
    PORT
      LAYER met3 ;
        RECT 219.280 51.720 219.880 52.320 ;
    END
  END Tile_X0Y1_WW4END[0]
  PIN Tile_X0Y1_WW4END[10]
    DIRECTION INPUT ;
    USE SIGNAL ;
    ANTENNAGATEAREA 0.159000 ;
    PORT
      LAYER met3 ;
        RECT 219.280 65.320 219.880 65.920 ;
    END
  END Tile_X0Y1_WW4END[10]
  PIN Tile_X0Y1_WW4END[11]
    DIRECTION INPUT ;
    USE SIGNAL ;
    ANTENNAGATEAREA 0.159000 ;
    PORT
      LAYER met3 ;
        RECT 219.280 66.680 219.880 67.280 ;
    END
  END Tile_X0Y1_WW4END[11]
  PIN Tile_X0Y1_WW4END[12]
    DIRECTION INPUT ;
    USE SIGNAL ;
    ANTENNAGATEAREA 0.159000 ;
    PORT
      LAYER met3 ;
        RECT 219.280 68.040 219.880 68.640 ;
    END
  END Tile_X0Y1_WW4END[12]
  PIN Tile_X0Y1_WW4END[13]
    DIRECTION INPUT ;
    USE SIGNAL ;
    ANTENNAGATEAREA 0.159000 ;
    PORT
      LAYER met3 ;
        RECT 219.280 69.400 219.880 70.000 ;
    END
  END Tile_X0Y1_WW4END[13]
  PIN Tile_X0Y1_WW4END[14]
    DIRECTION INPUT ;
    USE SIGNAL ;
    ANTENNAGATEAREA 0.159000 ;
    PORT
      LAYER met3 ;
        RECT 219.280 70.760 219.880 71.360 ;
    END
  END Tile_X0Y1_WW4END[14]
  PIN Tile_X0Y1_WW4END[15]
    DIRECTION INPUT ;
    USE SIGNAL ;
    ANTENNAGATEAREA 0.159000 ;
    PORT
      LAYER met3 ;
        RECT 219.280 72.120 219.880 72.720 ;
    END
  END Tile_X0Y1_WW4END[15]
  PIN Tile_X0Y1_WW4END[1]
    DIRECTION INPUT ;
    USE SIGNAL ;
    ANTENNAGATEAREA 0.813000 ;
    PORT
      LAYER met3 ;
        RECT 219.280 53.080 219.880 53.680 ;
    END
  END Tile_X0Y1_WW4END[1]
  PIN Tile_X0Y1_WW4END[2]
    DIRECTION INPUT ;
    USE SIGNAL ;
    ANTENNAGATEAREA 0.911700 ;
    ANTENNADIFFAREA 0.434700 ;
    PORT
      LAYER met3 ;
        RECT 219.280 54.440 219.880 55.040 ;
    END
  END Tile_X0Y1_WW4END[2]
  PIN Tile_X0Y1_WW4END[3]
    DIRECTION INPUT ;
    USE SIGNAL ;
    ANTENNAGATEAREA 1.781100 ;
    ANTENNADIFFAREA 1.304100 ;
    PORT
      LAYER met3 ;
        RECT 219.280 55.800 219.880 56.400 ;
    END
  END Tile_X0Y1_WW4END[3]
  PIN Tile_X0Y1_WW4END[4]
    DIRECTION INPUT ;
    USE SIGNAL ;
    ANTENNAGATEAREA 0.159000 ;
    PORT
      LAYER met3 ;
        RECT 219.280 57.160 219.880 57.760 ;
    END
  END Tile_X0Y1_WW4END[4]
  PIN Tile_X0Y1_WW4END[5]
    DIRECTION INPUT ;
    USE SIGNAL ;
    ANTENNAGATEAREA 0.159000 ;
    PORT
      LAYER met3 ;
        RECT 219.280 58.520 219.880 59.120 ;
    END
  END Tile_X0Y1_WW4END[5]
  PIN Tile_X0Y1_WW4END[6]
    DIRECTION INPUT ;
    USE SIGNAL ;
    ANTENNAGATEAREA 0.159000 ;
    PORT
      LAYER met3 ;
        RECT 219.280 59.880 219.880 60.480 ;
    END
  END Tile_X0Y1_WW4END[6]
  PIN Tile_X0Y1_WW4END[7]
    DIRECTION INPUT ;
    USE SIGNAL ;
    ANTENNAGATEAREA 0.159000 ;
    PORT
      LAYER met3 ;
        RECT 219.280 61.240 219.880 61.840 ;
    END
  END Tile_X0Y1_WW4END[7]
  PIN Tile_X0Y1_WW4END[8]
    DIRECTION INPUT ;
    USE SIGNAL ;
    ANTENNAGATEAREA 0.159000 ;
    PORT
      LAYER met3 ;
        RECT 219.280 62.600 219.880 63.200 ;
    END
  END Tile_X0Y1_WW4END[8]
  PIN Tile_X0Y1_WW4END[9]
    DIRECTION INPUT ;
    USE SIGNAL ;
    ANTENNAGATEAREA 0.159000 ;
    PORT
      LAYER met3 ;
        RECT 219.280 63.960 219.880 64.560 ;
    END
  END Tile_X0Y1_WW4END[9]
  PIN VGND
    DIRECTION INOUT ;
    USE GROUND ;
    PORT
      LAYER met4 ;
        RECT 12.260 0.000 13.860 446.080 ;
    END
    PORT
      LAYER met4 ;
        RECT 42.260 0.000 43.860 446.080 ;
    END
    PORT
      LAYER met4 ;
        RECT 72.260 0.000 73.860 446.080 ;
    END
    PORT
      LAYER met4 ;
        RECT 102.260 0.000 103.860 446.080 ;
    END
    PORT
      LAYER met4 ;
        RECT 132.260 0.000 133.860 446.080 ;
    END
    PORT
      LAYER met4 ;
        RECT 162.260 0.000 163.860 446.080 ;
    END
    PORT
      LAYER met4 ;
        RECT 192.260 0.000 193.860 446.080 ;
    END
  END VGND
  PIN VPWR
    DIRECTION INOUT ;
    USE POWER ;
    PORT
      LAYER met4 ;
        RECT 6.960 0.000 8.560 446.080 ;
    END
    PORT
      LAYER met4 ;
        RECT 36.960 0.000 38.560 446.080 ;
    END
    PORT
      LAYER met4 ;
        RECT 66.960 0.000 68.560 446.080 ;
    END
    PORT
      LAYER met4 ;
        RECT 96.960 0.000 98.560 446.080 ;
    END
    PORT
      LAYER met4 ;
        RECT 126.960 0.000 128.560 446.080 ;
    END
    PORT
      LAYER met4 ;
        RECT 156.960 0.000 158.560 446.080 ;
    END
    PORT
      LAYER met4 ;
        RECT 186.960 0.000 188.560 446.080 ;
    END
  END VPWR
  OBS
      LAYER nwell ;
        RECT 2.570 2.635 217.310 443.445 ;
      LAYER li1 ;
        RECT 2.760 2.635 217.120 443.445 ;
      LAYER met1 ;
        RECT 0.530 0.380 219.350 445.700 ;
      LAYER met2 ;
        RECT 0.550 445.520 20.970 445.810 ;
        RECT 21.810 445.520 22.350 445.810 ;
        RECT 23.190 445.520 23.730 445.810 ;
        RECT 24.570 445.520 25.110 445.810 ;
        RECT 25.950 445.520 26.490 445.810 ;
        RECT 27.330 445.520 27.870 445.810 ;
        RECT 28.710 445.520 29.250 445.810 ;
        RECT 30.090 445.520 30.630 445.810 ;
        RECT 31.470 445.520 32.010 445.810 ;
        RECT 32.850 445.520 33.390 445.810 ;
        RECT 34.230 445.520 34.770 445.810 ;
        RECT 35.610 445.520 36.150 445.810 ;
        RECT 36.990 445.520 37.530 445.810 ;
        RECT 38.370 445.520 38.910 445.810 ;
        RECT 39.750 445.520 40.290 445.810 ;
        RECT 41.130 445.520 41.670 445.810 ;
        RECT 42.510 445.520 43.050 445.810 ;
        RECT 43.890 445.520 44.430 445.810 ;
        RECT 45.270 445.520 45.810 445.810 ;
        RECT 46.650 445.520 47.190 445.810 ;
        RECT 48.030 445.520 48.570 445.810 ;
        RECT 49.410 445.520 49.950 445.810 ;
        RECT 50.790 445.520 51.330 445.810 ;
        RECT 52.170 445.520 52.710 445.810 ;
        RECT 53.550 445.520 54.090 445.810 ;
        RECT 54.930 445.520 55.470 445.810 ;
        RECT 56.310 445.520 56.850 445.810 ;
        RECT 57.690 445.520 58.230 445.810 ;
        RECT 59.070 445.520 59.610 445.810 ;
        RECT 60.450 445.520 60.990 445.810 ;
        RECT 61.830 445.520 62.370 445.810 ;
        RECT 63.210 445.520 63.750 445.810 ;
        RECT 64.590 445.520 65.130 445.810 ;
        RECT 65.970 445.520 66.510 445.810 ;
        RECT 67.350 445.520 67.890 445.810 ;
        RECT 68.730 445.520 69.270 445.810 ;
        RECT 70.110 445.520 70.650 445.810 ;
        RECT 71.490 445.520 72.030 445.810 ;
        RECT 72.870 445.520 73.410 445.810 ;
        RECT 74.250 445.520 74.790 445.810 ;
        RECT 75.630 445.520 76.170 445.810 ;
        RECT 77.010 445.520 77.550 445.810 ;
        RECT 78.390 445.520 78.930 445.810 ;
        RECT 79.770 445.520 80.310 445.810 ;
        RECT 81.150 445.520 81.690 445.810 ;
        RECT 82.530 445.520 83.070 445.810 ;
        RECT 83.910 445.520 84.450 445.810 ;
        RECT 85.290 445.520 85.830 445.810 ;
        RECT 86.670 445.520 87.210 445.810 ;
        RECT 88.050 445.520 88.590 445.810 ;
        RECT 89.430 445.520 89.970 445.810 ;
        RECT 90.810 445.520 91.350 445.810 ;
        RECT 92.190 445.520 92.730 445.810 ;
        RECT 93.570 445.520 94.110 445.810 ;
        RECT 94.950 445.520 95.490 445.810 ;
        RECT 96.330 445.520 96.870 445.810 ;
        RECT 97.710 445.520 98.250 445.810 ;
        RECT 99.090 445.520 99.630 445.810 ;
        RECT 100.470 445.520 101.010 445.810 ;
        RECT 101.850 445.520 102.390 445.810 ;
        RECT 103.230 445.520 103.770 445.810 ;
        RECT 104.610 445.520 105.150 445.810 ;
        RECT 105.990 445.520 106.530 445.810 ;
        RECT 107.370 445.520 107.910 445.810 ;
        RECT 108.750 445.520 109.290 445.810 ;
        RECT 110.130 445.520 110.670 445.810 ;
        RECT 111.510 445.520 112.050 445.810 ;
        RECT 112.890 445.520 113.430 445.810 ;
        RECT 114.270 445.520 114.810 445.810 ;
        RECT 115.650 445.520 116.190 445.810 ;
        RECT 117.030 445.520 117.570 445.810 ;
        RECT 118.410 445.520 118.950 445.810 ;
        RECT 119.790 445.520 120.330 445.810 ;
        RECT 121.170 445.520 121.710 445.810 ;
        RECT 122.550 445.520 123.090 445.810 ;
        RECT 123.930 445.520 124.470 445.810 ;
        RECT 125.310 445.520 125.850 445.810 ;
        RECT 126.690 445.520 127.230 445.810 ;
        RECT 128.070 445.520 128.610 445.810 ;
        RECT 129.450 445.520 129.990 445.810 ;
        RECT 130.830 445.520 131.370 445.810 ;
        RECT 132.210 445.520 132.750 445.810 ;
        RECT 133.590 445.520 134.130 445.810 ;
        RECT 134.970 445.520 135.510 445.810 ;
        RECT 136.350 445.520 136.890 445.810 ;
        RECT 137.730 445.520 138.270 445.810 ;
        RECT 139.110 445.520 139.650 445.810 ;
        RECT 140.490 445.520 141.030 445.810 ;
        RECT 141.870 445.520 142.410 445.810 ;
        RECT 143.250 445.520 143.790 445.810 ;
        RECT 144.630 445.520 145.170 445.810 ;
        RECT 146.010 445.520 146.550 445.810 ;
        RECT 147.390 445.520 147.930 445.810 ;
        RECT 148.770 445.520 149.310 445.810 ;
        RECT 150.150 445.520 150.690 445.810 ;
        RECT 151.530 445.520 152.070 445.810 ;
        RECT 152.910 445.520 153.450 445.810 ;
        RECT 154.290 445.520 154.830 445.810 ;
        RECT 155.670 445.520 156.210 445.810 ;
        RECT 157.050 445.520 157.590 445.810 ;
        RECT 158.430 445.520 158.970 445.810 ;
        RECT 159.810 445.520 160.350 445.810 ;
        RECT 161.190 445.520 161.730 445.810 ;
        RECT 162.570 445.520 163.110 445.810 ;
        RECT 163.950 445.520 164.490 445.810 ;
        RECT 165.330 445.520 165.870 445.810 ;
        RECT 166.710 445.520 167.250 445.810 ;
        RECT 168.090 445.520 168.630 445.810 ;
        RECT 169.470 445.520 170.010 445.810 ;
        RECT 170.850 445.520 171.390 445.810 ;
        RECT 172.230 445.520 172.770 445.810 ;
        RECT 173.610 445.520 174.150 445.810 ;
        RECT 174.990 445.520 175.530 445.810 ;
        RECT 176.370 445.520 176.910 445.810 ;
        RECT 177.750 445.520 178.290 445.810 ;
        RECT 179.130 445.520 179.670 445.810 ;
        RECT 180.510 445.520 181.050 445.810 ;
        RECT 181.890 445.520 182.430 445.810 ;
        RECT 183.270 445.520 183.810 445.810 ;
        RECT 184.650 445.520 185.190 445.810 ;
        RECT 186.030 445.520 186.570 445.810 ;
        RECT 187.410 445.520 187.950 445.810 ;
        RECT 188.790 445.520 189.330 445.810 ;
        RECT 190.170 445.520 190.710 445.810 ;
        RECT 191.550 445.520 192.090 445.810 ;
        RECT 192.930 445.520 193.470 445.810 ;
        RECT 194.310 445.520 194.850 445.810 ;
        RECT 195.690 445.520 196.230 445.810 ;
        RECT 197.070 445.520 197.610 445.810 ;
        RECT 198.450 445.520 219.330 445.810 ;
        RECT 0.550 0.560 219.330 445.520 ;
        RECT 0.550 0.270 20.970 0.560 ;
        RECT 21.810 0.270 22.350 0.560 ;
        RECT 23.190 0.270 23.730 0.560 ;
        RECT 24.570 0.270 25.110 0.560 ;
        RECT 25.950 0.270 26.490 0.560 ;
        RECT 27.330 0.270 27.870 0.560 ;
        RECT 28.710 0.270 29.250 0.560 ;
        RECT 30.090 0.270 30.630 0.560 ;
        RECT 31.470 0.270 32.010 0.560 ;
        RECT 32.850 0.270 33.390 0.560 ;
        RECT 34.230 0.270 34.770 0.560 ;
        RECT 35.610 0.270 36.150 0.560 ;
        RECT 36.990 0.270 37.530 0.560 ;
        RECT 38.370 0.270 38.910 0.560 ;
        RECT 39.750 0.270 40.290 0.560 ;
        RECT 41.130 0.270 41.670 0.560 ;
        RECT 42.510 0.270 43.050 0.560 ;
        RECT 43.890 0.270 44.430 0.560 ;
        RECT 45.270 0.270 45.810 0.560 ;
        RECT 46.650 0.270 47.190 0.560 ;
        RECT 48.030 0.270 48.570 0.560 ;
        RECT 49.410 0.270 49.950 0.560 ;
        RECT 50.790 0.270 51.330 0.560 ;
        RECT 52.170 0.270 52.710 0.560 ;
        RECT 53.550 0.270 54.090 0.560 ;
        RECT 54.930 0.270 55.470 0.560 ;
        RECT 56.310 0.270 56.850 0.560 ;
        RECT 57.690 0.270 58.230 0.560 ;
        RECT 59.070 0.270 59.610 0.560 ;
        RECT 60.450 0.270 60.990 0.560 ;
        RECT 61.830 0.270 62.370 0.560 ;
        RECT 63.210 0.270 63.750 0.560 ;
        RECT 64.590 0.270 65.130 0.560 ;
        RECT 65.970 0.270 66.510 0.560 ;
        RECT 67.350 0.270 67.890 0.560 ;
        RECT 68.730 0.270 69.270 0.560 ;
        RECT 70.110 0.270 70.650 0.560 ;
        RECT 71.490 0.270 72.030 0.560 ;
        RECT 72.870 0.270 73.410 0.560 ;
        RECT 74.250 0.270 74.790 0.560 ;
        RECT 75.630 0.270 76.170 0.560 ;
        RECT 77.010 0.270 77.550 0.560 ;
        RECT 78.390 0.270 78.930 0.560 ;
        RECT 79.770 0.270 80.310 0.560 ;
        RECT 81.150 0.270 81.690 0.560 ;
        RECT 82.530 0.270 83.070 0.560 ;
        RECT 83.910 0.270 84.450 0.560 ;
        RECT 85.290 0.270 85.830 0.560 ;
        RECT 86.670 0.270 87.210 0.560 ;
        RECT 88.050 0.270 88.590 0.560 ;
        RECT 89.430 0.270 89.970 0.560 ;
        RECT 90.810 0.270 91.350 0.560 ;
        RECT 92.190 0.270 92.730 0.560 ;
        RECT 93.570 0.270 94.110 0.560 ;
        RECT 94.950 0.270 95.490 0.560 ;
        RECT 96.330 0.270 96.870 0.560 ;
        RECT 97.710 0.270 98.250 0.560 ;
        RECT 99.090 0.270 99.630 0.560 ;
        RECT 100.470 0.270 101.010 0.560 ;
        RECT 101.850 0.270 102.390 0.560 ;
        RECT 103.230 0.270 103.770 0.560 ;
        RECT 104.610 0.270 105.150 0.560 ;
        RECT 105.990 0.270 106.530 0.560 ;
        RECT 107.370 0.270 107.910 0.560 ;
        RECT 108.750 0.270 109.290 0.560 ;
        RECT 110.130 0.270 110.670 0.560 ;
        RECT 111.510 0.270 112.050 0.560 ;
        RECT 112.890 0.270 113.430 0.560 ;
        RECT 114.270 0.270 114.810 0.560 ;
        RECT 115.650 0.270 116.190 0.560 ;
        RECT 117.030 0.270 117.570 0.560 ;
        RECT 118.410 0.270 118.950 0.560 ;
        RECT 119.790 0.270 120.330 0.560 ;
        RECT 121.170 0.270 121.710 0.560 ;
        RECT 122.550 0.270 123.090 0.560 ;
        RECT 123.930 0.270 124.470 0.560 ;
        RECT 125.310 0.270 125.850 0.560 ;
        RECT 126.690 0.270 127.230 0.560 ;
        RECT 128.070 0.270 128.610 0.560 ;
        RECT 129.450 0.270 129.990 0.560 ;
        RECT 130.830 0.270 131.370 0.560 ;
        RECT 132.210 0.270 132.750 0.560 ;
        RECT 133.590 0.270 134.130 0.560 ;
        RECT 134.970 0.270 135.510 0.560 ;
        RECT 136.350 0.270 136.890 0.560 ;
        RECT 137.730 0.270 138.270 0.560 ;
        RECT 139.110 0.270 139.650 0.560 ;
        RECT 140.490 0.270 141.030 0.560 ;
        RECT 141.870 0.270 142.410 0.560 ;
        RECT 143.250 0.270 143.790 0.560 ;
        RECT 144.630 0.270 145.170 0.560 ;
        RECT 146.010 0.270 146.550 0.560 ;
        RECT 147.390 0.270 147.930 0.560 ;
        RECT 148.770 0.270 149.310 0.560 ;
        RECT 150.150 0.270 150.690 0.560 ;
        RECT 151.530 0.270 152.070 0.560 ;
        RECT 152.910 0.270 153.450 0.560 ;
        RECT 154.290 0.270 154.830 0.560 ;
        RECT 155.670 0.270 156.210 0.560 ;
        RECT 157.050 0.270 157.590 0.560 ;
        RECT 158.430 0.270 158.970 0.560 ;
        RECT 159.810 0.270 160.350 0.560 ;
        RECT 161.190 0.270 161.730 0.560 ;
        RECT 162.570 0.270 163.110 0.560 ;
        RECT 163.950 0.270 164.490 0.560 ;
        RECT 165.330 0.270 165.870 0.560 ;
        RECT 166.710 0.270 167.250 0.560 ;
        RECT 168.090 0.270 168.630 0.560 ;
        RECT 169.470 0.270 170.010 0.560 ;
        RECT 170.850 0.270 171.390 0.560 ;
        RECT 172.230 0.270 172.770 0.560 ;
        RECT 173.610 0.270 174.150 0.560 ;
        RECT 174.990 0.270 175.530 0.560 ;
        RECT 176.370 0.270 176.910 0.560 ;
        RECT 177.750 0.270 178.290 0.560 ;
        RECT 179.130 0.270 179.670 0.560 ;
        RECT 180.510 0.270 181.050 0.560 ;
        RECT 181.890 0.270 182.430 0.560 ;
        RECT 183.270 0.270 183.810 0.560 ;
        RECT 184.650 0.270 185.190 0.560 ;
        RECT 186.030 0.270 186.570 0.560 ;
        RECT 187.410 0.270 187.950 0.560 ;
        RECT 188.790 0.270 189.330 0.560 ;
        RECT 190.170 0.270 190.710 0.560 ;
        RECT 191.550 0.270 192.090 0.560 ;
        RECT 192.930 0.270 193.470 0.560 ;
        RECT 194.310 0.270 194.850 0.560 ;
        RECT 195.690 0.270 196.230 0.560 ;
        RECT 197.070 0.270 197.610 0.560 ;
        RECT 198.450 0.270 219.330 0.560 ;
      LAYER met3 ;
        RECT 0.600 421.280 219.280 445.225 ;
        RECT 1.000 247.160 218.880 421.280 ;
        RECT 0.600 198.240 219.280 247.160 ;
        RECT 1.000 24.120 218.880 198.240 ;
        RECT 0.600 0.855 219.280 24.120 ;
      LAYER met4 ;
        RECT 0.310 1.535 6.560 443.185 ;
        RECT 8.960 1.535 11.860 443.185 ;
        RECT 14.260 1.535 36.560 443.185 ;
        RECT 38.960 1.535 41.860 443.185 ;
        RECT 44.260 1.535 66.560 443.185 ;
        RECT 68.960 1.535 71.860 443.185 ;
        RECT 74.260 1.535 96.560 443.185 ;
        RECT 98.960 1.535 101.860 443.185 ;
        RECT 104.260 1.535 126.560 443.185 ;
        RECT 128.960 1.535 131.860 443.185 ;
        RECT 134.260 1.535 156.560 443.185 ;
        RECT 158.960 1.535 161.860 443.185 ;
        RECT 164.260 1.535 186.560 443.185 ;
        RECT 188.960 1.535 191.860 443.185 ;
        RECT 194.260 1.535 219.570 443.185 ;
  END
END MACC
END LIBRARY

